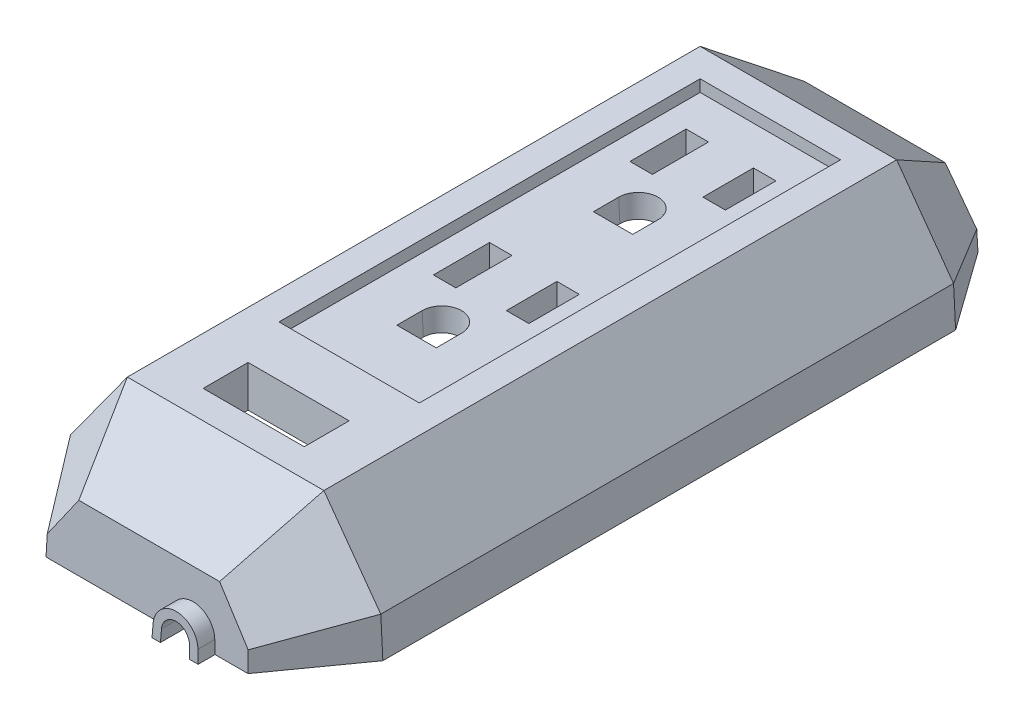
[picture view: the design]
ISO-10303-21;
HEADER;
FILE_DESCRIPTION(('STEP AP214'),'2;1');
FILE_NAME('part.step','',(''),(''),'','','');
FILE_SCHEMA(('AUTOMOTIVE_DESIGN { 1 0 10303 214 1 1 1 1 }'));
ENDSEC;
DATA;
#1=APPLICATION_CONTEXT('core data for automotive mechanical design processes');
#2=APPLICATION_PROTOCOL_DEFINITION('international standard','automotive_design',2000,#1);
#3=PRODUCT_CONTEXT('',#1,'mechanical');
#4=PRODUCT('Part','Part','',(#3));
#5=PRODUCT_RELATED_PRODUCT_CATEGORY('part','',(#4));
#6=PRODUCT_DEFINITION_FORMATION('','',#4);
#7=PRODUCT_DEFINITION_CONTEXT('part definition',#1,'design');
#8=PRODUCT_DEFINITION('design','',#6,#7);
#9=PRODUCT_DEFINITION_SHAPE('','',#8);
#10=(LENGTH_UNIT() NAMED_UNIT(*) SI_UNIT(.MILLI.,.METRE.));
#11=(NAMED_UNIT(*) PLANE_ANGLE_UNIT() SI_UNIT($,.RADIAN.));
#12=(NAMED_UNIT(*) SI_UNIT($,.STERADIAN.) SOLID_ANGLE_UNIT());
#13=UNCERTAINTY_MEASURE_WITH_UNIT(LENGTH_MEASURE(1.E-05),#10,'distance_accuracy_value','');
#14=(GEOMETRIC_REPRESENTATION_CONTEXT(3) GLOBAL_UNCERTAINTY_ASSIGNED_CONTEXT((#13)) GLOBAL_UNIT_ASSIGNED_CONTEXT((#10,
#11,#12)) REPRESENTATION_CONTEXT('',''));
#15=CARTESIAN_POINT('',(0.,0.,0.));
#16=DIRECTION('',(0.,0.,1.));
#17=DIRECTION('',(1.,0.,0.));
#18=AXIS2_PLACEMENT_3D('',#15,#16,#17);
#19=CARTESIAN_POINT('',(23.0679705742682,10.7903350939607,87.0000000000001));
#20=DIRECTION('',(1.,0.,0.));
#21=DIRECTION('',(0.,0.,-1.));
#22=AXIS2_PLACEMENT_3D('',#19,#20,#21);
#23=CYLINDRICAL_SURFACE('',#22,0.790335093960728);
#24=DIRECTION('',(-1.,0.,0.));
#25=VECTOR('',#24,1.);
#26=CARTESIAN_POINT('',(-19.9327032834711,10.7489721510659,86.2107480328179));
#27=LINE('',#26,#25);
#28=CARTESIAN_POINT('',(23.0679705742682,10.7489721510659,86.2107480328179));
#29=VERTEX_POINT('',#28);
#30=CARTESIAN_POINT('',(-23.0679705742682,10.7489721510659,86.2107480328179));
#31=VERTEX_POINT('',#30);
#32=EDGE_CURVE('E1210',#29,#31,#27,.T.);
#33=ORIENTED_EDGE('',*,*,#32,.F.);
#34=CARTESIAN_POINT('',(23.038032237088,10.7903350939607,87.0000000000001));
#35=DIRECTION('',(-0.810073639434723,-0.586328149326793,0.));
#36=DIRECTION('',(0.586328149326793,-0.810073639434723,0.));
#37=AXIS2_PLACEMENT_3D('',#34,#35,#36);
#38=ELLIPSE('',#37,0.975633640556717,0.790335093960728);
#39=CARTESIAN_POINT('',(23.0679705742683,10.7489721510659,87.7892519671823));
#40=VERTEX_POINT('',#39);
#41=EDGE_CURVE('E41',#29,#40,#38,.T.);
#42=ORIENTED_EDGE('',*,*,#41,.T.);
#43=DIRECTION('',(-1.,0.,0.));
#44=VECTOR('',#43,1.);
#45=CARTESIAN_POINT('',(23.0679705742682,10.7489721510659,87.7892519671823));
#46=LINE('',#45,#44);
#47=CARTESIAN_POINT('',(-23.0679705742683,10.7489721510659,87.7892519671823));
#48=VERTEX_POINT('',#47);
#49=EDGE_CURVE('E1213',#48,#40,#46,.F.);
#50=ORIENTED_EDGE('',*,*,#49,.F.);
#51=CARTESIAN_POINT('',(-23.038032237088,10.7903350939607,87.0000000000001));
#52=DIRECTION('',(0.810073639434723,-0.586328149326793,0.));
#53=DIRECTION('',(0.586328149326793,0.810073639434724,0.));
#54=AXIS2_PLACEMENT_3D('',#51,#52,#53);
#55=ELLIPSE('',#54,0.975633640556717,0.790335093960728);
#56=EDGE_CURVE('E11',#48,#31,#55,.T.);
#57=ORIENTED_EDGE('',*,*,#56,.T.);
#58=EDGE_LOOP('',(#33,#42,#50,#57));
#59=FACE_BOUND('',#58,.T.);
#60=ADVANCED_FACE('F34',(#59),#23,.T.);
#61=CARTESIAN_POINT('',(23.0679705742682,10.7903350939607,52.0000000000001));
#62=DIRECTION('',(1.,0.,0.));
#63=DIRECTION('',(0.,0.,-1.));
#64=AXIS2_PLACEMENT_3D('',#61,#62,#63);
#65=CYLINDRICAL_SURFACE('',#64,0.790335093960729);
#66=DIRECTION('',(-1.,0.,0.));
#67=VECTOR('',#66,1.);
#68=CARTESIAN_POINT('',(-19.9327032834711,10.7489721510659,51.2107480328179));
#69=LINE('',#68,#67);
#70=CARTESIAN_POINT('',(23.0679705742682,10.7489721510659,51.2107480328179));
#71=VERTEX_POINT('',#70);
#72=CARTESIAN_POINT('',(-23.0679705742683,10.7489721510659,51.2107480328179));
#73=VERTEX_POINT('',#72);
#74=EDGE_CURVE('E1189',#71,#73,#69,.T.);
#75=ORIENTED_EDGE('',*,*,#74,.F.);
#76=CARTESIAN_POINT('',(23.038032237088,10.7903350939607,52.0000000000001));
#77=DIRECTION('',(-0.810073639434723,-0.586328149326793,0.));
#78=DIRECTION('',(0.586328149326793,-0.810073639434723,0.));
#79=AXIS2_PLACEMENT_3D('',#76,#77,#78);
#80=ELLIPSE('',#79,0.975633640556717,0.790335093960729);
#81=CARTESIAN_POINT('',(23.0679705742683,10.7489721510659,52.7892519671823));
#82=VERTEX_POINT('',#81);
#83=EDGE_CURVE('E1206',#71,#82,#80,.T.);
#84=ORIENTED_EDGE('',*,*,#83,.T.);
#85=DIRECTION('',(-1.,0.,0.));
#86=VECTOR('',#85,1.);
#87=CARTESIAN_POINT('',(23.0679705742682,10.7489721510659,52.7892519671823));
#88=LINE('',#87,#86);
#89=CARTESIAN_POINT('',(-23.0679705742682,10.7489721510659,52.7892519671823));
#90=VERTEX_POINT('',#89);
#91=EDGE_CURVE('E1203',#90,#82,#88,.F.);
#92=ORIENTED_EDGE('',*,*,#91,.F.);
#93=CARTESIAN_POINT('',(-23.038032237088,10.7903350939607,52.0000000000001));
#94=DIRECTION('',(0.810073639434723,-0.586328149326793,0.));
#95=DIRECTION('',(0.586328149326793,0.810073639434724,0.));
#96=AXIS2_PLACEMENT_3D('',#93,#94,#95);
#97=ELLIPSE('',#96,0.975633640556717,0.790335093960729);
#98=EDGE_CURVE('E1208',#90,#73,#97,.T.);
#99=ORIENTED_EDGE('',*,*,#98,.T.);
#100=EDGE_LOOP('',(#75,#84,#92,#99));
#101=FACE_BOUND('',#100,.T.);
#102=ADVANCED_FACE('F1628',(#101),#65,.T.);
#103=CARTESIAN_POINT('',(-17.5,19.5,130.));
#104=DIRECTION('',(0.,-1.,0.));
#105=DIRECTION('',(0.,0.,-1.));
#106=AXIS2_PLACEMENT_3D('',#103,#104,#105);
#107=PLANE('',#106);
#108=DIRECTION('',(1.,0.,0.));
#109=VECTOR('',#108,1.);
#110=CARTESIAN_POINT('',(-9.,19.5,112.423446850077));
#111=LINE('',#110,#109);
#112=CARTESIAN_POINT('',(-10.4234468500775,19.5,112.423446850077));
#113=VERTEX_POINT('',#112);
#114=CARTESIAN_POINT('',(-1.0382427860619,19.5,112.423446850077));
#115=VERTEX_POINT('',#114);
#116=EDGE_CURVE('E1688',#113,#115,#111,.T.);
#117=ORIENTED_EDGE('',*,*,#116,.T.);
#118=DIRECTION('',(0.,0.,1.));
#119=VECTOR('',#118,1.);
#120=CARTESIAN_POINT('',(-1.0382427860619,19.5,130.));
#121=LINE('',#120,#119);
#122=CARTESIAN_POINT('',(-1.0382427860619,19.5,115.519302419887));
#123=VERTEX_POINT('',#122);
#124=EDGE_CURVE('E785',#115,#123,#121,.T.);
#125=ORIENTED_EDGE('',*,*,#124,.T.);
#126=DIRECTION('',(1.,0.,0.));
#127=VECTOR('',#126,1.);
#128=CARTESIAN_POINT('',(28.,19.5,115.519302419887));
#129=LINE('',#128,#127);
#130=CARTESIAN_POINT('',(-16.734010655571,19.5,115.519302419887));
#131=VERTEX_POINT('',#130);
#132=EDGE_CURVE('E1279',#131,#123,#129,.T.);
#133=ORIENTED_EDGE('',*,*,#132,.F.);
#134=DIRECTION('',(0.,0.,-1.));
#135=VECTOR('',#134,1.);
#136=CARTESIAN_POINT('',(-16.734010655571,19.5,130.));
#137=LINE('',#136,#135);
#138=CARTESIAN_POINT('',(-16.734010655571,19.5,88.247873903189));
#139=VERTEX_POINT('',#138);
#140=EDGE_CURVE('E1241',#131,#139,#137,.T.);
#141=ORIENTED_EDGE('',*,*,#140,.T.);
#142=DIRECTION('',(1.,0.,0.));
#143=VECTOR('',#142,1.);
#144=CARTESIAN_POINT('',(-17.5,19.5,88.247873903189));
#145=LINE('',#144,#143);
#146=CARTESIAN_POINT('',(-13.9234468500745,19.5,88.247873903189));
#147=VERTEX_POINT('',#146);
#148=EDGE_CURVE('E1755',#147,#139,#145,.F.);
#149=ORIENTED_EDGE('',*,*,#148,.F.);
#150=DIRECTION('',(0.,0.,1.));
#151=VECTOR('',#150,1.);
#152=CARTESIAN_POINT('',(-13.9234468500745,19.5,19.0000000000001));
#153=LINE('',#152,#151);
#154=CARTESIAN_POINT('',(-13.9234468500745,19.5,95.4234468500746));
#155=VERTEX_POINT('',#154);
#156=EDGE_CURVE('E1675',#147,#155,#153,.T.);
#157=ORIENTED_EDGE('',*,*,#156,.T.);
#158=DIRECTION('',(1.,0.,0.));
#159=VECTOR('',#158,1.);
#160=CARTESIAN_POINT('',(12.5,19.5,95.4234468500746));
#161=LINE('',#160,#159);
#162=CARTESIAN_POINT('',(-1.0382427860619,19.5,95.4234468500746));
#163=VERTEX_POINT('',#162);
#164=EDGE_CURVE('E1676',#155,#163,#161,.T.);
#165=ORIENTED_EDGE('',*,*,#164,.T.);
#166=DIRECTION('',(0.,0.,1.));
#167=VECTOR('',#166,1.);
#168=CARTESIAN_POINT('',(-1.0382427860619,19.5,130.));
#169=LINE('',#168,#167);
#170=CARTESIAN_POINT('',(-1.0382427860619,19.5,101.576553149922));
#171=VERTEX_POINT('',#170);
#172=EDGE_CURVE('E1722',#163,#171,#169,.T.);
#173=ORIENTED_EDGE('',*,*,#172,.T.);
#174=DIRECTION('',(-1.,0.,0.));
#175=VECTOR('',#174,1.);
#176=CARTESIAN_POINT('',(-9.,19.5,101.576553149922));
#177=LINE('',#176,#175);
#178=CARTESIAN_POINT('',(-10.4234468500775,19.5,101.576553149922));
#179=VERTEX_POINT('',#178);
#180=EDGE_CURVE('E1687',#171,#179,#177,.T.);
#181=ORIENTED_EDGE('',*,*,#180,.T.);
#182=DIRECTION('',(0.,0.,1.));
#183=VECTOR('',#182,1.);
#184=CARTESIAN_POINT('',(-10.4234468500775,19.5,111.));
#185=LINE('',#184,#183);
#186=EDGE_CURVE('E1652',#179,#113,#185,.T.);
#187=ORIENTED_EDGE('',*,*,#186,.T.);
#188=EDGE_LOOP('',(#117,#125,#133,#141,#149,#157,#165,#173,#181,#187));
#189=FACE_BOUND('',#188,.T.);
#190=ADVANCED_FACE('F1632',(#189),#107,.T.);
#191=CARTESIAN_POINT('',(-9.,20.9214960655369,112.497944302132));
#192=DIRECTION('',(0.,-0.0523359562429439,0.998629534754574));
#193=DIRECTION('',(0.,-0.998629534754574,-0.0523359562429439));
#194=AXIS2_PLACEMENT_3D('',#191,#192,#193);
#195=PLANE('',#194);
#196=DIRECTION('',(1.,0.,0.));
#197=VECTOR('',#196,1.);
#198=CARTESIAN_POINT('',(-9.,13.9999999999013,112.135204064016));
#199=LINE('',#198,#197);
#200=CARTESIAN_POINT('',(-10.1352040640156,13.9999999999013,112.135204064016));
#201=VERTEX_POINT('',#200);
#202=CARTESIAN_POINT('',(-0.750000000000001,13.9999999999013,112.135204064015));
#203=VERTEX_POINT('',#202);
#204=EDGE_CURVE('E797',#201,#203,#199,.T.);
#205=ORIENTED_EDGE('',*,*,#204,.T.);
#206=DIRECTION('',(-0.052264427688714,0.997264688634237,0.052264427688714));
#207=VECTOR('',#206,1.);
#208=CARTESIAN_POINT('',(-1.13428484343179,21.3325916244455,112.519488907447));
#209=LINE('',#208,#207);
#210=EDGE_CURVE('E779',#203,#115,#209,.T.);
#211=ORIENTED_EDGE('',*,*,#210,.T.);
#212=ORIENTED_EDGE('',*,*,#116,.F.);
#213=DIRECTION('',(-0.052264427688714,0.997264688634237,0.052264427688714));
#214=VECTOR('',#213,1.);
#215=CARTESIAN_POINT('',(-10.4938525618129,20.8434210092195,112.493852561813));
#216=LINE('',#215,#214);
#217=EDGE_CURVE('E805',#201,#113,#216,.T.);
#218=ORIENTED_EDGE('',*,*,#217,.F.);
#219=EDGE_LOOP('',(#205,#211,#212,#218));
#220=FACE_BOUND('',#219,.T.);
#221=ADVANCED_FACE('F803',(#220),#195,.T.);
#222=CARTESIAN_POINT('',(12.5,20.9214960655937,95.4979443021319));
#223=DIRECTION('',(0.,-0.0523359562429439,0.998629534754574));
#224=DIRECTION('',(0.,-0.998629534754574,-0.0523359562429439));
#225=AXIS2_PLACEMENT_3D('',#222,#223,#224);
#226=PLANE('',#225);
#227=DIRECTION('',(1.,0.,0.));
#228=VECTOR('',#227,1.);
#229=CARTESIAN_POINT('',(12.5,17.4999999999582,95.3186312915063));
#230=LINE('',#229,#228);
#231=CARTESIAN_POINT('',(-13.8186312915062,17.4999999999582,95.3186312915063));
#232=VERTEX_POINT('',#231);
#233=CARTESIAN_POINT('',(-0.93342722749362,17.4999999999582,95.3186312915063));
#234=VERTEX_POINT('',#233);
#235=EDGE_CURVE('E1353',#232,#234,#230,.T.);
#236=ORIENTED_EDGE('',*,*,#235,.T.);
#237=DIRECTION('',(-0.052264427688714,0.997264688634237,0.052264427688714));
#238=VECTOR('',#237,1.);
#239=CARTESIAN_POINT('',(-1.07555607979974,20.2119800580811,95.4607601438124));
#240=LINE('',#239,#238);
#241=EDGE_CURVE('E1720',#234,#163,#240,.T.);
#242=ORIENTED_EDGE('',*,*,#241,.T.);
#243=ORIENTED_EDGE('',*,*,#164,.F.);
#244=DIRECTION('',(-0.052264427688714,0.997264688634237,0.052264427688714));
#245=VECTOR('',#244,1.);
#246=CARTESIAN_POINT('',(-13.7889847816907,16.934310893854,95.2889847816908));
#247=LINE('',#246,#245);
#248=EDGE_CURVE('E1362',#232,#155,#247,.T.);
#249=ORIENTED_EDGE('',*,*,#248,.F.);
#250=EDGE_LOOP('',(#236,#242,#243,#249));
#251=FACE_BOUND('',#250,.T.);
#252=ADVANCED_FACE('F1845',(#251),#226,.T.);
#253=CARTESIAN_POINT('',(12.5,17.4999999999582,94.0000000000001));
#254=DIRECTION('',(0.,-1.,0.));
#255=DIRECTION('',(0.,0.,-1.));
#256=AXIS2_PLACEMENT_3D('',#253,#254,#255);
#257=PLANE('',#256);
#258=DIRECTION('',(1.,0.,0.));
#259=VECTOR('',#258,1.);
#260=CARTESIAN_POINT('',(12.5,17.4999999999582,88.1430583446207));
#261=LINE('',#260,#259);
#262=CARTESIAN_POINT('',(-0.933427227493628,17.4999999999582,88.1430583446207));
#263=VERTEX_POINT('',#262);
#264=CARTESIAN_POINT('',(-13.8186312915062,17.4999999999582,88.1430583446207));
#265=VERTEX_POINT('',#264);
#266=EDGE_CURVE('E1199',#263,#265,#261,.F.);
#267=ORIENTED_EDGE('',*,*,#266,.F.);
#268=DIRECTION('',(0.,0.,1.));
#269=VECTOR('',#268,1.);
#270=CARTESIAN_POINT('',(-0.933427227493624,17.4999999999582,94.0000000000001));
#271=LINE('',#270,#269);
#272=EDGE_CURVE('E1718',#263,#234,#271,.T.);
#273=ORIENTED_EDGE('',*,*,#272,.T.);
#274=ORIENTED_EDGE('',*,*,#235,.F.);
#275=DIRECTION('',(0.,0.,1.));
#276=VECTOR('',#275,1.);
#277=CARTESIAN_POINT('',(-13.8186312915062,17.4999999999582,19.0000000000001));
#278=LINE('',#277,#276);
#279=EDGE_CURVE('E1372',#265,#232,#278,.T.);
#280=ORIENTED_EDGE('',*,*,#279,.F.);
#281=EDGE_LOOP('',(#267,#273,#274,#280));
#282=FACE_BOUND('',#281,.T.);
#283=ADVANCED_FACE('F1857',(#282),#257,.T.);
#284=CARTESIAN_POINT('',(-9.,20.9214960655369,101.502055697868));
#285=DIRECTION('',(0.,-0.0523359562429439,-0.998629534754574));
#286=DIRECTION('',(0.,0.998629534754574,-0.0523359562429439));
#287=AXIS2_PLACEMENT_3D('',#284,#285,#286);
#288=PLANE('',#287);
#289=ORIENTED_EDGE('',*,*,#180,.F.);
#290=DIRECTION('',(0.052264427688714,-0.997264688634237,0.052264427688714));
#291=VECTOR('',#290,1.);
#292=CARTESIAN_POINT('',(-1.13428484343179,21.3325916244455,101.480511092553));
#293=LINE('',#292,#291);
#294=CARTESIAN_POINT('',(-0.750000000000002,13.9999999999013,101.864795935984));
#295=VERTEX_POINT('',#294);
#296=EDGE_CURVE('E1724',#171,#295,#293,.T.);
#297=ORIENTED_EDGE('',*,*,#296,.T.);
#298=DIRECTION('',(-1.,0.,0.));
#299=VECTOR('',#298,1.);
#300=CARTESIAN_POINT('',(-9.,13.9999999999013,101.864795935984));
#301=LINE('',#300,#299);
#302=CARTESIAN_POINT('',(-10.1352040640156,13.9999999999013,101.864795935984));
#303=VERTEX_POINT('',#302);
#304=EDGE_CURVE('E810',#295,#303,#301,.T.);
#305=ORIENTED_EDGE('',*,*,#304,.T.);
#306=DIRECTION('',(-0.052264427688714,0.997264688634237,-0.052264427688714));
#307=VECTOR('',#306,1.);
#308=CARTESIAN_POINT('',(-10.4938525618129,20.8434210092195,101.506147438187));
#309=LINE('',#308,#307);
#310=EDGE_CURVE('E1382',#303,#179,#309,.T.);
#311=ORIENTED_EDGE('',*,*,#310,.T.);
#312=EDGE_LOOP('',(#289,#297,#305,#311));
#313=FACE_BOUND('',#312,.T.);
#314=ADVANCED_FACE('F2803',(#313),#288,.T.);
#315=DIRECTION('',(0.,0.,-1.));
#316=VECTOR('',#315,1.);
#317=CARTESIAN_POINT('',(16.734010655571,19.5,130.));
#318=LINE('',#317,#316);
#319=CARTESIAN_POINT('',(16.734010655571,19.5,85.7521260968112));
#320=VERTEX_POINT('',#319);
#321=CARTESIAN_POINT('',(16.734010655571,19.5,53.247873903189));
#322=VERTEX_POINT('',#321);
#323=EDGE_CURVE('E1232',#320,#322,#318,.T.);
#324=ORIENTED_EDGE('',*,*,#323,.F.);
#325=DIRECTION('',(-1.,0.,0.));
#326=VECTOR('',#325,1.);
#327=CARTESIAN_POINT('',(-17.5,19.5,85.7521260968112));
#328=LINE('',#327,#326);
#329=CARTESIAN_POINT('',(13.9234468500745,19.5,85.7521260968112));
#330=VERTEX_POINT('',#329);
#331=EDGE_CURVE('E1639',#320,#330,#328,.T.);
#332=ORIENTED_EDGE('',*,*,#331,.T.);
#333=DIRECTION('',(0.,0.,-1.));
#334=VECTOR('',#333,1.);
#335=CARTESIAN_POINT('',(13.9234468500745,19.5,19.0000000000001));
#336=LINE('',#335,#334);
#337=CARTESIAN_POINT('',(13.9234468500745,19.5,53.247873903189));
#338=VERTEX_POINT('',#337);
#339=EDGE_CURVE('E1648',#330,#338,#336,.T.);
#340=ORIENTED_EDGE('',*,*,#339,.T.);
#341=DIRECTION('',(1.,0.,0.));
#342=VECTOR('',#341,1.);
#343=CARTESIAN_POINT('',(-17.5,19.5,53.247873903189));
#344=LINE('',#343,#342);
#345=EDGE_CURVE('E1645',#322,#338,#344,.F.);
#346=ORIENTED_EDGE('',*,*,#345,.F.);
#347=EDGE_LOOP('',(#324,#332,#340,#346));
#348=FACE_BOUND('',#347,.T.);
#349=ADVANCED_FACE('F1646',(#348),#107,.T.);
#350=CARTESIAN_POINT('',(-13.9234468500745,19.5,53.247873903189));
#351=VERTEX_POINT('',#350);
#352=CARTESIAN_POINT('',(-13.9234468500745,19.5,85.7521260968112));
#353=VERTEX_POINT('',#352);
#354=EDGE_CURVE('E1674',#351,#353,#153,.T.);
#355=ORIENTED_EDGE('',*,*,#354,.T.);
#356=CARTESIAN_POINT('',(-16.734010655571,19.5,85.7521260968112));
#357=VERTEX_POINT('',#356);
#358=EDGE_CURVE('E1748',#353,#357,#328,.T.);
#359=ORIENTED_EDGE('',*,*,#358,.T.);
#360=CARTESIAN_POINT('',(-16.734010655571,19.5,53.247873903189));
#361=VERTEX_POINT('',#360);
#362=EDGE_CURVE('E1246',#357,#361,#137,.T.);
#363=ORIENTED_EDGE('',*,*,#362,.T.);
#364=EDGE_CURVE('E1653',#351,#361,#344,.F.);
#365=ORIENTED_EDGE('',*,*,#364,.F.);
#366=EDGE_LOOP('',(#355,#359,#363,#365));
#367=FACE_BOUND('',#366,.T.);
#368=ADVANCED_FACE('F2042',(#367),#107,.T.);
#369=CARTESIAN_POINT('',(13.9979443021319,20.9214960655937,19.0000000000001));
#370=DIRECTION('',(0.998629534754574,-0.0523359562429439,0.));
#371=DIRECTION('',(0.0523359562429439,0.998629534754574,0.));
#372=AXIS2_PLACEMENT_3D('',#369,#370,#371);
#373=PLANE('',#372);
#374=ORIENTED_EDGE('',*,*,#339,.F.);
#375=DIRECTION('',(-0.052264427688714,-0.997264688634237,0.052264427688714));
#376=VECTOR('',#375,1.);
#377=CARTESIAN_POINT('',(14.1800789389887,24.3968319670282,85.495494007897));
#378=LINE('',#377,#376);
#379=CARTESIAN_POINT('',(13.8186312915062,17.4999999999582,85.8569416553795));
#380=VERTEX_POINT('',#379);
#381=EDGE_CURVE('E1745',#330,#380,#378,.T.);
#382=ORIENTED_EDGE('',*,*,#381,.T.);
#383=DIRECTION('',(0.,0.,-1.));
#384=VECTOR('',#383,1.);
#385=CARTESIAN_POINT('',(13.8186312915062,17.4999999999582,19.0000000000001));
#386=LINE('',#385,#384);
#387=CARTESIAN_POINT('',(13.8186312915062,17.4999999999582,53.1430583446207));
#388=VERTEX_POINT('',#387);
#389=EDGE_CURVE('E1358',#380,#388,#386,.T.);
#390=ORIENTED_EDGE('',*,*,#389,.T.);
#391=DIRECTION('',(0.052264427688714,0.997264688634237,0.052264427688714));
#392=VECTOR('',#391,1.);
#393=CARTESIAN_POINT('',(13.9041903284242,19.1325636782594,53.2286173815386));
#394=LINE('',#393,#392);
#395=EDGE_CURVE('E1658',#338,#388,#394,.F.);
#396=ORIENTED_EDGE('',*,*,#395,.F.);
#397=EDGE_LOOP('',(#374,#382,#390,#396));
#398=FACE_BOUND('',#397,.T.);
#399=ADVANCED_FACE('F1840',(#398),#373,.T.);
#400=CARTESIAN_POINT('',(-13.9979443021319,20.9214960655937,19.0000000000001));
#401=DIRECTION('',(-0.998629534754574,-0.0523359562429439,0.));
#402=DIRECTION('',(0.0523359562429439,-0.998629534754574,0.));
#403=AXIS2_PLACEMENT_3D('',#400,#401,#402);
#404=PLANE('',#403);
#405=CARTESIAN_POINT('',(-13.8186312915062,17.4999999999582,53.1430583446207));
#406=VERTEX_POINT('',#405);
#407=CARTESIAN_POINT('',(-13.8186312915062,17.4999999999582,85.8569416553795));
#408=VERTEX_POINT('',#407);
#409=EDGE_CURVE('E1371',#406,#408,#278,.T.);
#410=ORIENTED_EDGE('',*,*,#409,.T.);
#411=DIRECTION('',(-0.052264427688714,0.997264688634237,-0.052264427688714));
#412=VECTOR('',#411,1.);
#413=CARTESIAN_POINT('',(-14.1800789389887,24.3968319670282,85.495494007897));
#414=LINE('',#413,#412);
#415=EDGE_CURVE('E1742',#408,#353,#414,.T.);
#416=ORIENTED_EDGE('',*,*,#415,.T.);
#417=ORIENTED_EDGE('',*,*,#354,.F.);
#418=DIRECTION('',(0.052264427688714,-0.997264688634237,-0.052264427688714));
#419=VECTOR('',#418,1.);
#420=CARTESIAN_POINT('',(-13.9041903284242,19.1325636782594,53.2286173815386));
#421=LINE('',#420,#419);
#422=EDGE_CURVE('E1766',#406,#351,#421,.F.);
#423=ORIENTED_EDGE('',*,*,#422,.F.);
#424=EDGE_LOOP('',(#410,#416,#417,#423));
#425=FACE_BOUND('',#424,.T.);
#426=ADVANCED_FACE('F1849',(#425),#404,.T.);
#427=CARTESIAN_POINT('',(0.,17.4999999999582,77.5000000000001));
#428=DIRECTION('',(0.,-1.,0.));
#429=DIRECTION('',(0.,0.,-1.));
#430=AXIS2_PLACEMENT_3D('',#427,#428,#429);
#431=CIRCLE('',#430,4.92344685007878);
#432=CARTESIAN_POINT('',(4.92344685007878,17.4999999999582,77.5000000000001));
#433=VERTEX_POINT('',#432);
#434=CARTESIAN_POINT('',(-4.92344685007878,17.4999999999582,77.5000000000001));
#435=VERTEX_POINT('',#434);
#436=EDGE_CURVE('E1380',#433,#435,#431,.F.);
#437=ORIENTED_EDGE('',*,*,#436,.T.);
#438=DIRECTION('',(0.,0.,1.));
#439=VECTOR('',#438,1.);
#440=CARTESIAN_POINT('',(-4.92344685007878,17.4999999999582,77.5000000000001));
#441=LINE('',#440,#439);
#442=CARTESIAN_POINT('',(-4.92344685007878,17.4999999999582,83.4234468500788));
#443=VERTEX_POINT('',#442);
#444=EDGE_CURVE('E1376',#435,#443,#441,.T.);
#445=ORIENTED_EDGE('',*,*,#444,.T.);
#446=DIRECTION('',(1.,0.,0.));
#447=VECTOR('',#446,1.);
#448=CARTESIAN_POINT('',(-3.5,17.4999999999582,83.4234468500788));
#449=LINE('',#448,#447);
#450=CARTESIAN_POINT('',(4.92344685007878,17.4999999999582,83.4234468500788));
#451=VERTEX_POINT('',#450);
#452=EDGE_CURVE('E1379',#443,#451,#449,.T.);
#453=ORIENTED_EDGE('',*,*,#452,.T.);
#454=DIRECTION('',(0.,0.,-1.));
#455=VECTOR('',#454,1.);
#456=CARTESIAN_POINT('',(4.92344685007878,17.4999999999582,82.0000000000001));
#457=LINE('',#456,#455);
#458=EDGE_CURVE('E1383',#451,#433,#457,.T.);
#459=ORIENTED_EDGE('',*,*,#458,.T.);
#460=EDGE_LOOP('',(#437,#445,#453,#459));
#461=FACE_BOUND('',#460,.T.);
#462=ORIENTED_EDGE('',*,*,#409,.F.);
#463=DIRECTION('',(1.,0.,0.));
#464=VECTOR('',#463,1.);
#465=CARTESIAN_POINT('',(12.5,17.4999999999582,53.1430583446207));
#466=LINE('',#465,#464);
#467=EDGE_CURVE('E1184',#388,#406,#466,.F.);
#468=ORIENTED_EDGE('',*,*,#467,.F.);
#469=ORIENTED_EDGE('',*,*,#389,.F.);
#470=DIRECTION('',(-1.,0.,0.));
#471=VECTOR('',#470,1.);
#472=CARTESIAN_POINT('',(12.5,17.4999999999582,85.8569416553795));
#473=LINE('',#472,#471);
#474=EDGE_CURVE('E1177',#380,#408,#473,.T.);
#475=ORIENTED_EDGE('',*,*,#474,.T.);
#476=EDGE_LOOP('',(#462,#468,#469,#475));
#477=FACE_BOUND('',#476,.T.);
#478=DIRECTION('',(0.,0.,-1.));
#479=VECTOR('',#478,1.);
#480=CARTESIAN_POINT('',(9.42344685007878,17.4999999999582,70.0000000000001));
#481=LINE('',#480,#479);
#482=CARTESIAN_POINT('',(9.42344685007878,17.4999999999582,71.4234468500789));
#483=VERTEX_POINT('',#482);
#484=CARTESIAN_POINT('',(9.42344685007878,17.4999999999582,59.5765531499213));
#485=VERTEX_POINT('',#484);
#486=EDGE_CURVE('E1401',#483,#485,#481,.T.);
#487=ORIENTED_EDGE('',*,*,#486,.T.);
#488=DIRECTION('',(-1.,0.,0.));
#489=VECTOR('',#488,1.);
#490=CARTESIAN_POINT('',(8.,17.4999999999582,59.5765531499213));
#491=LINE('',#490,#489);
#492=CARTESIAN_POINT('',(2.57655314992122,17.4999999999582,59.5765531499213));
#493=VERTEX_POINT('',#492);
#494=EDGE_CURVE('E1404',#485,#493,#491,.T.);
#495=ORIENTED_EDGE('',*,*,#494,.T.);
#496=DIRECTION('',(0.,0.,1.));
#497=VECTOR('',#496,1.);
#498=CARTESIAN_POINT('',(2.57655314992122,17.4999999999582,61.0000000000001));
#499=LINE('',#498,#497);
#500=CARTESIAN_POINT('',(2.57655314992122,17.4999999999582,71.4234468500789));
#501=VERTEX_POINT('',#500);
#502=EDGE_CURVE('E1408',#493,#501,#499,.T.);
#503=ORIENTED_EDGE('',*,*,#502,.T.);
#504=DIRECTION('',(1.,0.,0.));
#505=VECTOR('',#504,1.);
#506=CARTESIAN_POINT('',(4.,17.4999999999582,71.4234468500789));
#507=LINE('',#506,#505);
#508=EDGE_CURVE('E1405',#501,#483,#507,.T.);
#509=ORIENTED_EDGE('',*,*,#508,.T.);
#510=EDGE_LOOP('',(#487,#495,#503,#509));
#511=FACE_BOUND('',#510,.T.);
#512=DIRECTION('',(0.,0.,-1.));
#513=VECTOR('',#512,1.);
#514=CARTESIAN_POINT('',(-2.57655314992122,17.4999999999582,71.0000000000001));
#515=LINE('',#514,#513);
#516=CARTESIAN_POINT('',(-2.57655314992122,17.4999999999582,72.4234468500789));
#517=VERTEX_POINT('',#516);
#518=CARTESIAN_POINT('',(-2.57655314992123,17.4999999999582,59.5765531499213));
#519=VERTEX_POINT('',#518);
#520=EDGE_CURVE('E1388',#517,#519,#515,.T.);
#521=ORIENTED_EDGE('',*,*,#520,.T.);
#522=DIRECTION('',(-1.,0.,0.));
#523=VECTOR('',#522,1.);
#524=CARTESIAN_POINT('',(-4.,17.4999999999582,59.5765531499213));
#525=LINE('',#524,#523);
#526=CARTESIAN_POINT('',(-9.42344685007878,17.4999999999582,59.5765531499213));
#527=VERTEX_POINT('',#526);
#528=EDGE_CURVE('E1391',#519,#527,#525,.T.);
#529=ORIENTED_EDGE('',*,*,#528,.T.);
#530=DIRECTION('',(0.,0.,1.));
#531=VECTOR('',#530,1.);
#532=CARTESIAN_POINT('',(-9.42344685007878,17.4999999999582,61.0000000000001));
#533=LINE('',#532,#531);
#534=CARTESIAN_POINT('',(-9.42344685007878,17.4999999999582,72.4234468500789));
#535=VERTEX_POINT('',#534);
#536=EDGE_CURVE('E1395',#527,#535,#533,.T.);
#537=ORIENTED_EDGE('',*,*,#536,.T.);
#538=DIRECTION('',(1.,0.,0.));
#539=VECTOR('',#538,1.);
#540=CARTESIAN_POINT('',(-8.00000000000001,17.4999999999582,72.4234468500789));
#541=LINE('',#540,#539);
#542=EDGE_CURVE('E1392',#535,#517,#541,.T.);
#543=ORIENTED_EDGE('',*,*,#542,.T.);
#544=EDGE_LOOP('',(#521,#529,#537,#543));
#545=FACE_BOUND('',#544,.T.);
#546=ADVANCED_FACE('F1615',(#461,#477,#511,#545),#257,.T.);
#547=DIRECTION('',(-1.,0.,0.));
#548=VECTOR('',#547,1.);
#549=CARTESIAN_POINT('',(12.5,19.5,17.5765531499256));
#550=LINE('',#549,#548);
#551=CARTESIAN_POINT('',(13.9234468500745,19.5,17.5765531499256));
#552=VERTEX_POINT('',#551);
#553=CARTESIAN_POINT('',(-13.9234468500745,19.5,17.5765531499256));
#554=VERTEX_POINT('',#553);
#555=EDGE_CURVE('E1682',#552,#554,#550,.T.);
#556=ORIENTED_EDGE('',*,*,#555,.T.);
#557=CARTESIAN_POINT('',(-13.9234468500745,19.5,50.7521260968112));
#558=VERTEX_POINT('',#557);
#559=EDGE_CURVE('E1670',#554,#558,#153,.T.);
#560=ORIENTED_EDGE('',*,*,#559,.T.);
#561=DIRECTION('',(-1.,0.,0.));
#562=VECTOR('',#561,1.);
#563=CARTESIAN_POINT('',(-17.5,19.5,50.7521260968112));
#564=LINE('',#563,#562);
#565=CARTESIAN_POINT('',(-16.734010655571,19.5,50.7521260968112));
#566=VERTEX_POINT('',#565);
#567=EDGE_CURVE('E1764',#558,#566,#564,.T.);
#568=ORIENTED_EDGE('',*,*,#567,.T.);
#569=CARTESIAN_POINT('',(-16.734010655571,19.5,14.4806975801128));
#570=VERTEX_POINT('',#569);
#571=EDGE_CURVE('E1248',#566,#570,#137,.T.);
#572=ORIENTED_EDGE('',*,*,#571,.T.);
#573=DIRECTION('',(1.,0.,0.));
#574=VECTOR('',#573,1.);
#575=CARTESIAN_POINT('',(-17.5,19.5,14.4806975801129));
#576=LINE('',#575,#574);
#577=CARTESIAN_POINT('',(16.734010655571,19.5,14.4806975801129));
#578=VERTEX_POINT('',#577);
#579=EDGE_CURVE('E1664',#578,#570,#576,.F.);
#580=ORIENTED_EDGE('',*,*,#579,.F.);
#581=CARTESIAN_POINT('',(16.734010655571,19.5,50.7521260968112));
#582=VERTEX_POINT('',#581);
#583=EDGE_CURVE('E1234',#582,#578,#318,.T.);
#584=ORIENTED_EDGE('',*,*,#583,.F.);
#585=CARTESIAN_POINT('',(13.9234468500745,19.5,50.7521260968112));
#586=VERTEX_POINT('',#585);
#587=EDGE_CURVE('E1765',#582,#586,#564,.T.);
#588=ORIENTED_EDGE('',*,*,#587,.T.);
#589=EDGE_CURVE('E1459',#586,#552,#336,.T.);
#590=ORIENTED_EDGE('',*,*,#589,.T.);
#591=EDGE_LOOP('',(#556,#560,#568,#572,#580,#584,#588,#590));
#592=FACE_BOUND('',#591,.T.);
#593=ADVANCED_FACE('F1772',(#592),#107,.T.);
#594=ORIENTED_EDGE('',*,*,#589,.F.);
#595=DIRECTION('',(-0.052264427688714,-0.997264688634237,0.052264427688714));
#596=VECTOR('',#595,1.);
#597=CARTESIAN_POINT('',(14.0844739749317,22.5725805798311,50.591098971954));
#598=LINE('',#597,#596);
#599=CARTESIAN_POINT('',(13.8186312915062,17.4999999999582,50.8569416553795));
#600=VERTEX_POINT('',#599);
#601=EDGE_CURVE('E1761',#586,#600,#598,.T.);
#602=ORIENTED_EDGE('',*,*,#601,.T.);
#603=CARTESIAN_POINT('',(13.8186312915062,17.4999999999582,17.6813687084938));
#604=VERTEX_POINT('',#603);
#605=EDGE_CURVE('E1359',#600,#604,#386,.T.);
#606=ORIENTED_EDGE('',*,*,#605,.T.);
#607=DIRECTION('',(0.052264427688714,0.997264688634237,-0.052264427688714));
#608=VECTOR('',#607,1.);
#609=CARTESIAN_POINT('',(13.9938525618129,20.8434210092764,17.5061474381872));
#610=LINE('',#609,#608);
#611=EDGE_CURVE('E1349',#604,#552,#610,.T.);
#612=ORIENTED_EDGE('',*,*,#611,.T.);
#613=EDGE_LOOP('',(#594,#602,#606,#612));
#614=FACE_BOUND('',#613,.T.);
#615=ADVANCED_FACE('F1776',(#614),#373,.T.);
#616=CARTESIAN_POINT('',(-13.8186312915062,17.4999999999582,17.6813687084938));
#617=VERTEX_POINT('',#616);
#618=CARTESIAN_POINT('',(-13.8186312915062,17.4999999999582,50.8569416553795));
#619=VERTEX_POINT('',#618);
#620=EDGE_CURVE('E1368',#617,#619,#278,.T.);
#621=ORIENTED_EDGE('',*,*,#620,.T.);
#622=DIRECTION('',(-0.052264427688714,0.997264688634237,-0.052264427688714));
#623=VECTOR('',#622,1.);
#624=CARTESIAN_POINT('',(-14.0844739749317,22.5725805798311,50.591098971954));
#625=LINE('',#624,#623);
#626=EDGE_CURVE('E1758',#619,#558,#625,.T.);
#627=ORIENTED_EDGE('',*,*,#626,.T.);
#628=ORIENTED_EDGE('',*,*,#559,.F.);
#629=DIRECTION('',(-0.052264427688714,0.997264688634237,-0.052264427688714));
#630=VECTOR('',#629,1.);
#631=CARTESIAN_POINT('',(-13.9255633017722,19.5403843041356,17.5744366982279));
#632=LINE('',#631,#630);
#633=EDGE_CURVE('E1352',#617,#554,#632,.T.);
#634=ORIENTED_EDGE('',*,*,#633,.F.);
#635=EDGE_LOOP('',(#621,#627,#628,#634));
#636=FACE_BOUND('',#635,.T.);
#637=ADVANCED_FACE('F1786',(#636),#404,.T.);
#638=CARTESIAN_POINT('',(0.,17.4999999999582,42.5000000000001));
#639=DIRECTION('',(0.,-1.,0.));
#640=DIRECTION('',(0.,0.,-1.));
#641=AXIS2_PLACEMENT_3D('',#638,#639,#640);
#642=CIRCLE('',#641,4.92344685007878);
#643=CARTESIAN_POINT('',(4.92344685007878,17.4999999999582,42.5000000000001));
#644=VERTEX_POINT('',#643);
#645=CARTESIAN_POINT('',(-4.92344685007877,17.4999999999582,42.5000000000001));
#646=VERTEX_POINT('',#645);
#647=EDGE_CURVE('E1418',#644,#646,#642,.F.);
#648=ORIENTED_EDGE('',*,*,#647,.T.);
#649=DIRECTION('',(0.,0.,1.));
#650=VECTOR('',#649,1.);
#651=CARTESIAN_POINT('',(-4.92344685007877,17.4999999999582,42.5000000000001));
#652=LINE('',#651,#650);
#653=CARTESIAN_POINT('',(-4.92344685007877,17.4999999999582,48.4234468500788));
#654=VERTEX_POINT('',#653);
#655=EDGE_CURVE('E1414',#646,#654,#652,.T.);
#656=ORIENTED_EDGE('',*,*,#655,.T.);
#657=DIRECTION('',(1.,0.,0.));
#658=VECTOR('',#657,1.);
#659=CARTESIAN_POINT('',(-3.49999999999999,17.4999999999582,48.4234468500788));
#660=LINE('',#659,#658);
#661=CARTESIAN_POINT('',(4.92344685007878,17.4999999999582,48.4234468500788));
#662=VERTEX_POINT('',#661);
#663=EDGE_CURVE('E1417',#654,#662,#660,.T.);
#664=ORIENTED_EDGE('',*,*,#663,.T.);
#665=DIRECTION('',(0.,0.,-1.));
#666=VECTOR('',#665,1.);
#667=CARTESIAN_POINT('',(4.92344685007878,17.4999999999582,47.0000000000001));
#668=LINE('',#667,#666);
#669=EDGE_CURVE('E1421',#662,#644,#668,.T.);
#670=ORIENTED_EDGE('',*,*,#669,.T.);
#671=EDGE_LOOP('',(#648,#656,#664,#670));
#672=FACE_BOUND('',#671,.T.);
#673=ORIENTED_EDGE('',*,*,#620,.F.);
#674=DIRECTION('',(-1.,0.,0.));
#675=VECTOR('',#674,1.);
#676=CARTESIAN_POINT('',(12.5,17.4999999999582,17.6813687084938));
#677=LINE('',#676,#675);
#678=EDGE_CURVE('E1357',#604,#617,#677,.T.);
#679=ORIENTED_EDGE('',*,*,#678,.F.);
#680=ORIENTED_EDGE('',*,*,#605,.F.);
#681=DIRECTION('',(-1.,0.,0.));
#682=VECTOR('',#681,1.);
#683=CARTESIAN_POINT('',(12.5,17.4999999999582,50.8569416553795));
#684=LINE('',#683,#682);
#685=EDGE_CURVE('E1128',#600,#619,#684,.T.);
#686=ORIENTED_EDGE('',*,*,#685,.T.);
#687=EDGE_LOOP('',(#673,#679,#680,#686));
#688=FACE_BOUND('',#687,.T.);
#689=DIRECTION('',(0.,0.,-1.));
#690=VECTOR('',#689,1.);
#691=CARTESIAN_POINT('',(9.42344685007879,17.4999999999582,35.0000000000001));
#692=LINE('',#691,#690);
#693=CARTESIAN_POINT('',(9.42344685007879,17.4999999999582,36.4234468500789));
#694=VERTEX_POINT('',#693);
#695=CARTESIAN_POINT('',(9.42344685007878,17.4999999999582,24.5765531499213));
#696=VERTEX_POINT('',#695);
#697=EDGE_CURVE('E1439',#694,#696,#692,.T.);
#698=ORIENTED_EDGE('',*,*,#697,.T.);
#699=DIRECTION('',(-1.,0.,0.));
#700=VECTOR('',#699,1.);
#701=CARTESIAN_POINT('',(8.00000000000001,17.4999999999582,24.5765531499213));
#702=LINE('',#701,#700);
#703=CARTESIAN_POINT('',(2.57655314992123,17.4999999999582,24.5765531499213));
#704=VERTEX_POINT('',#703);
#705=EDGE_CURVE('E1442',#696,#704,#702,.T.);
#706=ORIENTED_EDGE('',*,*,#705,.T.);
#707=DIRECTION('',(0.,0.,1.));
#708=VECTOR('',#707,1.);
#709=CARTESIAN_POINT('',(2.57655314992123,17.4999999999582,26.0000000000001));
#710=LINE('',#709,#708);
#711=CARTESIAN_POINT('',(2.57655314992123,17.4999999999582,36.4234468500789));
#712=VERTEX_POINT('',#711);
#713=EDGE_CURVE('E1446',#704,#712,#710,.T.);
#714=ORIENTED_EDGE('',*,*,#713,.T.);
#715=DIRECTION('',(1.,0.,0.));
#716=VECTOR('',#715,1.);
#717=CARTESIAN_POINT('',(4.00000000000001,17.4999999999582,36.4234468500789));
#718=LINE('',#717,#716);
#719=EDGE_CURVE('E1443',#712,#694,#718,.T.);
#720=ORIENTED_EDGE('',*,*,#719,.T.);
#721=EDGE_LOOP('',(#698,#706,#714,#720));
#722=FACE_BOUND('',#721,.T.);
#723=DIRECTION('',(0.,0.,-1.));
#724=VECTOR('',#723,1.);
#725=CARTESIAN_POINT('',(-2.57655314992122,17.4999999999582,36.0000000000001));
#726=LINE('',#725,#724);
#727=CARTESIAN_POINT('',(-2.57655314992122,17.4999999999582,37.4234468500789));
#728=VERTEX_POINT('',#727);
#729=CARTESIAN_POINT('',(-2.57655314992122,17.4999999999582,24.5765531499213));
#730=VERTEX_POINT('',#729);
#731=EDGE_CURVE('E1426',#728,#730,#726,.T.);
#732=ORIENTED_EDGE('',*,*,#731,.T.);
#733=DIRECTION('',(-1.,0.,0.));
#734=VECTOR('',#733,1.);
#735=CARTESIAN_POINT('',(-4.,17.4999999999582,24.5765531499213));
#736=LINE('',#735,#734);
#737=CARTESIAN_POINT('',(-9.42344685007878,17.4999999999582,24.5765531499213));
#738=VERTEX_POINT('',#737);
#739=EDGE_CURVE('E1429',#730,#738,#736,.T.);
#740=ORIENTED_EDGE('',*,*,#739,.T.);
#741=DIRECTION('',(0.,0.,1.));
#742=VECTOR('',#741,1.);
#743=CARTESIAN_POINT('',(-9.42344685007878,17.4999999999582,26.0000000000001));
#744=LINE('',#743,#742);
#745=CARTESIAN_POINT('',(-9.42344685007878,17.4999999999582,37.4234468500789));
#746=VERTEX_POINT('',#745);
#747=EDGE_CURVE('E1433',#738,#746,#744,.T.);
#748=ORIENTED_EDGE('',*,*,#747,.T.);
#749=DIRECTION('',(1.,0.,0.));
#750=VECTOR('',#749,1.);
#751=CARTESIAN_POINT('',(-8.,17.4999999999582,37.4234468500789));
#752=LINE('',#751,#750);
#753=EDGE_CURVE('E1430',#746,#728,#752,.T.);
#754=ORIENTED_EDGE('',*,*,#753,.T.);
#755=EDGE_LOOP('',(#732,#740,#748,#754));
#756=FACE_BOUND('',#755,.T.);
#757=ADVANCED_FACE('F1858',(#672,#688,#722,#756),#257,.T.);
#758=CARTESIAN_POINT('',(27.6331455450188,7.,130.));
#759=DIRECTION('',(-0.998629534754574,-0.0523359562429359,0.));
#760=DIRECTION('',(0.052335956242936,-0.998629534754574,0.));
#761=AXIS2_PLACEMENT_3D('',#758,#759,#760);
#762=PLANE('',#761);
#763=DIRECTION('',(0.,0.,-1.));
#764=VECTOR('',#763,1.);
#765=CARTESIAN_POINT('',(28.,0.,130.));
#766=LINE('',#765,#764);
#767=CARTESIAN_POINT('',(28.,0.,116.));
#768=VERTEX_POINT('',#767);
#769=CARTESIAN_POINT('',(28.,0.,14.0000000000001));
#770=VERTEX_POINT('',#769);
#771=EDGE_CURVE('E1065',#768,#770,#766,.T.);
#772=ORIENTED_EDGE('',*,*,#771,.T.);
#773=DIRECTION('',(-0.052335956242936,0.998629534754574,0.));
#774=VECTOR('',#773,1.);
#775=CARTESIAN_POINT('',(27.6331455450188,7.,14.0000000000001));
#776=LINE('',#775,#774);
#777=CARTESIAN_POINT('',(27.6331455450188,7.,14.0000000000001));
#778=VERTEX_POINT('',#777);
#779=EDGE_CURVE('E1126',#770,#778,#776,.T.);
#780=ORIENTED_EDGE('',*,*,#779,.T.);
#781=DIRECTION('',(0.,0.,-1.));
#782=VECTOR('',#781,1.);
#783=CARTESIAN_POINT('',(27.6331455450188,7.,130.));
#784=LINE('',#783,#782);
#785=CARTESIAN_POINT('',(27.6331455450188,7.,116.));
#786=VERTEX_POINT('',#785);
#787=EDGE_CURVE('E1079',#786,#778,#784,.T.);
#788=ORIENTED_EDGE('',*,*,#787,.F.);
#789=DIRECTION('',(0.052335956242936,-0.998629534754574,0.));
#790=VECTOR('',#789,1.);
#791=CARTESIAN_POINT('',(28.,0.,116.));
#792=LINE('',#791,#790);
#793=EDGE_CURVE('E1083',#786,#768,#792,.T.);
#794=ORIENTED_EDGE('',*,*,#793,.T.);
#795=EDGE_LOOP('',(#772,#780,#788,#794));
#796=FACE_BOUND('',#795,.T.);
#797=ADVANCED_FACE('F2152',(#796),#762,.F.);
#798=CARTESIAN_POINT('',(17.5,21.,130.));
#799=DIRECTION('',(-0.810073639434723,-0.586328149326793,0.));
#800=DIRECTION('',(0.586328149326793,-0.810073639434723,0.));
#801=AXIS2_PLACEMENT_3D('',#798,#799,#800);
#802=PLANE('',#801);
#803=DIRECTION('',(-0.586328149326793,0.810073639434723,0.));
#804=VECTOR('',#803,1.);
#805=CARTESIAN_POINT('',(17.5,21.,14.0000000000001));
#806=LINE('',#805,#804);
#807=CARTESIAN_POINT('',(17.5,21.,14.0000000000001));
#808=VERTEX_POINT('',#807);
#809=EDGE_CURVE('E1123',#778,#808,#806,.T.);
#810=ORIENTED_EDGE('',*,*,#809,.T.);
#811=DIRECTION('',(0.,0.,-1.));
#812=VECTOR('',#811,1.);
#813=CARTESIAN_POINT('',(17.5,21.,130.));
#814=LINE('',#813,#812);
#815=CARTESIAN_POINT('',(17.5,21.,116.));
#816=VERTEX_POINT('',#815);
#817=EDGE_CURVE('E1077',#816,#808,#814,.T.);
#818=ORIENTED_EDGE('',*,*,#817,.F.);
#819=DIRECTION('',(0.586328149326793,-0.810073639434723,0.));
#820=VECTOR('',#819,1.);
#821=CARTESIAN_POINT('',(27.6331455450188,7.,116.));
#822=LINE('',#821,#820);
#823=EDGE_CURVE('E1091',#816,#786,#822,.T.);
#824=ORIENTED_EDGE('',*,*,#823,.T.);
#825=ORIENTED_EDGE('',*,*,#787,.T.);
#826=EDGE_LOOP('',(#810,#818,#824,#825));
#827=FACE_BOUND('',#826,.T.);
#828=ADVANCED_FACE('F2091',(#827),#802,.F.);
#829=CARTESIAN_POINT('',(-17.5,21.,130.));
#830=DIRECTION('',(0.,-1.,0.));
#831=DIRECTION('',(0.,0.,-1.));
#832=AXIS2_PLACEMENT_3D('',#829,#830,#831);
#833=PLANE('',#832);
#834=DIRECTION('',(0.,0.,1.));
#835=VECTOR('',#834,1.);
#836=CARTESIAN_POINT('',(-12.5,20.9999999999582,19.0000000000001));
#837=LINE('',#836,#835);
#838=CARTESIAN_POINT('',(-12.5,20.9999999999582,19.0000000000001));
#839=VERTEX_POINT('',#838);
#840=CARTESIAN_POINT('',(-12.5,20.9999999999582,94.0000000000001));
#841=VERTEX_POINT('',#840);
#842=EDGE_CURVE('E1019',#839,#841,#837,.T.);
#843=ORIENTED_EDGE('',*,*,#842,.F.);
#844=DIRECTION('',(-1.,0.,0.));
#845=VECTOR('',#844,1.);
#846=CARTESIAN_POINT('',(12.5,20.9999999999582,19.0000000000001));
#847=LINE('',#846,#845);
#848=CARTESIAN_POINT('',(12.5,21.,18.9999999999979));
#849=VERTEX_POINT('',#848);
#850=EDGE_CURVE('E1017',#849,#839,#847,.T.);
#851=ORIENTED_EDGE('',*,*,#850,.F.);
#852=DIRECTION('',(0.,0.,-1.));
#853=VECTOR('',#852,1.);
#854=CARTESIAN_POINT('',(12.5,20.9999999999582,19.0000000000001));
#855=LINE('',#854,#853);
#856=CARTESIAN_POINT('',(12.5,20.9999999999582,94.0000000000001));
#857=VERTEX_POINT('',#856);
#858=EDGE_CURVE('E1001',#857,#849,#855,.T.);
#859=ORIENTED_EDGE('',*,*,#858,.F.);
#860=DIRECTION('',(1.,0.,0.));
#861=VECTOR('',#860,1.);
#862=CARTESIAN_POINT('',(12.5,20.9999999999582,94.0000000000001));
#863=LINE('',#862,#861);
#864=EDGE_CURVE('E1021',#841,#857,#863,.T.);
#865=ORIENTED_EDGE('',*,*,#864,.F.);
#866=EDGE_LOOP('',(#843,#851,#859,#865));
#867=FACE_BOUND('',#866,.T.);
#868=DIRECTION('',(0.,0.,1.));
#869=VECTOR('',#868,1.);
#870=CARTESIAN_POINT('',(-9.,20.9999999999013,111.));
#871=LINE('',#870,#869);
#872=CARTESIAN_POINT('',(-9.,20.9999999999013,103.));
#873=VERTEX_POINT('',#872);
#874=CARTESIAN_POINT('',(-9.,21.,111.000000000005));
#875=VERTEX_POINT('',#874);
#876=EDGE_CURVE('E818',#873,#875,#871,.T.);
#877=ORIENTED_EDGE('',*,*,#876,.F.);
#878=DIRECTION('',(-1.,0.,0.));
#879=VECTOR('',#878,1.);
#880=CARTESIAN_POINT('',(-9.,20.9999999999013,103.));
#881=LINE('',#880,#879);
#882=CARTESIAN_POINT('',(9.,20.9999999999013,103.));
#883=VERTEX_POINT('',#882);
#884=EDGE_CURVE('E826',#883,#873,#881,.T.);
#885=ORIENTED_EDGE('',*,*,#884,.F.);
#886=DIRECTION('',(0.,0.,-1.));
#887=VECTOR('',#886,1.);
#888=CARTESIAN_POINT('',(9.,20.9999999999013,111.));
#889=LINE('',#888,#887);
#890=CARTESIAN_POINT('',(9.,20.9999999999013,111.));
#891=VERTEX_POINT('',#890);
#892=EDGE_CURVE('E823',#891,#883,#889,.T.);
#893=ORIENTED_EDGE('',*,*,#892,.F.);
#894=DIRECTION('',(1.,0.,0.));
#895=VECTOR('',#894,1.);
#896=CARTESIAN_POINT('',(-9.,20.9999999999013,111.));
#897=LINE('',#896,#895);
#898=EDGE_CURVE('E820',#875,#891,#897,.T.);
#899=ORIENTED_EDGE('',*,*,#898,.F.);
#900=EDGE_LOOP('',(#877,#885,#893,#899));
#901=FACE_BOUND('',#900,.T.);
#902=DIRECTION('',(-1.,0.,0.));
#903=VECTOR('',#902,1.);
#904=CARTESIAN_POINT('',(-17.5,21.,14.0000000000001));
#905=LINE('',#904,#903);
#906=CARTESIAN_POINT('',(-17.5,21.,14.0000000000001));
#907=VERTEX_POINT('',#906);
#908=EDGE_CURVE('E1120',#808,#907,#905,.T.);
#909=ORIENTED_EDGE('',*,*,#908,.T.);
#910=DIRECTION('',(0.,0.,-1.));
#911=VECTOR('',#910,1.);
#912=CARTESIAN_POINT('',(-17.5,21.,130.));
#913=LINE('',#912,#911);
#914=CARTESIAN_POINT('',(-17.5,21.,116.));
#915=VERTEX_POINT('',#914);
#916=EDGE_CURVE('E1074',#915,#907,#913,.T.);
#917=ORIENTED_EDGE('',*,*,#916,.F.);
#918=DIRECTION('',(1.,0.,0.));
#919=VECTOR('',#918,1.);
#920=CARTESIAN_POINT('',(17.5,21.,116.));
#921=LINE('',#920,#919);
#922=EDGE_CURVE('E1093',#915,#816,#921,.T.);
#923=ORIENTED_EDGE('',*,*,#922,.T.);
#924=ORIENTED_EDGE('',*,*,#817,.T.);
#925=EDGE_LOOP('',(#909,#917,#923,#924));
#926=FACE_BOUND('',#925,.T.);
#927=ADVANCED_FACE('F2087',(#867,#901,#926),#833,.F.);
#928=CARTESIAN_POINT('',(-27.6331455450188,7.,130.));
#929=DIRECTION('',(0.810073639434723,-0.586328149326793,0.));
#930=DIRECTION('',(0.586328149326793,0.810073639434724,0.));
#931=AXIS2_PLACEMENT_3D('',#928,#929,#930);
#932=PLANE('',#931);
#933=ORIENTED_EDGE('',*,*,#916,.T.);
#934=DIRECTION('',(-0.586328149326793,-0.810073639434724,0.));
#935=VECTOR('',#934,1.);
#936=CARTESIAN_POINT('',(-27.6331455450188,7.,14.0000000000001));
#937=LINE('',#936,#935);
#938=CARTESIAN_POINT('',(-27.6331455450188,7.,14.0000000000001));
#939=VERTEX_POINT('',#938);
#940=EDGE_CURVE('E1118',#907,#939,#937,.T.);
#941=ORIENTED_EDGE('',*,*,#940,.T.);
#942=DIRECTION('',(0.,0.,-1.));
#943=VECTOR('',#942,1.);
#944=CARTESIAN_POINT('',(-27.6331455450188,7.,130.));
#945=LINE('',#944,#943);
#946=CARTESIAN_POINT('',(-27.6331455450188,7.,116.));
#947=VERTEX_POINT('',#946);
#948=EDGE_CURVE('E1071',#947,#939,#945,.T.);
#949=ORIENTED_EDGE('',*,*,#948,.F.);
#950=DIRECTION('',(0.586328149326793,0.810073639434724,0.));
#951=VECTOR('',#950,1.);
#952=CARTESIAN_POINT('',(-17.5,21.,116.));
#953=LINE('',#952,#951);
#954=EDGE_CURVE('E1095',#947,#915,#953,.T.);
#955=ORIENTED_EDGE('',*,*,#954,.T.);
#956=EDGE_LOOP('',(#933,#941,#949,#955));
#957=FACE_BOUND('',#956,.T.);
#958=ADVANCED_FACE('F2090',(#957),#932,.F.);
#959=CARTESIAN_POINT('',(-27.6331455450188,7.,130.));
#960=DIRECTION('',(0.998629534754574,-0.0523359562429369,0.));
#961=DIRECTION('',(0.0523359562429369,0.998629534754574,0.));
#962=AXIS2_PLACEMENT_3D('',#959,#960,#961);
#963=PLANE('',#962);
#964=ORIENTED_EDGE('',*,*,#948,.T.);
#965=DIRECTION('',(-0.0523359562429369,-0.998629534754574,0.));
#966=VECTOR('',#965,1.);
#967=CARTESIAN_POINT('',(-27.6331455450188,7.,14.0000000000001));
#968=LINE('',#967,#966);
#969=CARTESIAN_POINT('',(-28.,0.,14.0000000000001));
#970=VERTEX_POINT('',#969);
#971=EDGE_CURVE('E1099',#939,#970,#968,.T.);
#972=ORIENTED_EDGE('',*,*,#971,.T.);
#973=DIRECTION('',(0.,0.,-1.));
#974=VECTOR('',#973,1.);
#975=CARTESIAN_POINT('',(-28.,0.,130.));
#976=LINE('',#975,#974);
#977=CARTESIAN_POINT('',(-28.,0.,116.));
#978=VERTEX_POINT('',#977);
#979=EDGE_CURVE('E1068',#978,#970,#976,.T.);
#980=ORIENTED_EDGE('',*,*,#979,.F.);
#981=DIRECTION('',(0.0523359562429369,0.998629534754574,0.));
#982=VECTOR('',#981,1.);
#983=CARTESIAN_POINT('',(-27.6331455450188,7.,116.));
#984=LINE('',#983,#982);
#985=EDGE_CURVE('E1097',#978,#947,#984,.T.);
#986=ORIENTED_EDGE('',*,*,#985,.T.);
#987=EDGE_LOOP('',(#964,#972,#980,#986));
#988=FACE_BOUND('',#987,.T.);
#989=ADVANCED_FACE('F2116',(#988),#963,.F.);
#990=CARTESIAN_POINT('',(-28.,0.,130.));
#991=DIRECTION('',(0.,1.,0.));
#992=DIRECTION('',(0.,0.,1.));
#993=AXIS2_PLACEMENT_3D('',#990,#991,#992);
#994=PLANE('',#993);
#995=DIRECTION('',(1.,0.,0.));
#996=VECTOR('',#995,1.);
#997=CARTESIAN_POINT('',(3.88969505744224,0.,132.999999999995));
#998=LINE('',#997,#996);
#999=CARTESIAN_POINT('',(10.6082464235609,0.,132.999999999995));
#1000=VERTEX_POINT('',#999);
#1001=CARTESIAN_POINT('',(12.1103049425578,0.,132.999999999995));
#1002=VERTEX_POINT('',#1001);
#1003=EDGE_CURVE('E1048',#1000,#1002,#998,.T.);
#1004=ORIENTED_EDGE('',*,*,#1003,.F.);
#1005=DIRECTION('',(0.,0.,-1.));
#1006=VECTOR('',#1005,1.);
#1007=CARTESIAN_POINT('',(10.6082464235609,0.,132.999999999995));
#1008=LINE('',#1007,#1006);
#1009=CARTESIAN_POINT('',(10.6082464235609,0.,128.499085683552));
#1010=VERTEX_POINT('',#1009);
#1011=EDGE_CURVE('E1326',#1000,#1010,#1008,.T.);
#1012=ORIENTED_EDGE('',*,*,#1011,.T.);
#1013=DIRECTION('',(1.,0.,0.));
#1014=VECTOR('',#1013,1.);
#1015=CARTESIAN_POINT('',(-28.,0.,128.499085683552));
#1016=LINE('',#1015,#1014);
#1017=CARTESIAN_POINT('',(17.2139443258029,0.,128.499085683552));
#1018=VERTEX_POINT('',#1017);
#1019=EDGE_CURVE('E1524',#1010,#1018,#1016,.T.);
#1020=ORIENTED_EDGE('',*,*,#1019,.T.);
#1021=DIRECTION('',(-0.581766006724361,0.,0.813356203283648));
#1022=VECTOR('',#1021,1.);
#1023=CARTESIAN_POINT('',(16.7744174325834,0.,129.113580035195));
#1024=LINE('',#1023,#1022);
#1025=CARTESIAN_POINT('',(26.4979414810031,0.,115.519302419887));
#1026=VERTEX_POINT('',#1025);
#1027=EDGE_CURVE('E1521',#1026,#1018,#1024,.T.);
#1028=ORIENTED_EDGE('',*,*,#1027,.F.);
#1029=DIRECTION('',(0.,0.,-1.));
#1030=VECTOR('',#1029,1.);
#1031=CARTESIAN_POINT('',(26.4979414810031,0.,130.));
#1032=LINE('',#1031,#1030);
#1033=CARTESIAN_POINT('',(26.4979414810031,0.,14.4806975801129));
#1034=VERTEX_POINT('',#1033);
#1035=EDGE_CURVE('E1271',#1026,#1034,#1032,.T.);
#1036=ORIENTED_EDGE('',*,*,#1035,.T.);
#1037=DIRECTION('',(-0.581766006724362,0.,-0.813356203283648));
#1038=VECTOR('',#1037,1.);
#1039=CARTESIAN_POINT('',(26.654695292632,0.,14.699852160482));
#1040=LINE('',#1039,#1038);
#1041=CARTESIAN_POINT('',(17.2139443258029,0.,1.50091431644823));
#1042=VERTEX_POINT('',#1041);
#1043=EDGE_CURVE('E1282',#1042,#1034,#1040,.F.);
#1044=ORIENTED_EDGE('',*,*,#1043,.F.);
#1045=DIRECTION('',(-1.,0.,0.));
#1046=VECTOR('',#1045,1.);
#1047=CARTESIAN_POINT('',(-28.,0.,1.50091431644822));
#1048=LINE('',#1047,#1046);
#1049=CARTESIAN_POINT('',(-17.2139443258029,0.,1.50091431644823));
#1050=VERTEX_POINT('',#1049);
#1051=EDGE_CURVE('E1289',#1050,#1042,#1048,.F.);
#1052=ORIENTED_EDGE('',*,*,#1051,.F.);
#1053=DIRECTION('',(-0.581766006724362,0.,0.813356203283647));
#1054=VECTOR('',#1053,1.);
#1055=CARTESIAN_POINT('',(-26.654695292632,0.,14.699852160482));
#1056=LINE('',#1055,#1054);
#1057=CARTESIAN_POINT('',(-26.4979414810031,0.,14.4806975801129));
#1058=VERTEX_POINT('',#1057);
#1059=EDGE_CURVE('E1344',#1058,#1050,#1056,.F.);
#1060=ORIENTED_EDGE('',*,*,#1059,.F.);
#1061=DIRECTION('',(0.,0.,-1.));
#1062=VECTOR('',#1061,1.);
#1063=CARTESIAN_POINT('',(-26.4979414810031,0.,130.));
#1064=LINE('',#1063,#1062);
#1065=CARTESIAN_POINT('',(-26.4979414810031,0.,115.519302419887));
#1066=VERTEX_POINT('',#1065);
#1067=EDGE_CURVE('E1264',#1066,#1058,#1064,.T.);
#1068=ORIENTED_EDGE('',*,*,#1067,.F.);
#1069=DIRECTION('',(-0.581766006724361,0.,-0.813356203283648));
#1070=VECTOR('',#1069,1.);
#1071=CARTESIAN_POINT('',(-16.7225033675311,0.,129.186160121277));
#1072=LINE('',#1071,#1070);
#1073=CARTESIAN_POINT('',(-17.2139443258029,0.,128.499085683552));
#1074=VERTEX_POINT('',#1073);
#1075=EDGE_CURVE('E1523',#1074,#1066,#1072,.T.);
#1076=ORIENTED_EDGE('',*,*,#1075,.F.);
#1077=DIRECTION('',(1.,0.,0.));
#1078=VECTOR('',#1077,1.);
#1079=CARTESIAN_POINT('',(-28.,0.,128.499085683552));
#1080=LINE('',#1079,#1078);
#1081=CARTESIAN_POINT('',(5.39175357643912,0.,128.499085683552));
#1082=VERTEX_POINT('',#1081);
#1083=EDGE_CURVE('E1520',#1074,#1082,#1080,.T.);
#1084=ORIENTED_EDGE('',*,*,#1083,.T.);
#1085=DIRECTION('',(0.,0.,-1.));
#1086=VECTOR('',#1085,1.);
#1087=CARTESIAN_POINT('',(5.39175357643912,0.,130.));
#1088=LINE('',#1087,#1086);
#1089=CARTESIAN_POINT('',(5.39175357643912,0.,132.999999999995));
#1090=VERTEX_POINT('',#1089);
#1091=EDGE_CURVE('E1322',#1090,#1082,#1088,.T.);
#1092=ORIENTED_EDGE('',*,*,#1091,.F.);
#1093=CARTESIAN_POINT('',(3.88969505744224,0.,132.999999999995));
#1094=VERTEX_POINT('',#1093);
#1095=EDGE_CURVE('E1044',#1094,#1090,#998,.T.);
#1096=ORIENTED_EDGE('',*,*,#1095,.F.);
#1097=DIRECTION('',(0.,0.,-1.));
#1098=VECTOR('',#1097,1.);
#1099=CARTESIAN_POINT('',(3.88969505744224,0.,132.999999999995));
#1100=LINE('',#1099,#1098);
#1101=CARTESIAN_POINT('',(3.88969505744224,0.,130.));
#1102=VERTEX_POINT('',#1101);
#1103=EDGE_CURVE('E1057',#1094,#1102,#1100,.T.);
#1104=ORIENTED_EDGE('',*,*,#1103,.T.);
#1105=DIRECTION('',(1.,0.,0.));
#1106=VECTOR('',#1105,1.);
#1107=CARTESIAN_POINT('',(-28.,0.,130.));
#1108=LINE('',#1107,#1106);
#1109=CARTESIAN_POINT('',(-17.9862765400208,0.,130.));
#1110=VERTEX_POINT('',#1109);
#1111=EDGE_CURVE('E1060',#1110,#1102,#1108,.T.);
#1112=ORIENTED_EDGE('',*,*,#1111,.F.);
#1113=DIRECTION('',(-0.581766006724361,0.,-0.813356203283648));
#1114=VECTOR('',#1113,1.);
#1115=CARTESIAN_POINT('',(-17.9436455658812,0.,130.05960156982));
#1116=LINE('',#1115,#1114);
#1117=EDGE_CURVE('E1085',#1110,#978,#1116,.T.);
#1118=ORIENTED_EDGE('',*,*,#1117,.T.);
#1119=ORIENTED_EDGE('',*,*,#979,.T.);
#1120=DIRECTION('',(-0.581766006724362,0.,0.813356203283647));
#1121=VECTOR('',#1120,1.);
#1122=CARTESIAN_POINT('',(-27.8758374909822,0.,13.8264107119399));
#1123=LINE('',#1122,#1121);
#1124=CARTESIAN_POINT('',(-17.9862765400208,0.,0.));
#1125=VERTEX_POINT('',#1124);
#1126=EDGE_CURVE('E1115',#970,#1125,#1123,.F.);
#1127=ORIENTED_EDGE('',*,*,#1126,.T.);
#1128=DIRECTION('',(1.,0.,0.));
#1129=VECTOR('',#1128,1.);
#1130=CARTESIAN_POINT('',(-28.,0.,0.));
#1131=LINE('',#1130,#1129);
#1132=CARTESIAN_POINT('',(17.9862765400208,0.,0.));
#1133=VERTEX_POINT('',#1132);
#1134=EDGE_CURVE('E1061',#1125,#1133,#1131,.T.);
#1135=ORIENTED_EDGE('',*,*,#1134,.T.);
#1136=DIRECTION('',(-0.581766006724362,0.,-0.813356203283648));
#1137=VECTOR('',#1136,1.);
#1138=CARTESIAN_POINT('',(27.8758374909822,0.,13.8264107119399));
#1139=LINE('',#1138,#1137);
#1140=EDGE_CURVE('E1113',#1133,#770,#1139,.F.);
#1141=ORIENTED_EDGE('',*,*,#1140,.T.);
#1142=ORIENTED_EDGE('',*,*,#771,.F.);
#1143=DIRECTION('',(-0.581766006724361,0.,0.813356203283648));
#1144=VECTOR('',#1143,1.);
#1145=CARTESIAN_POINT('',(17.9955596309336,0.,129.987021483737));
#1146=LINE('',#1145,#1144);
#1147=CARTESIAN_POINT('',(17.9862765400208,0.,130.));
#1148=VERTEX_POINT('',#1147);
#1149=EDGE_CURVE('E1088',#768,#1148,#1146,.T.);
#1150=ORIENTED_EDGE('',*,*,#1149,.T.);
#1151=DIRECTION('',(1.,0.,0.));
#1152=VECTOR('',#1151,1.);
#1153=CARTESIAN_POINT('',(-28.,0.,130.));
#1154=LINE('',#1153,#1152);
#1155=CARTESIAN_POINT('',(12.1103049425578,0.,130.));
#1156=VERTEX_POINT('',#1155);
#1157=EDGE_CURVE('E1058',#1156,#1148,#1154,.T.);
#1158=ORIENTED_EDGE('',*,*,#1157,.F.);
#1159=DIRECTION('',(0.,0.,-1.));
#1160=VECTOR('',#1159,1.);
#1161=CARTESIAN_POINT('',(12.1103049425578,0.,132.999999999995));
#1162=LINE('',#1161,#1160);
#1163=EDGE_CURVE('E1052',#1002,#1156,#1162,.T.);
#1164=ORIENTED_EDGE('',*,*,#1163,.F.);
#1165=EDGE_LOOP('',(#1004,#1012,#1020,#1028,#1036,#1044,#1052,#1060,#1068,#1076,#1084,#1092,
#1096,#1104,#1112,#1118,#1119,#1127,#1135,#1141,#1142,#1150,#1158,#1164));
#1166=FACE_BOUND('',#1165,.T.);
#1167=ADVANCED_FACE('F2015',(#1166),#994,.F.);
#1168=CARTESIAN_POINT('',(-28.,0.,130.));
#1169=DIRECTION('',(0.,0.034899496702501,0.999390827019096));
#1170=DIRECTION('',(0.,-0.999390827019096,0.034899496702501));
#1171=AXIS2_PLACEMENT_3D('',#1168,#1169,#1170);
#1172=PLANE('',#1171);
#1173=DIRECTION('',(-0.0523041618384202,0.998022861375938,-0.0348517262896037));
#1174=VECTOR('',#1173,1.);
#1175=CARTESIAN_POINT('',(12.1157736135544,-0.104348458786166,130.003643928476));
#1176=LINE('',#1175,#1174);
#1177=CARTESIAN_POINT('',(11.9945181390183,2.20934382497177,129.92284801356));
#1178=VERTEX_POINT('',#1177);
#1179=EDGE_CURVE('E1151',#1156,#1178,#1176,.T.);
#1180=ORIENTED_EDGE('',*,*,#1179,.F.);
#1181=ORIENTED_EDGE('',*,*,#1157,.T.);
#1182=DIRECTION('',(-0.0274031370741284,0.999015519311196,-0.034886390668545));
#1183=VECTOR('',#1182,1.);
#1184=CARTESIAN_POINT('',(17.9517439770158,1.25892762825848,129.956037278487));
#1185=LINE('',#1184,#1183);
#1186=CARTESIAN_POINT('',(17.8886483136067,3.55915868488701,129.875711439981));
#1187=VERTEX_POINT('',#1186);
#1188=EDGE_CURVE('E1086',#1148,#1187,#1185,.T.);
#1189=ORIENTED_EDGE('',*,*,#1188,.T.);
#1190=DIRECTION('',(-0.569362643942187,0.821585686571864,-0.0286904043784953));
#1191=VECTOR('',#1190,1.);
#1192=CARTESIAN_POINT('',(4.67968412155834,22.6195870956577,129.210106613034));
#1193=LINE('',#1192,#1191);
#1194=CARTESIAN_POINT('',(12.537102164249,11.2813964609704,129.606044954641));
#1195=VERTEX_POINT('',#1194);
#1196=EDGE_CURVE('E1166',#1187,#1195,#1193,.T.);
#1197=ORIENTED_EDGE('',*,*,#1196,.T.);
#1198=DIRECTION('',(-1.,0.,0.));
#1199=VECTOR('',#1198,1.);
#1200=CARTESIAN_POINT('',(-28.,11.2813964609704,129.606044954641));
#1201=LINE('',#1200,#1199);
#1202=CARTESIAN_POINT('',(-12.537102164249,11.2813964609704,129.606044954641));
#1203=VERTEX_POINT('',#1202);
#1204=EDGE_CURVE('E1164',#1195,#1203,#1201,.T.);
#1205=ORIENTED_EDGE('',*,*,#1204,.T.);
#1206=DIRECTION('',(-0.569362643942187,-0.821585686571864,0.0286904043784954));
#1207=VECTOR('',#1206,1.);
#1208=CARTESIAN_POINT('',(-22.8334180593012,-3.57610403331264,130.124880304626));
#1209=LINE('',#1208,#1207);
#1210=CARTESIAN_POINT('',(-17.8886483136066,3.55915868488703,129.875711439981));
#1211=VERTEX_POINT('',#1210);
#1212=EDGE_CURVE('E1162',#1203,#1211,#1209,.T.);
#1213=ORIENTED_EDGE('',*,*,#1212,.T.);
#1214=DIRECTION('',(-0.0274031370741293,-0.999015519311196,0.034886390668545));
#1215=VECTOR('',#1214,1.);
#1216=CARTESIAN_POINT('',(-17.99379616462,-0.274137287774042,130.009573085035));
#1217=LINE('',#1216,#1215);
#1218=EDGE_CURVE('E1082',#1211,#1110,#1217,.T.);
#1219=ORIENTED_EDGE('',*,*,#1218,.T.);
#1220=ORIENTED_EDGE('',*,*,#1111,.T.);
#1221=DIRECTION('',(-0.0523041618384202,-0.998022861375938,0.0348517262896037));
#1222=VECTOR('',#1221,1.);
#1223=CARTESIAN_POINT('',(3.88422638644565,-0.104348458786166,130.003643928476));
#1224=LINE('',#1223,#1222);
#1225=CARTESIAN_POINT('',(4.00548186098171,2.20934382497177,129.92284801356));
#1226=VERTEX_POINT('',#1225);
#1227=EDGE_CURVE('E1155',#1226,#1102,#1224,.T.);
#1228=ORIENTED_EDGE('',*,*,#1227,.F.);
#1229=CARTESIAN_POINT('',(8.,2.,129.930158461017));
#1230=DIRECTION('',(0.,0.034899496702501,0.999390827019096));
#1231=DIRECTION('',(0.,0.999390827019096,-0.034899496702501));
#1232=AXIS2_PLACEMENT_3D('',#1229,#1230,#1231);
#1233=ELLIPSE('',#1232,4.00243817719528,3.99999999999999);
#1234=EDGE_CURVE('E1027',#1178,#1226,#1233,.T.);
#1235=ORIENTED_EDGE('',*,*,#1234,.F.);
#1236=EDGE_LOOP('',(#1180,#1181,#1189,#1197,#1205,#1213,#1219,#1220,#1228,#1235));
#1237=FACE_BOUND('',#1236,.T.);
#1238=ADVANCED_FACE('F2162',(#1237),#1172,.T.);
#1239=CARTESIAN_POINT('',(-28.,0.,0.));
#1240=DIRECTION('',(0.,0.034899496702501,-0.999390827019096));
#1241=DIRECTION('',(0.,0.999390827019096,0.034899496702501));
#1242=AXIS2_PLACEMENT_3D('',#1239,#1240,#1241);
#1243=PLANE('',#1242);
#1244=ORIENTED_EDGE('',*,*,#1134,.F.);
#1245=DIRECTION('',(0.0274031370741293,0.999015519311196,0.034886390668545));
#1246=VECTOR('',#1245,1.);
#1247=CARTESIAN_POINT('',(-17.7885036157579,7.21005847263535,0.251780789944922));
#1248=LINE('',#1247,#1246);
#1249=CARTESIAN_POINT('',(-17.8886483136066,3.55915868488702,0.124288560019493));
#1250=VERTEX_POINT('',#1249);
#1251=EDGE_CURVE('E1121',#1125,#1250,#1248,.T.);
#1252=ORIENTED_EDGE('',*,*,#1251,.T.);
#1253=DIRECTION('',(0.569362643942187,0.821585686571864,0.0286904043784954));
#1254=VECTOR('',#1253,1.);
#1255=CARTESIAN_POINT('',(-19.2113386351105,1.65052725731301,0.057637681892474));
#1256=LINE('',#1255,#1254);
#1257=CARTESIAN_POINT('',(-12.5371021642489,11.2813964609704,0.393955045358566));
#1258=VERTEX_POINT('',#1257);
#1259=EDGE_CURVE('E1148',#1250,#1258,#1256,.T.);
#1260=ORIENTED_EDGE('',*,*,#1259,.T.);
#1261=DIRECTION('',(1.,0.,0.));
#1262=VECTOR('',#1261,1.);
#1263=CARTESIAN_POINT('',(-17.5,11.2813964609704,0.393955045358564));
#1264=LINE('',#1263,#1262);
#1265=CARTESIAN_POINT('',(12.537102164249,11.2813964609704,0.393955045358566));
#1266=VERTEX_POINT('',#1265);
#1267=EDGE_CURVE('E1146',#1258,#1266,#1264,.T.);
#1268=ORIENTED_EDGE('',*,*,#1267,.T.);
#1269=DIRECTION('',(0.569362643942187,-0.821585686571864,-0.0286904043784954));
#1270=VECTOR('',#1269,1.);
#1271=CARTESIAN_POINT('',(9.37751534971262,15.8406546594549,0.553167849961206));
#1272=LINE('',#1271,#1270);
#1273=CARTESIAN_POINT('',(17.8886483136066,3.55915868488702,0.124288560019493));
#1274=VERTEX_POINT('',#1273);
#1275=EDGE_CURVE('E1144',#1266,#1274,#1272,.T.);
#1276=ORIENTED_EDGE('',*,*,#1275,.T.);
#1277=DIRECTION('',(0.0274031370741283,-0.999015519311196,-0.034886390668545));
#1278=VECTOR('',#1277,1.);
#1279=CARTESIAN_POINT('',(17.788503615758,7.21005847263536,0.251780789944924));
#1280=LINE('',#1279,#1278);
#1281=EDGE_CURVE('E1117',#1274,#1133,#1280,.T.);
#1282=ORIENTED_EDGE('',*,*,#1281,.T.);
#1283=EDGE_LOOP('',(#1244,#1252,#1260,#1268,#1276,#1282));
#1284=FACE_BOUND('',#1283,.T.);
#1285=ADVANCED_FACE('F2144',(#1284),#1243,.T.);
#1286=CARTESIAN_POINT('',(-17.8603177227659,2.40343740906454,130.));
#1287=DIRECTION('',(-0.812618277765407,0.0425875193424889,0.581238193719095));
#1288=DIRECTION('',(0.581766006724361,0.,0.813356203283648));
#1289=AXIS2_PLACEMENT_3D('',#1286,#1287,#1288);
#1290=PLANE('',#1289);
#1291=ORIENTED_EDGE('',*,*,#1117,.F.);
#1292=ORIENTED_EDGE('',*,*,#1218,.F.);
#1293=DIRECTION('',(-0.563228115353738,0.198879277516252,-0.802010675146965));
#1294=VECTOR('',#1293,1.);
#1295=CARTESIAN_POINT('',(-17.6940606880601,3.49044860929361,130.15279518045));
#1296=LINE('',#1295,#1294);
#1297=EDGE_CURVE('E1064',#947,#1211,#1296,.F.);
#1298=ORIENTED_EDGE('',*,*,#1297,.F.);
#1299=ORIENTED_EDGE('',*,*,#985,.F.);
#1300=EDGE_LOOP('',(#1291,#1292,#1298,#1299));
#1301=FACE_BOUND('',#1300,.T.);
#1302=ADVANCED_FACE('F2123',(#1301),#1290,.T.);
#1303=CARTESIAN_POINT('',(-3.73159034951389,22.9672016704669,130.));
#1304=DIRECTION('',(-0.659184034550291,0.477114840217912,0.581238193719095));
#1305=DIRECTION('',(0.661369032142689,0.,0.750060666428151));
#1306=AXIS2_PLACEMENT_3D('',#1303,#1304,#1305);
#1307=PLANE('',#1306);
#1308=ORIENTED_EDGE('',*,*,#1297,.T.);
#1309=ORIENTED_EDGE('',*,*,#1212,.F.);
#1310=DIRECTION('',(-0.284545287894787,0.557211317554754,-0.780095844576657));
#1311=VECTOR('',#1310,1.);
#1312=CARTESIAN_POINT('',(-13.5895137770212,13.3422833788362,126.720803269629));
#1313=LINE('',#1312,#1311);
#1314=EDGE_CURVE('E1106',#915,#1203,#1313,.F.);
#1315=ORIENTED_EDGE('',*,*,#1314,.F.);
#1316=ORIENTED_EDGE('',*,*,#954,.F.);
#1317=EDGE_LOOP('',(#1308,#1309,#1315,#1316));
#1318=FACE_BOUND('',#1317,.T.);
#1319=ADVANCED_FACE('F2127',(#1318),#1307,.T.);
#1320=CARTESIAN_POINT('',(28.,11.,130.));
#1321=DIRECTION('',(0.,0.813733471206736,0.581238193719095));
#1322=DIRECTION('',(0.,-0.581238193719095,0.813733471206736));
#1323=AXIS2_PLACEMENT_3D('',#1320,#1321,#1322);
#1324=PLANE('',#1323);
#1325=DIRECTION('',(0.284545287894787,0.557211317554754,-0.780095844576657));
#1326=VECTOR('',#1325,1.);
#1327=CARTESIAN_POINT('',(13.657008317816,13.4744546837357,126.53576344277));
#1328=LINE('',#1327,#1326);
#1329=EDGE_CURVE('E1102',#816,#1195,#1328,.F.);
#1330=ORIENTED_EDGE('',*,*,#1329,.F.);
#1331=ORIENTED_EDGE('',*,*,#922,.F.);
#1332=ORIENTED_EDGE('',*,*,#1314,.T.);
#1333=ORIENTED_EDGE('',*,*,#1204,.F.);
#1334=EDGE_LOOP('',(#1330,#1331,#1332,#1333));
#1335=FACE_BOUND('',#1334,.T.);
#1336=ADVANCED_FACE('F2132',(#1335),#1324,.T.);
#1337=CARTESIAN_POINT('',(22.9833094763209,-3.63106108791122,130.));
#1338=DIRECTION('',(0.659184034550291,0.477114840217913,0.581238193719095));
#1339=DIRECTION('',(0.66136903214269,0.,-0.750060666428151));
#1340=AXIS2_PLACEMENT_3D('',#1337,#1338,#1339);
#1341=PLANE('',#1340);
#1342=ORIENTED_EDGE('',*,*,#1329,.T.);
#1343=ORIENTED_EDGE('',*,*,#1196,.F.);
#1344=DIRECTION('',(0.563228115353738,0.198879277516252,-0.802010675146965));
#1345=VECTOR('',#1344,1.);
#1346=CARTESIAN_POINT('',(18.6432556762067,3.82561514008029,128.801185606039));
#1347=LINE('',#1346,#1345);
#1348=EDGE_CURVE('E1100',#786,#1187,#1347,.F.);
#1349=ORIENTED_EDGE('',*,*,#1348,.F.);
#1350=ORIENTED_EDGE('',*,*,#823,.F.);
#1351=EDGE_LOOP('',(#1342,#1343,#1349,#1350));
#1352=FACE_BOUND('',#1351,.T.);
#1353=ADVANCED_FACE('F2160',(#1352),#1341,.T.);
#1354=CARTESIAN_POINT('',(18.0137046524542,-0.52335956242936,130.));
#1355=DIRECTION('',(0.812618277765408,0.0425875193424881,0.581238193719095));
#1356=DIRECTION('',(0.581766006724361,0.,-0.813356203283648));
#1357=AXIS2_PLACEMENT_3D('',#1354,#1355,#1356);
#1358=PLANE('',#1357);
#1359=ORIENTED_EDGE('',*,*,#1149,.F.);
#1360=ORIENTED_EDGE('',*,*,#793,.F.);
#1361=ORIENTED_EDGE('',*,*,#1348,.T.);
#1362=ORIENTED_EDGE('',*,*,#1188,.F.);
#1363=EDGE_LOOP('',(#1359,#1360,#1361,#1362));
#1364=FACE_BOUND('',#1363,.T.);
#1365=ADVANCED_FACE('F2156',(#1364),#1358,.T.);
#1366=CARTESIAN_POINT('',(27.6331455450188,7.,14.0000000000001));
#1367=DIRECTION('',(-0.812618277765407,-0.0425875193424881,0.581238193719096));
#1368=DIRECTION('',(0.581766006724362,0.,0.813356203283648));
#1369=AXIS2_PLACEMENT_3D('',#1366,#1367,#1368);
#1370=PLANE('',#1369);
#1371=ORIENTED_EDGE('',*,*,#1140,.F.);
#1372=ORIENTED_EDGE('',*,*,#1281,.F.);
#1373=DIRECTION('',(0.563228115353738,0.198879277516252,0.802010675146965));
#1374=VECTOR('',#1373,1.);
#1375=CARTESIAN_POINT('',(27.6331455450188,7.,14.0000000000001));
#1376=LINE('',#1375,#1374);
#1377=EDGE_CURVE('E1103',#778,#1274,#1376,.F.);
#1378=ORIENTED_EDGE('',*,*,#1377,.F.);
#1379=ORIENTED_EDGE('',*,*,#779,.F.);
#1380=EDGE_LOOP('',(#1371,#1372,#1378,#1379));
#1381=FACE_BOUND('',#1380,.T.);
#1382=ADVANCED_FACE('F2147',(#1381),#1370,.F.);
#1383=CARTESIAN_POINT('',(17.5,21.,14.0000000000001));
#1384=DIRECTION('',(-0.659184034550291,-0.477114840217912,0.581238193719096));
#1385=DIRECTION('',(0.66136903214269,0.,0.750060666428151));
#1386=AXIS2_PLACEMENT_3D('',#1383,#1384,#1385);
#1387=PLANE('',#1386);
#1388=ORIENTED_EDGE('',*,*,#1377,.T.);
#1389=ORIENTED_EDGE('',*,*,#1275,.F.);
#1390=DIRECTION('',(0.284545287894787,0.557211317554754,0.780095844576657));
#1391=VECTOR('',#1390,1.);
#1392=CARTESIAN_POINT('',(17.5,21.,14.0000000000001));
#1393=LINE('',#1392,#1391);
#1394=EDGE_CURVE('E1134',#808,#1266,#1393,.F.);
#1395=ORIENTED_EDGE('',*,*,#1394,.F.);
#1396=ORIENTED_EDGE('',*,*,#809,.F.);
#1397=EDGE_LOOP('',(#1388,#1389,#1395,#1396));
#1398=FACE_BOUND('',#1397,.T.);
#1399=ADVANCED_FACE('F2141',(#1398),#1387,.F.);
#1400=CARTESIAN_POINT('',(-17.5,21.,14.0000000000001));
#1401=DIRECTION('',(0.,-0.813733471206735,0.581238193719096));
#1402=DIRECTION('',(0.,-0.581238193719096,-0.813733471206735));
#1403=AXIS2_PLACEMENT_3D('',#1400,#1401,#1402);
#1404=PLANE('',#1403);
#1405=DIRECTION('',(-0.284545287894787,0.557211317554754,0.780095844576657));
#1406=VECTOR('',#1405,1.);
#1407=CARTESIAN_POINT('',(-17.5,21.,14.0000000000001));
#1408=LINE('',#1407,#1406);
#1409=EDGE_CURVE('E1131',#907,#1258,#1408,.F.);
#1410=ORIENTED_EDGE('',*,*,#1409,.F.);
#1411=ORIENTED_EDGE('',*,*,#908,.F.);
#1412=ORIENTED_EDGE('',*,*,#1394,.T.);
#1413=ORIENTED_EDGE('',*,*,#1267,.F.);
#1414=EDGE_LOOP('',(#1410,#1411,#1412,#1413));
#1415=FACE_BOUND('',#1414,.T.);
#1416=ADVANCED_FACE('F2105',(#1415),#1404,.F.);
#1417=CARTESIAN_POINT('',(-27.6331455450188,7.,14.0000000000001));
#1418=DIRECTION('',(0.659184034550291,-0.477114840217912,0.581238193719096));
#1419=DIRECTION('',(0.66136903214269,0.,-0.750060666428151));
#1420=AXIS2_PLACEMENT_3D('',#1417,#1418,#1419);
#1421=PLANE('',#1420);
#1422=ORIENTED_EDGE('',*,*,#1409,.T.);
#1423=ORIENTED_EDGE('',*,*,#1259,.F.);
#1424=DIRECTION('',(-0.563228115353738,0.198879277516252,0.802010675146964));
#1425=VECTOR('',#1424,1.);
#1426=CARTESIAN_POINT('',(-27.6331455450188,7.,14.0000000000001));
#1427=LINE('',#1426,#1425);
#1428=EDGE_CURVE('E1056',#939,#1250,#1427,.F.);
#1429=ORIENTED_EDGE('',*,*,#1428,.F.);
#1430=ORIENTED_EDGE('',*,*,#940,.F.);
#1431=EDGE_LOOP('',(#1422,#1423,#1429,#1430));
#1432=FACE_BOUND('',#1431,.T.);
#1433=ADVANCED_FACE('F2109',(#1432),#1421,.F.);
#1434=CARTESIAN_POINT('',(-27.6331455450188,7.,14.0000000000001));
#1435=DIRECTION('',(0.812618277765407,-0.0425875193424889,0.581238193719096));
#1436=DIRECTION('',(0.581766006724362,0.,-0.813356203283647));
#1437=AXIS2_PLACEMENT_3D('',#1434,#1435,#1436);
#1438=PLANE('',#1437);
#1439=ORIENTED_EDGE('',*,*,#1428,.T.);
#1440=ORIENTED_EDGE('',*,*,#1251,.F.);
#1441=ORIENTED_EDGE('',*,*,#1126,.F.);
#1442=ORIENTED_EDGE('',*,*,#971,.F.);
#1443=EDGE_LOOP('',(#1439,#1440,#1441,#1442));
#1444=FACE_BOUND('',#1443,.T.);
#1445=ADVANCED_FACE('F2113',(#1444),#1438,.F.);
#1446=CARTESIAN_POINT('',(8.,2.,132.999999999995));
#1447=DIRECTION('',(0.,0.,-1.));
#1448=DIRECTION('',(-1.,0.,0.));
#1449=AXIS2_PLACEMENT_3D('',#1446,#1447,#1448);
#1450=CYLINDRICAL_SURFACE('',#1449,3.99999999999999);
#1451=ORIENTED_EDGE('',*,*,#1234,.T.);
#1452=DIRECTION('',(0.,0.,-1.));
#1453=VECTOR('',#1452,1.);
#1454=CARTESIAN_POINT('',(4.00548186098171,2.20934382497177,132.999999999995));
#1455=LINE('',#1454,#1453);
#1456=CARTESIAN_POINT('',(4.00548186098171,2.20934382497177,132.922848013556));
#1457=VERTEX_POINT('',#1456);
#1458=EDGE_CURVE('E1053',#1457,#1226,#1455,.T.);
#1459=ORIENTED_EDGE('',*,*,#1458,.F.);
#1460=CARTESIAN_POINT('',(8.,2.,132.930158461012));
#1461=DIRECTION('',(0.,0.034899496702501,0.999390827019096));
#1462=DIRECTION('',(0.,0.999390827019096,-0.034899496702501));
#1463=AXIS2_PLACEMENT_3D('',#1460,#1461,#1462);
#1464=ELLIPSE('',#1463,4.00243817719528,3.99999999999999);
#1465=CARTESIAN_POINT('',(11.9945181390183,2.20934382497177,132.922848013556));
#1466=VERTEX_POINT('',#1465);
#1467=EDGE_CURVE('E1154',#1466,#1457,#1464,.T.);
#1468=ORIENTED_EDGE('',*,*,#1467,.F.);
#1469=DIRECTION('',(0.,0.,-1.));
#1470=VECTOR('',#1469,1.);
#1471=CARTESIAN_POINT('',(11.9945181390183,2.20934382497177,132.999999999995));
#1472=LINE('',#1471,#1470);
#1473=EDGE_CURVE('E1049',#1466,#1178,#1472,.T.);
#1474=ORIENTED_EDGE('',*,*,#1473,.T.);
#1475=EDGE_LOOP('',(#1451,#1459,#1468,#1474));
#1476=FACE_BOUND('',#1475,.T.);
#1477=ADVANCED_FACE('F2172',(#1476),#1450,.T.);
#1478=CARTESIAN_POINT('',(3.88969505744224,0.,132.999999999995));
#1479=DIRECTION('',(0.998629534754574,-0.0523359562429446,0.));
#1480=DIRECTION('',(0.0523359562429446,0.998629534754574,0.));
#1481=AXIS2_PLACEMENT_3D('',#1478,#1479,#1480);
#1482=PLANE('',#1481);
#1483=ORIENTED_EDGE('',*,*,#1227,.T.);
#1484=ORIENTED_EDGE('',*,*,#1103,.F.);
#1485=DIRECTION('',(-0.0523041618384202,-0.998022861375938,0.0348517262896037));
#1486=VECTOR('',#1485,1.);
#1487=CARTESIAN_POINT('',(3.88969505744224,0.,132.999999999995));
#1488=LINE('',#1487,#1486);
#1489=EDGE_CURVE('E1172',#1457,#1094,#1488,.T.);
#1490=ORIENTED_EDGE('',*,*,#1489,.F.);
#1491=ORIENTED_EDGE('',*,*,#1458,.T.);
#1492=EDGE_LOOP('',(#1483,#1484,#1490,#1491));
#1493=FACE_BOUND('',#1492,.T.);
#1494=ADVANCED_FACE('F2174',(#1493),#1482,.F.);
#1495=CARTESIAN_POINT('',(12.1103049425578,0.,132.999999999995));
#1496=DIRECTION('',(-0.998629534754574,-0.0523359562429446,0.));
#1497=DIRECTION('',(0.0523359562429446,-0.998629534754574,0.));
#1498=AXIS2_PLACEMENT_3D('',#1495,#1496,#1497);
#1499=PLANE('',#1498);
#1500=ORIENTED_EDGE('',*,*,#1179,.T.);
#1501=ORIENTED_EDGE('',*,*,#1473,.F.);
#1502=DIRECTION('',(-0.0523041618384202,0.998022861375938,-0.0348517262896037));
#1503=VECTOR('',#1502,1.);
#1504=CARTESIAN_POINT('',(12.1103049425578,0.,132.999999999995));
#1505=LINE('',#1504,#1503);
#1506=EDGE_CURVE('E1047',#1002,#1466,#1505,.T.);
#1507=ORIENTED_EDGE('',*,*,#1506,.F.);
#1508=ORIENTED_EDGE('',*,*,#1163,.T.);
#1509=EDGE_LOOP('',(#1500,#1501,#1507,#1508));
#1510=FACE_BOUND('',#1509,.T.);
#1511=ADVANCED_FACE('F2166',(#1510),#1499,.F.);
#1512=CARTESIAN_POINT('',(3.88969505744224,0.,132.999999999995));
#1513=DIRECTION('',(0.,0.034899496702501,0.999390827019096));
#1514=DIRECTION('',(0.,-0.999390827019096,0.034899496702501));
#1515=AXIS2_PLACEMENT_3D('',#1512,#1513,#1514);
#1516=PLANE('',#1515);
#1517=DIRECTION('',(-0.0523041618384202,-0.998022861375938,0.0348517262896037));
#1518=VECTOR('',#1517,1.);
#1519=CARTESIAN_POINT('',(5.3876443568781,-0.0784085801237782,133.002738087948));
#1520=LINE('',#1519,#1518);
#1521=CARTESIAN_POINT('',(5.50342616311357,2.13083989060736,132.925589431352));
#1522=VERTEX_POINT('',#1521);
#1523=EDGE_CURVE('E1530',#1522,#1090,#1520,.T.);
#1524=ORIENTED_EDGE('',*,*,#1523,.F.);
#1525=CARTESIAN_POINT('',(8.,2.,132.930158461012));
#1526=DIRECTION('',(0.,0.034899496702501,0.999390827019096));
#1527=DIRECTION('',(0.,0.999390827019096,-0.034899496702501));
#1528=AXIS2_PLACEMENT_3D('',#1525,#1526,#1527);
#1529=ELLIPSE('',#1528,2.50152386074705,2.49999999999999);
#1530=CARTESIAN_POINT('',(10.4965738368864,2.13083989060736,132.925589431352));
#1531=VERTEX_POINT('',#1530);
#1532=EDGE_CURVE('E1294',#1531,#1522,#1529,.T.);
#1533=ORIENTED_EDGE('',*,*,#1532,.F.);
#1534=DIRECTION('',(-0.0523041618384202,0.998022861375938,-0.0348517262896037));
#1535=VECTOR('',#1534,1.);
#1536=CARTESIAN_POINT('',(10.6123556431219,-0.0784085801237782,133.002738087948));
#1537=LINE('',#1536,#1535);
#1538=EDGE_CURVE('E1327',#1000,#1531,#1537,.T.);
#1539=ORIENTED_EDGE('',*,*,#1538,.F.);
#1540=ORIENTED_EDGE('',*,*,#1003,.T.);
#1541=ORIENTED_EDGE('',*,*,#1506,.T.);
#1542=ORIENTED_EDGE('',*,*,#1467,.T.);
#1543=ORIENTED_EDGE('',*,*,#1489,.T.);
#1544=ORIENTED_EDGE('',*,*,#1095,.T.);
#1545=EDGE_LOOP('',(#1524,#1533,#1539,#1540,#1541,#1542,#1543,#1544));
#1546=FACE_BOUND('',#1545,.T.);
#1547=ADVANCED_FACE('F2022',(#1546),#1516,.T.);
#1548=CARTESIAN_POINT('',(12.5,20.9999999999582,19.0000000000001));
#1549=DIRECTION('',(0.998629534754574,-0.0523359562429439,0.));
#1550=DIRECTION('',(0.0523359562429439,0.998629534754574,0.));
#1551=AXIS2_PLACEMENT_3D('',#1548,#1549,#1550);
#1552=PLANE('',#1551);
#1553=ORIENTED_EDGE('',*,*,#858,.T.);
#1554=DIRECTION('',(0.052264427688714,0.997264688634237,-0.052264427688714));
#1555=VECTOR('',#1554,1.);
#1556=CARTESIAN_POINT('',(12.5,20.9999999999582,19.0000000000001));
#1557=LINE('',#1556,#1555);
#1558=CARTESIAN_POINT('',(12.3951844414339,18.9999999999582,19.1048155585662));
#1559=VERTEX_POINT('',#1558);
#1560=EDGE_CURVE('E1029',#1559,#849,#1557,.T.);
#1561=ORIENTED_EDGE('',*,*,#1560,.F.);
#1562=DIRECTION('',(0.,0.,-1.));
#1563=VECTOR('',#1562,1.);
#1564=CARTESIAN_POINT('',(12.3951844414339,18.9999999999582,19.0000000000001));
#1565=LINE('',#1564,#1563);
#1566=CARTESIAN_POINT('',(12.3951844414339,18.9999999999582,93.895184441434));
#1567=VERTEX_POINT('',#1566);
#1568=EDGE_CURVE('E1023',#1567,#1559,#1565,.T.);
#1569=ORIENTED_EDGE('',*,*,#1568,.F.);
#1570=DIRECTION('',(0.052264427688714,0.997264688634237,0.052264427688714));
#1571=VECTOR('',#1570,1.);
#1572=CARTESIAN_POINT('',(12.5,20.9999999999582,94.0000000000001));
#1573=LINE('',#1572,#1571);
#1574=EDGE_CURVE('E1024',#1567,#857,#1573,.T.);
#1575=ORIENTED_EDGE('',*,*,#1574,.T.);
#1576=EDGE_LOOP('',(#1553,#1561,#1569,#1575));
#1577=FACE_BOUND('',#1576,.T.);
#1578=ADVANCED_FACE('F2220',(#1577),#1552,.F.);
#1579=CARTESIAN_POINT('',(12.5,20.9999999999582,94.0000000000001));
#1580=DIRECTION('',(0.,-0.0523359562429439,0.998629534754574));
#1581=DIRECTION('',(0.,-0.998629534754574,-0.0523359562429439));
#1582=AXIS2_PLACEMENT_3D('',#1579,#1580,#1581);
#1583=PLANE('',#1582);
#1584=ORIENTED_EDGE('',*,*,#1574,.F.);
#1585=DIRECTION('',(1.,0.,0.));
#1586=VECTOR('',#1585,1.);
#1587=CARTESIAN_POINT('',(12.5,18.9999999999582,93.895184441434));
#1588=LINE('',#1587,#1586);
#1589=CARTESIAN_POINT('',(-12.3951844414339,18.9999999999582,93.895184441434));
#1590=VERTEX_POINT('',#1589);
#1591=EDGE_CURVE('E1033',#1590,#1567,#1588,.T.);
#1592=ORIENTED_EDGE('',*,*,#1591,.F.);
#1593=DIRECTION('',(-0.052264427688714,0.997264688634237,0.052264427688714));
#1594=VECTOR('',#1593,1.);
#1595=CARTESIAN_POINT('',(-12.2951322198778,17.0908898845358,93.7951322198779));
#1596=LINE('',#1595,#1594);
#1597=EDGE_CURVE('E1028',#1590,#841,#1596,.T.);
#1598=ORIENTED_EDGE('',*,*,#1597,.T.);
#1599=ORIENTED_EDGE('',*,*,#864,.T.);
#1600=EDGE_LOOP('',(#1584,#1592,#1598,#1599));
#1601=FACE_BOUND('',#1600,.T.);
#1602=ADVANCED_FACE('F2868',(#1601),#1583,.F.);
#1603=CARTESIAN_POINT('',(-12.5,20.9999999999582,19.0000000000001));
#1604=DIRECTION('',(-0.998629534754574,-0.0523359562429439,0.));
#1605=DIRECTION('',(0.0523359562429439,-0.998629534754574,0.));
#1606=AXIS2_PLACEMENT_3D('',#1603,#1604,#1605);
#1607=PLANE('',#1606);
#1608=ORIENTED_EDGE('',*,*,#1597,.F.);
#1609=DIRECTION('',(0.,0.,1.));
#1610=VECTOR('',#1609,1.);
#1611=CARTESIAN_POINT('',(-12.3951844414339,18.9999999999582,19.0000000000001));
#1612=LINE('',#1611,#1610);
#1613=CARTESIAN_POINT('',(-12.3951844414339,18.9999999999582,19.1048155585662));
#1614=VERTEX_POINT('',#1613);
#1615=EDGE_CURVE('E1041',#1614,#1590,#1612,.T.);
#1616=ORIENTED_EDGE('',*,*,#1615,.F.);
#1617=DIRECTION('',(-0.052264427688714,0.997264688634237,-0.052264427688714));
#1618=VECTOR('',#1617,1.);
#1619=CARTESIAN_POINT('',(-12.4317107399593,19.6969632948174,19.0682892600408));
#1620=LINE('',#1619,#1618);
#1621=EDGE_CURVE('E1032',#1614,#839,#1620,.T.);
#1622=ORIENTED_EDGE('',*,*,#1621,.T.);
#1623=ORIENTED_EDGE('',*,*,#842,.T.);
#1624=EDGE_LOOP('',(#1608,#1616,#1622,#1623));
#1625=FACE_BOUND('',#1624,.T.);
#1626=ADVANCED_FACE('F2876',(#1625),#1607,.F.);
#1627=CARTESIAN_POINT('',(12.5,20.9999999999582,19.0000000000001));
#1628=DIRECTION('',(0.,-0.0523359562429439,-0.998629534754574));
#1629=DIRECTION('',(0.,0.998629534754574,-0.0523359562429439));
#1630=AXIS2_PLACEMENT_3D('',#1627,#1628,#1629);
#1631=PLANE('',#1630);
#1632=ORIENTED_EDGE('',*,*,#850,.T.);
#1633=ORIENTED_EDGE('',*,*,#1621,.F.);
#1634=DIRECTION('',(-1.,0.,0.));
#1635=VECTOR('',#1634,1.);
#1636=CARTESIAN_POINT('',(12.5,18.9999999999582,19.1048155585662));
#1637=LINE('',#1636,#1635);
#1638=EDGE_CURVE('E1039',#1559,#1614,#1637,.T.);
#1639=ORIENTED_EDGE('',*,*,#1638,.F.);
#1640=ORIENTED_EDGE('',*,*,#1560,.T.);
#1641=EDGE_LOOP('',(#1632,#1633,#1639,#1640));
#1642=FACE_BOUND('',#1641,.T.);
#1643=ADVANCED_FACE('F2881',(#1642),#1631,.F.);
#1644=CARTESIAN_POINT('',(12.5,18.9999999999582,94.0000000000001));
#1645=DIRECTION('',(0.,-1.,0.));
#1646=DIRECTION('',(0.,0.,-1.));
#1647=AXIS2_PLACEMENT_3D('',#1644,#1645,#1646);
#1648=PLANE('',#1647);
#1649=DIRECTION('',(0.,0.,1.));
#1650=VECTOR('',#1649,1.);
#1651=CARTESIAN_POINT('',(-3.49999999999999,18.9999999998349,42.5000000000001));
#1652=LINE('',#1651,#1650);
#1653=CARTESIAN_POINT('',(-3.50000000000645,18.9999999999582,42.5000000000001));
#1654=VERTEX_POINT('',#1653);
#1655=CARTESIAN_POINT('',(-3.49999999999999,18.9999999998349,47.0000000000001));
#1656=VERTEX_POINT('',#1655);
#1657=EDGE_CURVE('E933',#1654,#1656,#1652,.T.);
#1658=ORIENTED_EDGE('',*,*,#1657,.F.);
#1659=CARTESIAN_POINT('',(0.,18.9999999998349,42.5000000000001));
#1660=DIRECTION('',(0.,1.,0.));
#1661=DIRECTION('',(0.,0.,1.));
#1662=AXIS2_PLACEMENT_3D('',#1659,#1660,#1661);
#1663=CIRCLE('',#1662,3.5);
#1664=CARTESIAN_POINT('',(3.5,18.9999999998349,42.5000000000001));
#1665=VERTEX_POINT('',#1664);
#1666=EDGE_CURVE('E917',#1665,#1654,#1663,.T.);
#1667=ORIENTED_EDGE('',*,*,#1666,.F.);
#1668=DIRECTION('',(0.,0.,-1.));
#1669=VECTOR('',#1668,1.);
#1670=CARTESIAN_POINT('',(3.5,18.9999999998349,47.0000000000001));
#1671=LINE('',#1670,#1669);
#1672=CARTESIAN_POINT('',(3.5,18.9999999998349,47.0000000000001));
#1673=VERTEX_POINT('',#1672);
#1674=EDGE_CURVE('E938',#1673,#1665,#1671,.T.);
#1675=ORIENTED_EDGE('',*,*,#1674,.F.);
#1676=DIRECTION('',(1.,0.,0.));
#1677=VECTOR('',#1676,1.);
#1678=CARTESIAN_POINT('',(-3.49999999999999,18.9999999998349,47.0000000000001));
#1679=LINE('',#1678,#1677);
#1680=EDGE_CURVE('E936',#1656,#1673,#1679,.T.);
#1681=ORIENTED_EDGE('',*,*,#1680,.F.);
#1682=EDGE_LOOP('',(#1658,#1667,#1675,#1681));
#1683=FACE_BOUND('',#1682,.T.);
#1684=DIRECTION('',(0.,0.,1.));
#1685=VECTOR('',#1684,1.);
#1686=CARTESIAN_POINT('',(-3.5,18.9999999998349,77.5000000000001));
#1687=LINE('',#1686,#1685);
#1688=CARTESIAN_POINT('',(-3.50000000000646,18.9999999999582,77.5000000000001));
#1689=VERTEX_POINT('',#1688);
#1690=CARTESIAN_POINT('',(-3.5,18.9999999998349,82.0000000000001));
#1691=VERTEX_POINT('',#1690);
#1692=EDGE_CURVE('E849',#1689,#1691,#1687,.T.);
#1693=ORIENTED_EDGE('',*,*,#1692,.F.);
#1694=CARTESIAN_POINT('',(0.,18.9999999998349,77.5000000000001));
#1695=DIRECTION('',(0.,1.,0.));
#1696=DIRECTION('',(0.,0.,1.));
#1697=AXIS2_PLACEMENT_3D('',#1694,#1695,#1696);
#1698=CIRCLE('',#1697,3.5);
#1699=CARTESIAN_POINT('',(3.5,18.9999999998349,77.5000000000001));
#1700=VERTEX_POINT('',#1699);
#1701=EDGE_CURVE('E832',#1700,#1689,#1698,.T.);
#1702=ORIENTED_EDGE('',*,*,#1701,.F.);
#1703=DIRECTION('',(0.,0.,-1.));
#1704=VECTOR('',#1703,1.);
#1705=CARTESIAN_POINT('',(3.5,18.9999999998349,82.0000000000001));
#1706=LINE('',#1705,#1704);
#1707=CARTESIAN_POINT('',(3.5,18.9999999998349,82.0000000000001));
#1708=VERTEX_POINT('',#1707);
#1709=EDGE_CURVE('E854',#1708,#1700,#1706,.T.);
#1710=ORIENTED_EDGE('',*,*,#1709,.F.);
#1711=DIRECTION('',(1.,0.,0.));
#1712=VECTOR('',#1711,1.);
#1713=CARTESIAN_POINT('',(-3.5,18.9999999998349,82.0000000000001));
#1714=LINE('',#1713,#1712);
#1715=EDGE_CURVE('E852',#1691,#1708,#1714,.T.);
#1716=ORIENTED_EDGE('',*,*,#1715,.F.);
#1717=EDGE_LOOP('',(#1693,#1702,#1710,#1716));
#1718=FACE_BOUND('',#1717,.T.);
#1719=ORIENTED_EDGE('',*,*,#1638,.T.);
#1720=ORIENTED_EDGE('',*,*,#1615,.T.);
#1721=ORIENTED_EDGE('',*,*,#1591,.T.);
#1722=ORIENTED_EDGE('',*,*,#1568,.T.);
#1723=EDGE_LOOP('',(#1719,#1720,#1721,#1722));
#1724=FACE_BOUND('',#1723,.T.);
#1725=DIRECTION('',(0.,0.,-1.));
#1726=VECTOR('',#1725,1.);
#1727=CARTESIAN_POINT('',(8.,18.9999999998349,70.0000000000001));
#1728=LINE('',#1727,#1726);
#1729=CARTESIAN_POINT('',(8.00000000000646,18.9999999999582,70.0000000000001));
#1730=VERTEX_POINT('',#1729);
#1731=CARTESIAN_POINT('',(8.,18.9999999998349,61.0000000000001));
#1732=VERTEX_POINT('',#1731);
#1733=EDGE_CURVE('E905',#1730,#1732,#1728,.T.);
#1734=ORIENTED_EDGE('',*,*,#1733,.F.);
#1735=DIRECTION('',(1.,0.,0.));
#1736=VECTOR('',#1735,1.);
#1737=CARTESIAN_POINT('',(4.,18.9999999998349,70.0000000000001));
#1738=LINE('',#1737,#1736);
#1739=CARTESIAN_POINT('',(4.,18.9999999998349,70.0000000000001));
#1740=VERTEX_POINT('',#1739);
#1741=EDGE_CURVE('E889',#1740,#1730,#1738,.T.);
#1742=ORIENTED_EDGE('',*,*,#1741,.F.);
#1743=DIRECTION('',(0.,0.,1.));
#1744=VECTOR('',#1743,1.);
#1745=CARTESIAN_POINT('',(4.,18.9999999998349,61.0000000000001));
#1746=LINE('',#1745,#1744);
#1747=CARTESIAN_POINT('',(4.,18.9999999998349,61.0000000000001));
#1748=VERTEX_POINT('',#1747);
#1749=EDGE_CURVE('E911',#1748,#1740,#1746,.T.);
#1750=ORIENTED_EDGE('',*,*,#1749,.F.);
#1751=DIRECTION('',(-1.,0.,0.));
#1752=VECTOR('',#1751,1.);
#1753=CARTESIAN_POINT('',(8.,18.9999999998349,61.0000000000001));
#1754=LINE('',#1753,#1752);
#1755=EDGE_CURVE('E908',#1732,#1748,#1754,.T.);
#1756=ORIENTED_EDGE('',*,*,#1755,.F.);
#1757=EDGE_LOOP('',(#1734,#1742,#1750,#1756));
#1758=FACE_BOUND('',#1757,.T.);
#1759=DIRECTION('',(0.,0.,-1.));
#1760=VECTOR('',#1759,1.);
#1761=CARTESIAN_POINT('',(8.00000000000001,18.9999999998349,35.0000000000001));
#1762=LINE('',#1761,#1760);
#1763=CARTESIAN_POINT('',(8.00000000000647,18.9999999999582,35.0000000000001));
#1764=VERTEX_POINT('',#1763);
#1765=CARTESIAN_POINT('',(8.00000000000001,18.9999999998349,26.0000000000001));
#1766=VERTEX_POINT('',#1765);
#1767=EDGE_CURVE('E989',#1764,#1766,#1762,.T.);
#1768=ORIENTED_EDGE('',*,*,#1767,.F.);
#1769=DIRECTION('',(1.,0.,0.));
#1770=VECTOR('',#1769,1.);
#1771=CARTESIAN_POINT('',(4.00000000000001,18.9999999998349,35.0000000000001));
#1772=LINE('',#1771,#1770);
#1773=CARTESIAN_POINT('',(4.00000000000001,18.9999999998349,35.0000000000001));
#1774=VERTEX_POINT('',#1773);
#1775=EDGE_CURVE('E973',#1774,#1764,#1772,.T.);
#1776=ORIENTED_EDGE('',*,*,#1775,.F.);
#1777=DIRECTION('',(0.,0.,1.));
#1778=VECTOR('',#1777,1.);
#1779=CARTESIAN_POINT('',(4.00000000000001,18.9999999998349,26.0000000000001));
#1780=LINE('',#1779,#1778);
#1781=CARTESIAN_POINT('',(4.00000000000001,18.9999999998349,26.0000000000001));
#1782=VERTEX_POINT('',#1781);
#1783=EDGE_CURVE('E995',#1782,#1774,#1780,.T.);
#1784=ORIENTED_EDGE('',*,*,#1783,.F.);
#1785=DIRECTION('',(-1.,0.,0.));
#1786=VECTOR('',#1785,1.);
#1787=CARTESIAN_POINT('',(8.00000000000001,18.9999999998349,26.0000000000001));
#1788=LINE('',#1787,#1786);
#1789=EDGE_CURVE('E992',#1766,#1782,#1788,.T.);
#1790=ORIENTED_EDGE('',*,*,#1789,.F.);
#1791=EDGE_LOOP('',(#1768,#1776,#1784,#1790));
#1792=FACE_BOUND('',#1791,.T.);
#1793=DIRECTION('',(0.,0.,-1.));
#1794=VECTOR('',#1793,1.);
#1795=CARTESIAN_POINT('',(-4.,18.9999999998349,71.0000000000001));
#1796=LINE('',#1795,#1794);
#1797=CARTESIAN_POINT('',(-3.99999999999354,18.9999999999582,71.0000000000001));
#1798=VERTEX_POINT('',#1797);
#1799=CARTESIAN_POINT('',(-4.,18.9999999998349,61.0000000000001));
#1800=VERTEX_POINT('',#1799);
#1801=EDGE_CURVE('E877',#1798,#1800,#1796,.T.);
#1802=ORIENTED_EDGE('',*,*,#1801,.F.);
#1803=DIRECTION('',(1.,0.,0.));
#1804=VECTOR('',#1803,1.);
#1805=CARTESIAN_POINT('',(-8.00000000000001,18.9999999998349,71.0000000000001));
#1806=LINE('',#1805,#1804);
#1807=CARTESIAN_POINT('',(-8.00000000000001,18.9999999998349,71.0000000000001));
#1808=VERTEX_POINT('',#1807);
#1809=EDGE_CURVE('E860',#1808,#1798,#1806,.T.);
#1810=ORIENTED_EDGE('',*,*,#1809,.F.);
#1811=DIRECTION('',(0.,0.,1.));
#1812=VECTOR('',#1811,1.);
#1813=CARTESIAN_POINT('',(-8.,18.9999999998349,61.0000000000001));
#1814=LINE('',#1813,#1812);
#1815=CARTESIAN_POINT('',(-8.,18.9999999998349,61.0000000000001));
#1816=VERTEX_POINT('',#1815);
#1817=EDGE_CURVE('E883',#1816,#1808,#1814,.T.);
#1818=ORIENTED_EDGE('',*,*,#1817,.F.);
#1819=DIRECTION('',(-1.,0.,0.));
#1820=VECTOR('',#1819,1.);
#1821=CARTESIAN_POINT('',(-4.,18.9999999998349,61.0000000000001));
#1822=LINE('',#1821,#1820);
#1823=EDGE_CURVE('E880',#1800,#1816,#1822,.T.);
#1824=ORIENTED_EDGE('',*,*,#1823,.F.);
#1825=EDGE_LOOP('',(#1802,#1810,#1818,#1824));
#1826=FACE_BOUND('',#1825,.T.);
#1827=DIRECTION('',(0.,0.,-1.));
#1828=VECTOR('',#1827,1.);
#1829=CARTESIAN_POINT('',(-4.,18.9999999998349,36.0000000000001));
#1830=LINE('',#1829,#1828);
#1831=CARTESIAN_POINT('',(-3.99999999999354,18.9999999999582,36.0000000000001));
#1832=VERTEX_POINT('',#1831);
#1833=CARTESIAN_POINT('',(-4.,18.9999999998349,26.0000000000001));
#1834=VERTEX_POINT('',#1833);
#1835=EDGE_CURVE('E961',#1832,#1834,#1830,.T.);
#1836=ORIENTED_EDGE('',*,*,#1835,.F.);
#1837=DIRECTION('',(1.,0.,0.));
#1838=VECTOR('',#1837,1.);
#1839=CARTESIAN_POINT('',(-8.,18.9999999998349,36.0000000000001));
#1840=LINE('',#1839,#1838);
#1841=CARTESIAN_POINT('',(-8.,18.9999999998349,36.0000000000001));
#1842=VERTEX_POINT('',#1841);
#1843=EDGE_CURVE('E944',#1842,#1832,#1840,.T.);
#1844=ORIENTED_EDGE('',*,*,#1843,.F.);
#1845=DIRECTION('',(0.,0.,1.));
#1846=VECTOR('',#1845,1.);
#1847=CARTESIAN_POINT('',(-8.,18.9999999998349,26.0000000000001));
#1848=LINE('',#1847,#1846);
#1849=CARTESIAN_POINT('',(-8.,18.9999999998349,26.0000000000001));
#1850=VERTEX_POINT('',#1849);
#1851=EDGE_CURVE('E967',#1850,#1842,#1848,.T.);
#1852=ORIENTED_EDGE('',*,*,#1851,.F.);
#1853=DIRECTION('',(-1.,0.,0.));
#1854=VECTOR('',#1853,1.);
#1855=CARTESIAN_POINT('',(-4.,18.9999999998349,26.0000000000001));
#1856=LINE('',#1855,#1854);
#1857=EDGE_CURVE('E964',#1834,#1850,#1856,.T.);
#1858=ORIENTED_EDGE('',*,*,#1857,.F.);
#1859=EDGE_LOOP('',(#1836,#1844,#1852,#1858));
#1860=FACE_BOUND('',#1859,.T.);
#1861=ADVANCED_FACE('F2311',(#1683,#1718,#1724,#1758,#1792,#1826,#1860),#1648,.F.);
#1862=CARTESIAN_POINT('',(4.00000000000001,18.9999999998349,35.0000000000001));
#1863=DIRECTION('',(0.,-0.0523359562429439,0.998629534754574));
#1864=DIRECTION('',(0.,-0.998629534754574,-0.0523359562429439));
#1865=AXIS2_PLACEMENT_3D('',#1862,#1863,#1864);
#1866=PLANE('',#1865);
#1867=ORIENTED_EDGE('',*,*,#1775,.T.);
#1868=DIRECTION('',(0.052264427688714,0.997264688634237,0.052264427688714));
#1869=VECTOR('',#1868,1.);
#1870=CARTESIAN_POINT('',(7.98907371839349,18.7915141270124,34.9890737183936));
#1871=LINE('',#1870,#1869);
#1872=CARTESIAN_POINT('',(7.79036888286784,14.9999999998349,34.7903688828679));
#1873=VERTEX_POINT('',#1872);
#1874=EDGE_CURVE('E1003',#1873,#1764,#1871,.T.);
#1875=ORIENTED_EDGE('',*,*,#1874,.F.);
#1876=DIRECTION('',(1.,0.,0.));
#1877=VECTOR('',#1876,1.);
#1878=CARTESIAN_POINT('',(4.00000000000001,14.9999999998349,34.7903688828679));
#1879=LINE('',#1878,#1877);
#1880=CARTESIAN_POINT('',(4.20963111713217,14.9999999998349,34.7903688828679));
#1881=VERTEX_POINT('',#1880);
#1882=EDGE_CURVE('E998',#1881,#1873,#1879,.T.);
#1883=ORIENTED_EDGE('',*,*,#1882,.F.);
#1884=DIRECTION('',(-0.052264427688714,0.997264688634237,0.052264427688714));
#1885=VECTOR('',#1884,1.);
#1886=CARTESIAN_POINT('',(4.02458413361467,18.5309067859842,34.9754158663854));
#1887=LINE('',#1886,#1885);
#1888=EDGE_CURVE('E999',#1881,#1774,#1887,.T.);
#1889=ORIENTED_EDGE('',*,*,#1888,.T.);
#1890=EDGE_LOOP('',(#1867,#1875,#1883,#1889));
#1891=FACE_BOUND('',#1890,.T.);
#1892=ADVANCED_FACE('F2305',(#1891),#1866,.F.);
#1893=CARTESIAN_POINT('',(4.00000000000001,18.9999999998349,26.0000000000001));
#1894=DIRECTION('',(-0.998629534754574,-0.0523359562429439,0.));
#1895=DIRECTION('',(0.0523359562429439,-0.998629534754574,0.));
#1896=AXIS2_PLACEMENT_3D('',#1893,#1894,#1895);
#1897=PLANE('',#1896);
#1898=ORIENTED_EDGE('',*,*,#1783,.T.);
#1899=ORIENTED_EDGE('',*,*,#1888,.F.);
#1900=DIRECTION('',(0.,0.,1.));
#1901=VECTOR('',#1900,1.);
#1902=CARTESIAN_POINT('',(4.20963111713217,14.9999999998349,26.0000000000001));
#1903=LINE('',#1902,#1901);
#1904=CARTESIAN_POINT('',(4.20963111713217,14.9999999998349,26.2096311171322));
#1905=VERTEX_POINT('',#1904);
#1906=EDGE_CURVE('E1007',#1905,#1881,#1903,.T.);
#1907=ORIENTED_EDGE('',*,*,#1906,.F.);
#1908=DIRECTION('',(-0.052264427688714,0.997264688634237,-0.052264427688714));
#1909=VECTOR('',#1908,1.);
#1910=CARTESIAN_POINT('',(4.01092628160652,18.7915141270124,26.0109262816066));
#1911=LINE('',#1910,#1909);
#1912=EDGE_CURVE('E1002',#1905,#1782,#1911,.T.);
#1913=ORIENTED_EDGE('',*,*,#1912,.T.);
#1914=EDGE_LOOP('',(#1898,#1899,#1907,#1913));
#1915=FACE_BOUND('',#1914,.T.);
#1916=ADVANCED_FACE('F2310',(#1915),#1897,.F.);
#1917=CARTESIAN_POINT('',(8.00000000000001,18.9999999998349,26.0000000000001));
#1918=DIRECTION('',(0.,-0.0523359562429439,-0.998629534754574));
#1919=DIRECTION('',(0.,0.998629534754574,-0.0523359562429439));
#1920=AXIS2_PLACEMENT_3D('',#1917,#1918,#1919);
#1921=PLANE('',#1920);
#1922=ORIENTED_EDGE('',*,*,#1789,.T.);
#1923=ORIENTED_EDGE('',*,*,#1912,.F.);
#1924=DIRECTION('',(-1.,0.,0.));
#1925=VECTOR('',#1924,1.);
#1926=CARTESIAN_POINT('',(8.00000000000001,14.9999999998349,26.2096311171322));
#1927=LINE('',#1926,#1925);
#1928=CARTESIAN_POINT('',(7.79036888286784,14.9999999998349,26.2096311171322));
#1929=VERTEX_POINT('',#1928);
#1930=EDGE_CURVE('E1013',#1929,#1905,#1927,.T.);
#1931=ORIENTED_EDGE('',*,*,#1930,.F.);
#1932=DIRECTION('',(0.052264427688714,0.997264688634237,-0.052264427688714));
#1933=VECTOR('',#1932,1.);
#1934=CARTESIAN_POINT('',(7.97541586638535,18.5309067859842,26.0245841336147));
#1935=LINE('',#1934,#1933);
#1936=EDGE_CURVE('E1006',#1929,#1766,#1935,.T.);
#1937=ORIENTED_EDGE('',*,*,#1936,.T.);
#1938=EDGE_LOOP('',(#1922,#1923,#1931,#1937));
#1939=FACE_BOUND('',#1938,.T.);
#1940=ADVANCED_FACE('F2323',(#1939),#1921,.F.);
#1941=CARTESIAN_POINT('',(8.00000000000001,18.9999999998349,35.0000000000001));
#1942=DIRECTION('',(0.998629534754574,-0.0523359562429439,0.));
#1943=DIRECTION('',(0.0523359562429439,0.998629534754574,0.));
#1944=AXIS2_PLACEMENT_3D('',#1941,#1942,#1943);
#1945=PLANE('',#1944);
#1946=ORIENTED_EDGE('',*,*,#1767,.T.);
#1947=ORIENTED_EDGE('',*,*,#1936,.F.);
#1948=DIRECTION('',(0.,0.,-1.));
#1949=VECTOR('',#1948,1.);
#1950=CARTESIAN_POINT('',(7.79036888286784,14.9999999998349,35.0000000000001));
#1951=LINE('',#1950,#1949);
#1952=EDGE_CURVE('E1011',#1873,#1929,#1951,.T.);
#1953=ORIENTED_EDGE('',*,*,#1952,.F.);
#1954=ORIENTED_EDGE('',*,*,#1874,.T.);
#1955=EDGE_LOOP('',(#1946,#1947,#1953,#1954));
#1956=FACE_BOUND('',#1955,.T.);
#1957=ADVANCED_FACE('F2333',(#1956),#1945,.F.);
#1958=CARTESIAN_POINT('',(-8.,18.9999999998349,36.0000000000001));
#1959=DIRECTION('',(0.,-0.0523359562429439,0.998629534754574));
#1960=DIRECTION('',(0.,-0.998629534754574,-0.0523359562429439));
#1961=AXIS2_PLACEMENT_3D('',#1958,#1959,#1960);
#1962=PLANE('',#1961);
#1963=ORIENTED_EDGE('',*,*,#1843,.T.);
#1964=DIRECTION('',(0.052264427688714,0.997264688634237,0.052264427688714));
#1965=VECTOR('',#1964,1.);
#1966=CARTESIAN_POINT('',(-4.01092628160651,18.7915141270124,35.9890737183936));
#1967=LINE('',#1966,#1965);
#1968=CARTESIAN_POINT('',(-4.20963111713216,14.9999999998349,35.7903688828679));
#1969=VERTEX_POINT('',#1968);
#1970=EDGE_CURVE('E975',#1969,#1832,#1967,.T.);
#1971=ORIENTED_EDGE('',*,*,#1970,.F.);
#1972=DIRECTION('',(1.,0.,0.));
#1973=VECTOR('',#1972,1.);
#1974=CARTESIAN_POINT('',(-4.,14.9999999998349,35.7903688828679));
#1975=LINE('',#1974,#1973);
#1976=CARTESIAN_POINT('',(-7.79036888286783,14.9999999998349,35.7903688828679));
#1977=VERTEX_POINT('',#1976);
#1978=EDGE_CURVE('E970',#1977,#1969,#1975,.T.);
#1979=ORIENTED_EDGE('',*,*,#1978,.F.);
#1980=DIRECTION('',(-0.052264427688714,0.997264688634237,0.052264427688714));
#1981=VECTOR('',#1980,1.);
#1982=CARTESIAN_POINT('',(-7.97268429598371,18.4787853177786,35.9726842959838));
#1983=LINE('',#1982,#1981);
#1984=EDGE_CURVE('E971',#1977,#1842,#1983,.T.);
#1985=ORIENTED_EDGE('',*,*,#1984,.T.);
#1986=EDGE_LOOP('',(#1963,#1971,#1979,#1985));
#1987=FACE_BOUND('',#1986,.T.);
#1988=ADVANCED_FACE('F2343',(#1987),#1962,.F.);
#1989=CARTESIAN_POINT('',(-8.,18.9999999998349,26.0000000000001));
#1990=DIRECTION('',(-0.998629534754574,-0.0523359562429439,0.));
#1991=DIRECTION('',(0.0523359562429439,-0.998629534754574,0.));
#1992=AXIS2_PLACEMENT_3D('',#1989,#1990,#1991);
#1993=PLANE('',#1992);
#1994=ORIENTED_EDGE('',*,*,#1851,.T.);
#1995=ORIENTED_EDGE('',*,*,#1984,.F.);
#1996=DIRECTION('',(0.,0.,1.));
#1997=VECTOR('',#1996,1.);
#1998=CARTESIAN_POINT('',(-7.79036888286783,14.9999999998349,36.0000000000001));
#1999=LINE('',#1998,#1997);
#2000=CARTESIAN_POINT('',(-7.79036888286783,14.9999999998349,26.2096311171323));
#2001=VERTEX_POINT('',#2000);
#2002=EDGE_CURVE('E979',#2001,#1977,#1999,.T.);
#2003=ORIENTED_EDGE('',*,*,#2002,.F.);
#2004=DIRECTION('',(-0.052264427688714,0.997264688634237,-0.052264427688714));
#2005=VECTOR('',#2004,1.);
#2006=CARTESIAN_POINT('',(-7.98907371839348,18.7915141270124,26.0109262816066));
#2007=LINE('',#2006,#2005);
#2008=EDGE_CURVE('E974',#2001,#1850,#2007,.T.);
#2009=ORIENTED_EDGE('',*,*,#2008,.T.);
#2010=EDGE_LOOP('',(#1994,#1995,#2003,#2009));
#2011=FACE_BOUND('',#2010,.T.);
#2012=ADVANCED_FACE('F2353',(#2011),#1993,.F.);
#2013=CARTESIAN_POINT('',(-4.,18.9999999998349,26.0000000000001));
#2014=DIRECTION('',(0.,-0.0523359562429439,-0.998629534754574));
#2015=DIRECTION('',(0.,0.998629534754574,-0.0523359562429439));
#2016=AXIS2_PLACEMENT_3D('',#2013,#2014,#2015);
#2017=PLANE('',#2016);
#2018=ORIENTED_EDGE('',*,*,#1857,.T.);
#2019=ORIENTED_EDGE('',*,*,#2008,.F.);
#2020=DIRECTION('',(-1.,0.,0.));
#2021=VECTOR('',#2020,1.);
#2022=CARTESIAN_POINT('',(-4.,14.9999999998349,26.2096311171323));
#2023=LINE('',#2022,#2021);
#2024=CARTESIAN_POINT('',(-4.20963111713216,14.9999999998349,26.2096311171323));
#2025=VERTEX_POINT('',#2024);
#2026=EDGE_CURVE('E985',#2025,#2001,#2023,.T.);
#2027=ORIENTED_EDGE('',*,*,#2026,.F.);
#2028=DIRECTION('',(0.052264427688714,0.997264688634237,-0.052264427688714));
#2029=VECTOR('',#2028,1.);
#2030=CARTESIAN_POINT('',(-4.02731570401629,18.4787853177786,26.0273157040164));
#2031=LINE('',#2030,#2029);
#2032=EDGE_CURVE('E978',#2025,#1834,#2031,.T.);
#2033=ORIENTED_EDGE('',*,*,#2032,.T.);
#2034=EDGE_LOOP('',(#2018,#2019,#2027,#2033));
#2035=FACE_BOUND('',#2034,.T.);
#2036=ADVANCED_FACE('F2363',(#2035),#2017,.F.);
#2037=CARTESIAN_POINT('',(-4.,18.9999999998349,36.0000000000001));
#2038=DIRECTION('',(0.998629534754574,-0.0523359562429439,0.));
#2039=DIRECTION('',(0.0523359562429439,0.998629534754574,0.));
#2040=AXIS2_PLACEMENT_3D('',#2037,#2038,#2039);
#2041=PLANE('',#2040);
#2042=ORIENTED_EDGE('',*,*,#1835,.T.);
#2043=ORIENTED_EDGE('',*,*,#2032,.F.);
#2044=DIRECTION('',(0.,0.,-1.));
#2045=VECTOR('',#2044,1.);
#2046=CARTESIAN_POINT('',(-4.20963111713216,14.9999999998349,36.0000000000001));
#2047=LINE('',#2046,#2045);
#2048=EDGE_CURVE('E983',#1969,#2025,#2047,.T.);
#2049=ORIENTED_EDGE('',*,*,#2048,.F.);
#2050=ORIENTED_EDGE('',*,*,#1970,.T.);
#2051=EDGE_LOOP('',(#2042,#2043,#2049,#2050));
#2052=FACE_BOUND('',#2051,.T.);
#2053=ADVANCED_FACE('F2373',(#2052),#2041,.F.);
#2054=CARTESIAN_POINT('',(0.,18.9999999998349,42.5000000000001));
#2055=DIRECTION('',(0.,1.,0.));
#2056=DIRECTION('',(0.,0.,1.));
#2057=AXIS2_PLACEMENT_3D('',#2054,#2055,#2056);
#2058=CONICAL_SURFACE('',#2057,3.5,0.0523598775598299);
#2059=ORIENTED_EDGE('',*,*,#1666,.T.);
#2060=DIRECTION('',(-0.0523359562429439,0.998629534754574,0.));
#2061=VECTOR('',#2060,1.);
#2062=CARTESIAN_POINT('',(-3.49999999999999,18.9999999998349,42.5000000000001));
#2063=LINE('',#2062,#2061);
#2064=CARTESIAN_POINT('',(-3.29036888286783,14.9999999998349,42.5000000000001));
#2065=VERTEX_POINT('',#2064);
#2066=EDGE_CURVE('E946',#2065,#1654,#2063,.T.);
#2067=ORIENTED_EDGE('',*,*,#2066,.F.);
#2068=CARTESIAN_POINT('',(0.,14.9999999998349,42.5000000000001));
#2069=DIRECTION('',(0.,1.,0.));
#2070=DIRECTION('',(0.,0.,1.));
#2071=AXIS2_PLACEMENT_3D('',#2068,#2069,#2070);
#2072=CIRCLE('',#2071,3.29036888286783);
#2073=CARTESIAN_POINT('',(3.29036888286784,14.9999999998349,42.5000000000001));
#2074=VERTEX_POINT('',#2073);
#2075=EDGE_CURVE('E941',#2074,#2065,#2072,.T.);
#2076=ORIENTED_EDGE('',*,*,#2075,.F.);
#2077=DIRECTION('',(0.0523359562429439,0.998629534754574,0.));
#2078=VECTOR('',#2077,1.);
#2079=CARTESIAN_POINT('',(3.5,18.9999999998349,42.5000000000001));
#2080=LINE('',#2079,#2078);
#2081=EDGE_CURVE('E942',#2074,#1665,#2080,.T.);
#2082=ORIENTED_EDGE('',*,*,#2081,.T.);
#2083=EDGE_LOOP('',(#2059,#2067,#2076,#2082));
#2084=FACE_BOUND('',#2083,.T.);
#2085=ADVANCED_FACE('F2383',(#2084),#2058,.F.);
#2086=CARTESIAN_POINT('',(3.5,18.9999999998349,47.0000000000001));
#2087=DIRECTION('',(0.998629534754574,-0.0523359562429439,0.));
#2088=DIRECTION('',(0.0523359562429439,0.998629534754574,0.));
#2089=AXIS2_PLACEMENT_3D('',#2086,#2087,#2088);
#2090=PLANE('',#2089);
#2091=ORIENTED_EDGE('',*,*,#1674,.T.);
#2092=ORIENTED_EDGE('',*,*,#2081,.F.);
#2093=DIRECTION('',(0.,0.,-1.));
#2094=VECTOR('',#2093,1.);
#2095=CARTESIAN_POINT('',(3.29036888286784,14.9999999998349,42.5000000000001));
#2096=LINE('',#2095,#2094);
#2097=CARTESIAN_POINT('',(3.29036888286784,14.9999999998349,46.7903688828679));
#2098=VERTEX_POINT('',#2097);
#2099=EDGE_CURVE('E950',#2098,#2074,#2096,.T.);
#2100=ORIENTED_EDGE('',*,*,#2099,.F.);
#2101=DIRECTION('',(0.052264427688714,0.997264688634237,0.052264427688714));
#2102=VECTOR('',#2101,1.);
#2103=CARTESIAN_POINT('',(3.4808790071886,18.6351497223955,46.9808790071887));
#2104=LINE('',#2103,#2102);
#2105=EDGE_CURVE('E945',#2098,#1673,#2104,.T.);
#2106=ORIENTED_EDGE('',*,*,#2105,.T.);
#2107=EDGE_LOOP('',(#2091,#2092,#2100,#2106));
#2108=FACE_BOUND('',#2107,.T.);
#2109=ADVANCED_FACE('F2391',(#2108),#2090,.F.);
#2110=CARTESIAN_POINT('',(-3.49999999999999,18.9999999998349,47.0000000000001));
#2111=DIRECTION('',(0.,-0.0523359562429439,0.998629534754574));
#2112=DIRECTION('',(0.,-0.998629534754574,-0.0523359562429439));
#2113=AXIS2_PLACEMENT_3D('',#2110,#2111,#2112);
#2114=PLANE('',#2113);
#2115=ORIENTED_EDGE('',*,*,#2105,.F.);
#2116=DIRECTION('',(1.,0.,0.));
#2117=VECTOR('',#2116,1.);
#2118=CARTESIAN_POINT('',(0.,14.9999999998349,46.7903688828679));
#2119=LINE('',#2118,#2117);
#2120=CARTESIAN_POINT('',(-3.29036888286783,14.9999999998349,46.7903688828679));
#2121=VERTEX_POINT('',#2120);
#2122=EDGE_CURVE('E957',#2121,#2098,#2119,.T.);
#2123=ORIENTED_EDGE('',*,*,#2122,.F.);
#2124=DIRECTION('',(-0.052264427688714,0.997264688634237,0.052264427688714));
#2125=VECTOR('',#2124,1.);
#2126=CARTESIAN_POINT('',(-3.48770793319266,18.7654533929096,46.9877079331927));
#2127=LINE('',#2126,#2125);
#2128=EDGE_CURVE('E949',#2121,#1656,#2127,.T.);
#2129=ORIENTED_EDGE('',*,*,#2128,.T.);
#2130=ORIENTED_EDGE('',*,*,#1680,.T.);
#2131=EDGE_LOOP('',(#2115,#2123,#2129,#2130));
#2132=FACE_BOUND('',#2131,.T.);
#2133=ADVANCED_FACE('F2396',(#2132),#2114,.F.);
#2134=CARTESIAN_POINT('',(-3.49999999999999,18.9999999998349,42.5000000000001));
#2135=DIRECTION('',(-0.998629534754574,-0.0523359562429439,0.));
#2136=DIRECTION('',(0.0523359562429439,-0.998629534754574,0.));
#2137=AXIS2_PLACEMENT_3D('',#2134,#2135,#2136);
#2138=PLANE('',#2137);
#2139=ORIENTED_EDGE('',*,*,#1657,.T.);
#2140=ORIENTED_EDGE('',*,*,#2128,.F.);
#2141=DIRECTION('',(0.,0.,1.));
#2142=VECTOR('',#2141,1.);
#2143=CARTESIAN_POINT('',(-3.29036888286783,14.9999999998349,42.5000000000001));
#2144=LINE('',#2143,#2142);
#2145=EDGE_CURVE('E955',#2065,#2121,#2144,.T.);
#2146=ORIENTED_EDGE('',*,*,#2145,.F.);
#2147=ORIENTED_EDGE('',*,*,#2066,.T.);
#2148=EDGE_LOOP('',(#2139,#2140,#2146,#2147));
#2149=FACE_BOUND('',#2148,.T.);
#2150=ADVANCED_FACE('F2404',(#2149),#2138,.F.);
#2151=CARTESIAN_POINT('',(4.,18.9999999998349,70.0000000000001));
#2152=DIRECTION('',(0.,-0.0523359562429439,0.998629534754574));
#2153=DIRECTION('',(0.,-0.998629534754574,-0.0523359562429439));
#2154=AXIS2_PLACEMENT_3D('',#2151,#2152,#2153);
#2155=PLANE('',#2154);
#2156=ORIENTED_EDGE('',*,*,#1741,.T.);
#2157=DIRECTION('',(0.052264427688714,0.997264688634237,0.052264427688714));
#2158=VECTOR('',#2157,1.);
#2159=CARTESIAN_POINT('',(7.98907371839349,18.7915141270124,69.9890737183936));
#2160=LINE('',#2159,#2158);
#2161=CARTESIAN_POINT('',(7.79036888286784,14.9999999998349,69.7903688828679));
#2162=VERTEX_POINT('',#2161);
#2163=EDGE_CURVE('E919',#2162,#1730,#2160,.T.);
#2164=ORIENTED_EDGE('',*,*,#2163,.F.);
#2165=DIRECTION('',(1.,0.,0.));
#2166=VECTOR('',#2165,1.);
#2167=CARTESIAN_POINT('',(4.,14.9999999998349,69.7903688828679));
#2168=LINE('',#2167,#2166);
#2169=CARTESIAN_POINT('',(4.20963111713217,14.9999999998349,69.7903688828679));
#2170=VERTEX_POINT('',#2169);
#2171=EDGE_CURVE('E914',#2170,#2162,#2168,.T.);
#2172=ORIENTED_EDGE('',*,*,#2171,.F.);
#2173=DIRECTION('',(-0.052264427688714,0.997264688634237,0.052264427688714));
#2174=VECTOR('',#2173,1.);
#2175=CARTESIAN_POINT('',(4.02458413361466,18.5309067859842,69.9754158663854));
#2176=LINE('',#2175,#2174);
#2177=EDGE_CURVE('E915',#2170,#1740,#2176,.T.);
#2178=ORIENTED_EDGE('',*,*,#2177,.T.);
#2179=EDGE_LOOP('',(#2156,#2164,#2172,#2178));
#2180=FACE_BOUND('',#2179,.T.);
#2181=ADVANCED_FACE('F2409',(#2180),#2155,.F.);
#2182=CARTESIAN_POINT('',(4.,18.9999999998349,61.0000000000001));
#2183=DIRECTION('',(-0.998629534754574,-0.0523359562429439,0.));
#2184=DIRECTION('',(0.0523359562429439,-0.998629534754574,0.));
#2185=AXIS2_PLACEMENT_3D('',#2182,#2183,#2184);
#2186=PLANE('',#2185);
#2187=ORIENTED_EDGE('',*,*,#1749,.T.);
#2188=ORIENTED_EDGE('',*,*,#2177,.F.);
#2189=DIRECTION('',(0.,0.,1.));
#2190=VECTOR('',#2189,1.);
#2191=CARTESIAN_POINT('',(4.20963111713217,14.9999999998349,61.0000000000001));
#2192=LINE('',#2191,#2190);
#2193=CARTESIAN_POINT('',(4.20963111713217,14.9999999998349,61.2096311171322));
#2194=VERTEX_POINT('',#2193);
#2195=EDGE_CURVE('E923',#2194,#2170,#2192,.T.);
#2196=ORIENTED_EDGE('',*,*,#2195,.F.);
#2197=DIRECTION('',(-0.052264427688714,0.997264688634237,-0.052264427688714));
#2198=VECTOR('',#2197,1.);
#2199=CARTESIAN_POINT('',(4.01092628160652,18.7915141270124,61.0109262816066));
#2200=LINE('',#2199,#2198);
#2201=EDGE_CURVE('E918',#2194,#1748,#2200,.T.);
#2202=ORIENTED_EDGE('',*,*,#2201,.T.);
#2203=EDGE_LOOP('',(#2187,#2188,#2196,#2202));
#2204=FACE_BOUND('',#2203,.T.);
#2205=ADVANCED_FACE('F2420',(#2204),#2186,.F.);
#2206=CARTESIAN_POINT('',(8.,18.9999999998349,61.0000000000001));
#2207=DIRECTION('',(0.,-0.0523359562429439,-0.998629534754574));
#2208=DIRECTION('',(0.,0.998629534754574,-0.0523359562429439));
#2209=AXIS2_PLACEMENT_3D('',#2206,#2207,#2208);
#2210=PLANE('',#2209);
#2211=ORIENTED_EDGE('',*,*,#1755,.T.);
#2212=ORIENTED_EDGE('',*,*,#2201,.F.);
#2213=DIRECTION('',(-1.,0.,0.));
#2214=VECTOR('',#2213,1.);
#2215=CARTESIAN_POINT('',(8.,14.9999999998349,61.2096311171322));
#2216=LINE('',#2215,#2214);
#2217=CARTESIAN_POINT('',(7.79036888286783,14.9999999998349,61.2096311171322));
#2218=VERTEX_POINT('',#2217);
#2219=EDGE_CURVE('E929',#2218,#2194,#2216,.T.);
#2220=ORIENTED_EDGE('',*,*,#2219,.F.);
#2221=DIRECTION('',(0.052264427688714,0.997264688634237,-0.052264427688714));
#2222=VECTOR('',#2221,1.);
#2223=CARTESIAN_POINT('',(7.97541586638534,18.5309067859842,61.0245841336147));
#2224=LINE('',#2223,#2222);
#2225=EDGE_CURVE('E922',#2218,#1732,#2224,.T.);
#2226=ORIENTED_EDGE('',*,*,#2225,.T.);
#2227=EDGE_LOOP('',(#2211,#2212,#2220,#2226));
#2228=FACE_BOUND('',#2227,.T.);
#2229=ADVANCED_FACE('F2429',(#2228),#2210,.F.);
#2230=CARTESIAN_POINT('',(8.,18.9999999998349,70.0000000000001));
#2231=DIRECTION('',(0.998629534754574,-0.0523359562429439,0.));
#2232=DIRECTION('',(0.0523359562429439,0.998629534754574,0.));
#2233=AXIS2_PLACEMENT_3D('',#2230,#2231,#2232);
#2234=PLANE('',#2233);
#2235=ORIENTED_EDGE('',*,*,#1733,.T.);
#2236=ORIENTED_EDGE('',*,*,#2225,.F.);
#2237=DIRECTION('',(0.,0.,-1.));
#2238=VECTOR('',#2237,1.);
#2239=CARTESIAN_POINT('',(7.79036888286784,14.9999999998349,70.0000000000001));
#2240=LINE('',#2239,#2238);
#2241=EDGE_CURVE('E927',#2162,#2218,#2240,.T.);
#2242=ORIENTED_EDGE('',*,*,#2241,.F.);
#2243=ORIENTED_EDGE('',*,*,#2163,.T.);
#2244=EDGE_LOOP('',(#2235,#2236,#2242,#2243));
#2245=FACE_BOUND('',#2244,.T.);
#2246=ADVANCED_FACE('F2439',(#2245),#2234,.F.);
#2247=CARTESIAN_POINT('',(-8.00000000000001,18.9999999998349,71.0000000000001));
#2248=DIRECTION('',(0.,-0.0523359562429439,0.998629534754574));
#2249=DIRECTION('',(0.,-0.998629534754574,-0.0523359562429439));
#2250=AXIS2_PLACEMENT_3D('',#2247,#2248,#2249);
#2251=PLANE('',#2250);
#2252=ORIENTED_EDGE('',*,*,#1809,.T.);
#2253=DIRECTION('',(0.052264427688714,0.997264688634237,0.052264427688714));
#2254=VECTOR('',#2253,1.);
#2255=CARTESIAN_POINT('',(-4.01092628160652,18.7915141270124,70.9890737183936));
#2256=LINE('',#2255,#2254);
#2257=CARTESIAN_POINT('',(-4.20963111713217,14.9999999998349,70.7903688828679));
#2258=VERTEX_POINT('',#2257);
#2259=EDGE_CURVE('E891',#2258,#1798,#2256,.T.);
#2260=ORIENTED_EDGE('',*,*,#2259,.F.);
#2261=DIRECTION('',(1.,0.,0.));
#2262=VECTOR('',#2261,1.);
#2263=CARTESIAN_POINT('',(-4.,14.9999999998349,70.7903688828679));
#2264=LINE('',#2263,#2262);
#2265=CARTESIAN_POINT('',(-7.79036888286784,14.9999999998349,70.7903688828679));
#2266=VERTEX_POINT('',#2265);
#2267=EDGE_CURVE('E886',#2266,#2258,#2264,.T.);
#2268=ORIENTED_EDGE('',*,*,#2267,.F.);
#2269=DIRECTION('',(-0.052264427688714,0.997264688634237,0.052264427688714));
#2270=VECTOR('',#2269,1.);
#2271=CARTESIAN_POINT('',(-7.97268429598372,18.4787853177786,70.9726842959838));
#2272=LINE('',#2271,#2270);
#2273=EDGE_CURVE('E887',#2266,#1808,#2272,.T.);
#2274=ORIENTED_EDGE('',*,*,#2273,.T.);
#2275=EDGE_LOOP('',(#2252,#2260,#2268,#2274));
#2276=FACE_BOUND('',#2275,.T.);
#2277=ADVANCED_FACE('F2449',(#2276),#2251,.F.);
#2278=CARTESIAN_POINT('',(-8.,18.9999999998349,61.0000000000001));
#2279=DIRECTION('',(-0.998629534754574,-0.0523359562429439,0.));
#2280=DIRECTION('',(0.0523359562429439,-0.998629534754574,0.));
#2281=AXIS2_PLACEMENT_3D('',#2278,#2279,#2280);
#2282=PLANE('',#2281);
#2283=ORIENTED_EDGE('',*,*,#1817,.T.);
#2284=ORIENTED_EDGE('',*,*,#2273,.F.);
#2285=DIRECTION('',(0.,0.,1.));
#2286=VECTOR('',#2285,1.);
#2287=CARTESIAN_POINT('',(-7.79036888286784,14.9999999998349,71.0000000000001));
#2288=LINE('',#2287,#2286);
#2289=CARTESIAN_POINT('',(-7.79036888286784,14.9999999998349,61.2096311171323));
#2290=VERTEX_POINT('',#2289);
#2291=EDGE_CURVE('E895',#2290,#2266,#2288,.T.);
#2292=ORIENTED_EDGE('',*,*,#2291,.F.);
#2293=DIRECTION('',(-0.052264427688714,0.997264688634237,-0.052264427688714));
#2294=VECTOR('',#2293,1.);
#2295=CARTESIAN_POINT('',(-7.98907371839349,18.7915141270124,61.0109262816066));
#2296=LINE('',#2295,#2294);
#2297=EDGE_CURVE('E890',#2290,#1816,#2296,.T.);
#2298=ORIENTED_EDGE('',*,*,#2297,.T.);
#2299=EDGE_LOOP('',(#2283,#2284,#2292,#2298));
#2300=FACE_BOUND('',#2299,.T.);
#2301=ADVANCED_FACE('F2459',(#2300),#2282,.F.);
#2302=CARTESIAN_POINT('',(-4.,18.9999999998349,61.0000000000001));
#2303=DIRECTION('',(0.,-0.0523359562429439,-0.998629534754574));
#2304=DIRECTION('',(0.,0.998629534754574,-0.0523359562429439));
#2305=AXIS2_PLACEMENT_3D('',#2302,#2303,#2304);
#2306=PLANE('',#2305);
#2307=ORIENTED_EDGE('',*,*,#1823,.T.);
#2308=ORIENTED_EDGE('',*,*,#2297,.F.);
#2309=DIRECTION('',(-1.,0.,0.));
#2310=VECTOR('',#2309,1.);
#2311=CARTESIAN_POINT('',(-4.,14.9999999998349,61.2096311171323));
#2312=LINE('',#2311,#2310);
#2313=CARTESIAN_POINT('',(-4.20963111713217,14.9999999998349,61.2096311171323));
#2314=VERTEX_POINT('',#2313);
#2315=EDGE_CURVE('E901',#2314,#2290,#2312,.T.);
#2316=ORIENTED_EDGE('',*,*,#2315,.F.);
#2317=DIRECTION('',(0.052264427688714,0.997264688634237,-0.052264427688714));
#2318=VECTOR('',#2317,1.);
#2319=CARTESIAN_POINT('',(-4.02731570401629,18.4787853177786,61.0273157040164));
#2320=LINE('',#2319,#2318);
#2321=EDGE_CURVE('E894',#2314,#1800,#2320,.T.);
#2322=ORIENTED_EDGE('',*,*,#2321,.T.);
#2323=EDGE_LOOP('',(#2307,#2308,#2316,#2322));
#2324=FACE_BOUND('',#2323,.T.);
#2325=ADVANCED_FACE('F2469',(#2324),#2306,.F.);
#2326=CARTESIAN_POINT('',(-4.,18.9999999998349,71.0000000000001));
#2327=DIRECTION('',(0.998629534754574,-0.0523359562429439,0.));
#2328=DIRECTION('',(0.0523359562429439,0.998629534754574,0.));
#2329=AXIS2_PLACEMENT_3D('',#2326,#2327,#2328);
#2330=PLANE('',#2329);
#2331=ORIENTED_EDGE('',*,*,#1801,.T.);
#2332=ORIENTED_EDGE('',*,*,#2321,.F.);
#2333=DIRECTION('',(0.,0.,-1.));
#2334=VECTOR('',#2333,1.);
#2335=CARTESIAN_POINT('',(-4.20963111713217,14.9999999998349,71.0000000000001));
#2336=LINE('',#2335,#2334);
#2337=EDGE_CURVE('E899',#2258,#2314,#2336,.T.);
#2338=ORIENTED_EDGE('',*,*,#2337,.F.);
#2339=ORIENTED_EDGE('',*,*,#2259,.T.);
#2340=EDGE_LOOP('',(#2331,#2332,#2338,#2339));
#2341=FACE_BOUND('',#2340,.T.);
#2342=ADVANCED_FACE('F2479',(#2341),#2330,.F.);
#2343=CARTESIAN_POINT('',(0.,18.9999999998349,77.5000000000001));
#2344=DIRECTION('',(0.,1.,0.));
#2345=DIRECTION('',(0.,0.,1.));
#2346=AXIS2_PLACEMENT_3D('',#2343,#2344,#2345);
#2347=CONICAL_SURFACE('',#2346,3.5,0.0523598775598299);
#2348=ORIENTED_EDGE('',*,*,#1701,.T.);
#2349=DIRECTION('',(-0.0523359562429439,0.998629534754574,0.));
#2350=VECTOR('',#2349,1.);
#2351=CARTESIAN_POINT('',(-3.5,18.9999999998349,77.5000000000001));
#2352=LINE('',#2351,#2350);
#2353=CARTESIAN_POINT('',(-3.29036888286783,14.9999999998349,77.5000000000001));
#2354=VERTEX_POINT('',#2353);
#2355=EDGE_CURVE('E862',#2354,#1689,#2352,.T.);
#2356=ORIENTED_EDGE('',*,*,#2355,.F.);
#2357=CARTESIAN_POINT('',(0.,14.9999999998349,77.5000000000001));
#2358=DIRECTION('',(0.,1.,0.));
#2359=DIRECTION('',(0.,0.,1.));
#2360=AXIS2_PLACEMENT_3D('',#2357,#2358,#2359);
#2361=CIRCLE('',#2360,3.29036888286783);
#2362=CARTESIAN_POINT('',(3.29036888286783,14.9999999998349,77.5000000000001));
#2363=VERTEX_POINT('',#2362);
#2364=EDGE_CURVE('E857',#2363,#2354,#2361,.T.);
#2365=ORIENTED_EDGE('',*,*,#2364,.F.);
#2366=DIRECTION('',(0.0523359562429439,0.998629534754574,0.));
#2367=VECTOR('',#2366,1.);
#2368=CARTESIAN_POINT('',(3.5,18.9999999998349,77.5000000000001));
#2369=LINE('',#2368,#2367);
#2370=EDGE_CURVE('E858',#2363,#1700,#2369,.T.);
#2371=ORIENTED_EDGE('',*,*,#2370,.T.);
#2372=EDGE_LOOP('',(#2348,#2356,#2365,#2371));
#2373=FACE_BOUND('',#2372,.T.);
#2374=ADVANCED_FACE('F2489',(#2373),#2347,.F.);
#2375=CARTESIAN_POINT('',(3.5,18.9999999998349,82.0000000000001));
#2376=DIRECTION('',(0.998629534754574,-0.0523359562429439,0.));
#2377=DIRECTION('',(0.0523359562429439,0.998629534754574,0.));
#2378=AXIS2_PLACEMENT_3D('',#2375,#2376,#2377);
#2379=PLANE('',#2378);
#2380=ORIENTED_EDGE('',*,*,#1709,.T.);
#2381=ORIENTED_EDGE('',*,*,#2370,.F.);
#2382=DIRECTION('',(0.,0.,-1.));
#2383=VECTOR('',#2382,1.);
#2384=CARTESIAN_POINT('',(3.29036888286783,14.9999999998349,77.5000000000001));
#2385=LINE('',#2384,#2383);
#2386=CARTESIAN_POINT('',(3.29036888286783,14.9999999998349,81.7903688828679));
#2387=VERTEX_POINT('',#2386);
#2388=EDGE_CURVE('E866',#2387,#2363,#2385,.T.);
#2389=ORIENTED_EDGE('',*,*,#2388,.F.);
#2390=DIRECTION('',(0.052264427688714,0.997264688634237,0.052264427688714));
#2391=VECTOR('',#2390,1.);
#2392=CARTESIAN_POINT('',(3.4808790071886,18.6351497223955,81.9808790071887));
#2393=LINE('',#2392,#2391);
#2394=EDGE_CURVE('E861',#2387,#1708,#2393,.T.);
#2395=ORIENTED_EDGE('',*,*,#2394,.T.);
#2396=EDGE_LOOP('',(#2380,#2381,#2389,#2395));
#2397=FACE_BOUND('',#2396,.T.);
#2398=ADVANCED_FACE('F2497',(#2397),#2379,.F.);
#2399=CARTESIAN_POINT('',(-3.5,18.9999999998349,82.0000000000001));
#2400=DIRECTION('',(0.,-0.0523359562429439,0.998629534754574));
#2401=DIRECTION('',(0.,-0.998629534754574,-0.0523359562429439));
#2402=AXIS2_PLACEMENT_3D('',#2399,#2400,#2401);
#2403=PLANE('',#2402);
#2404=ORIENTED_EDGE('',*,*,#2394,.F.);
#2405=DIRECTION('',(1.,0.,0.));
#2406=VECTOR('',#2405,1.);
#2407=CARTESIAN_POINT('',(0.,14.9999999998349,81.7903688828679));
#2408=LINE('',#2407,#2406);
#2409=CARTESIAN_POINT('',(-3.29036888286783,14.9999999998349,81.7903688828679));
#2410=VERTEX_POINT('',#2409);
#2411=EDGE_CURVE('E873',#2410,#2387,#2408,.T.);
#2412=ORIENTED_EDGE('',*,*,#2411,.F.);
#2413=DIRECTION('',(-0.052264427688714,0.997264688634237,0.052264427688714));
#2414=VECTOR('',#2413,1.);
#2415=CARTESIAN_POINT('',(-3.48770793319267,18.7654533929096,81.9877079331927));
#2416=LINE('',#2415,#2414);
#2417=EDGE_CURVE('E865',#2410,#1691,#2416,.T.);
#2418=ORIENTED_EDGE('',*,*,#2417,.T.);
#2419=ORIENTED_EDGE('',*,*,#1715,.T.);
#2420=EDGE_LOOP('',(#2404,#2412,#2418,#2419));
#2421=FACE_BOUND('',#2420,.T.);
#2422=ADVANCED_FACE('F2501',(#2421),#2403,.F.);
#2423=CARTESIAN_POINT('',(-3.5,18.9999999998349,77.5000000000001));
#2424=DIRECTION('',(-0.998629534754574,-0.0523359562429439,0.));
#2425=DIRECTION('',(0.0523359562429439,-0.998629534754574,0.));
#2426=AXIS2_PLACEMENT_3D('',#2423,#2424,#2425);
#2427=PLANE('',#2426);
#2428=ORIENTED_EDGE('',*,*,#1692,.T.);
#2429=ORIENTED_EDGE('',*,*,#2417,.F.);
#2430=DIRECTION('',(0.,0.,1.));
#2431=VECTOR('',#2430,1.);
#2432=CARTESIAN_POINT('',(-3.29036888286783,14.9999999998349,77.5000000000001));
#2433=LINE('',#2432,#2431);
#2434=EDGE_CURVE('E871',#2354,#2410,#2433,.T.);
#2435=ORIENTED_EDGE('',*,*,#2434,.F.);
#2436=ORIENTED_EDGE('',*,*,#2355,.T.);
#2437=EDGE_LOOP('',(#2428,#2429,#2435,#2436));
#2438=FACE_BOUND('',#2437,.T.);
#2439=ADVANCED_FACE('F2509',(#2438),#2427,.F.);
#2440=CARTESIAN_POINT('',(-9.,20.9999999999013,111.));
#2441=DIRECTION('',(-0.998629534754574,-0.0523359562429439,0.));
#2442=DIRECTION('',(0.0523359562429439,-0.998629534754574,0.));
#2443=AXIS2_PLACEMENT_3D('',#2440,#2441,#2442);
#2444=PLANE('',#2443);
#2445=ORIENTED_EDGE('',*,*,#876,.T.);
#2446=DIRECTION('',(-0.052264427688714,0.997264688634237,0.052264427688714));
#2447=VECTOR('',#2446,1.);
#2448=CARTESIAN_POINT('',(-9.,20.9999999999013,111.));
#2449=LINE('',#2448,#2447);
#2450=CARTESIAN_POINT('',(-8.63314554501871,13.9999999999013,110.633145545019));
#2451=VERTEX_POINT('',#2450);
#2452=EDGE_CURVE('E834',#2451,#875,#2449,.T.);
#2453=ORIENTED_EDGE('',*,*,#2452,.F.);
#2454=DIRECTION('',(0.,0.,1.));
#2455=VECTOR('',#2454,1.);
#2456=CARTESIAN_POINT('',(-8.63314554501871,13.9999999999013,111.));
#2457=LINE('',#2456,#2455);
#2458=CARTESIAN_POINT('',(-8.63314554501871,13.9999999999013,103.366854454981));
#2459=VERTEX_POINT('',#2458);
#2460=EDGE_CURVE('E828',#2459,#2451,#2457,.T.);
#2461=ORIENTED_EDGE('',*,*,#2460,.F.);
#2462=DIRECTION('',(-0.052264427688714,0.997264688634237,-0.052264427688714));
#2463=VECTOR('',#2462,1.);
#2464=CARTESIAN_POINT('',(-9.,20.9999999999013,103.));
#2465=LINE('',#2464,#2463);
#2466=EDGE_CURVE('E829',#2459,#873,#2465,.T.);
#2467=ORIENTED_EDGE('',*,*,#2466,.T.);
#2468=EDGE_LOOP('',(#2445,#2453,#2461,#2467));
#2469=FACE_BOUND('',#2468,.T.);
#2470=ADVANCED_FACE('F2078',(#2469),#2444,.F.);
#2471=CARTESIAN_POINT('',(-9.,20.9999999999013,103.));
#2472=DIRECTION('',(0.,-0.0523359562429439,-0.998629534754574));
#2473=DIRECTION('',(0.,0.998629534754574,-0.0523359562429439));
#2474=AXIS2_PLACEMENT_3D('',#2471,#2472,#2473);
#2475=PLANE('',#2474);
#2476=ORIENTED_EDGE('',*,*,#884,.T.);
#2477=ORIENTED_EDGE('',*,*,#2466,.F.);
#2478=DIRECTION('',(-1.,0.,0.));
#2479=VECTOR('',#2478,1.);
#2480=CARTESIAN_POINT('',(-9.,13.9999999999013,103.366854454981));
#2481=LINE('',#2480,#2479);
#2482=CARTESIAN_POINT('',(8.63314554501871,13.9999999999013,103.366854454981));
#2483=VERTEX_POINT('',#2482);
#2484=EDGE_CURVE('E838',#2483,#2459,#2481,.T.);
#2485=ORIENTED_EDGE('',*,*,#2484,.F.);
#2486=DIRECTION('',(0.052264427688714,0.997264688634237,-0.052264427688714));
#2487=VECTOR('',#2486,1.);
#2488=CARTESIAN_POINT('',(8.97814743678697,20.5830282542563,103.021852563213));
#2489=LINE('',#2488,#2487);
#2490=EDGE_CURVE('E833',#2483,#883,#2489,.T.);
#2491=ORIENTED_EDGE('',*,*,#2490,.T.);
#2492=EDGE_LOOP('',(#2476,#2477,#2485,#2491));
#2493=FACE_BOUND('',#2492,.T.);
#2494=ADVANCED_FACE('F2074',(#2493),#2475,.F.);
#2495=CARTESIAN_POINT('',(9.,20.9999999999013,111.));
#2496=DIRECTION('',(0.998629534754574,-0.0523359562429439,0.));
#2497=DIRECTION('',(0.0523359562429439,0.998629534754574,0.));
#2498=AXIS2_PLACEMENT_3D('',#2495,#2496,#2497);
#2499=PLANE('',#2498);
#2500=ORIENTED_EDGE('',*,*,#892,.T.);
#2501=ORIENTED_EDGE('',*,*,#2490,.F.);
#2502=DIRECTION('',(0.,0.,-1.));
#2503=VECTOR('',#2502,1.);
#2504=CARTESIAN_POINT('',(8.63314554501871,13.9999999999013,111.));
#2505=LINE('',#2504,#2503);
#2506=CARTESIAN_POINT('',(8.63314554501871,13.9999999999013,110.633145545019));
#2507=VERTEX_POINT('',#2506);
#2508=EDGE_CURVE('E845',#2507,#2483,#2505,.T.);
#2509=ORIENTED_EDGE('',*,*,#2508,.F.);
#2510=DIRECTION('',(0.052264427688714,0.997264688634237,0.052264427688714));
#2511=VECTOR('',#2510,1.);
#2512=CARTESIAN_POINT('',(8.95083173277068,20.0618135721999,110.950831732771));
#2513=LINE('',#2512,#2511);
#2514=EDGE_CURVE('E837',#2507,#891,#2513,.T.);
#2515=ORIENTED_EDGE('',*,*,#2514,.T.);
#2516=EDGE_LOOP('',(#2500,#2501,#2509,#2515));
#2517=FACE_BOUND('',#2516,.T.);
#2518=ADVANCED_FACE('F2085',(#2517),#2499,.F.);
#2519=CARTESIAN_POINT('',(-9.,20.9999999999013,111.));
#2520=DIRECTION('',(0.,-0.0523359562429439,0.998629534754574));
#2521=DIRECTION('',(0.,-0.998629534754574,-0.0523359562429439));
#2522=AXIS2_PLACEMENT_3D('',#2519,#2520,#2521);
#2523=PLANE('',#2522);
#2524=ORIENTED_EDGE('',*,*,#2514,.F.);
#2525=DIRECTION('',(1.,0.,0.));
#2526=VECTOR('',#2525,1.);
#2527=CARTESIAN_POINT('',(-9.,13.9999999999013,110.633145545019));
#2528=LINE('',#2527,#2526);
#2529=EDGE_CURVE('E843',#2451,#2507,#2528,.T.);
#2530=ORIENTED_EDGE('',*,*,#2529,.F.);
#2531=ORIENTED_EDGE('',*,*,#2452,.T.);
#2532=ORIENTED_EDGE('',*,*,#898,.T.);
#2533=EDGE_LOOP('',(#2524,#2530,#2531,#2532));
#2534=FACE_BOUND('',#2533,.T.);
#2535=ADVANCED_FACE('F1966',(#2534),#2523,.F.);
#2536=CARTESIAN_POINT('',(4.00000000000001,14.9999999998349,35.0000000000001));
#2537=DIRECTION('',(0.,-1.,0.));
#2538=DIRECTION('',(0.,0.,-1.));
#2539=AXIS2_PLACEMENT_3D('',#2536,#2537,#2538);
#2540=PLANE('',#2539);
#2541=DIRECTION('',(1.,0.,0.));
#2542=VECTOR('',#2541,1.);
#2543=CARTESIAN_POINT('',(4.00000000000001,14.9999999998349,36.2924274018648));
#2544=LINE('',#2543,#2542);
#2545=CARTESIAN_POINT('',(2.70757259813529,14.9999999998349,36.2924274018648));
#2546=VERTEX_POINT('',#2545);
#2547=CARTESIAN_POINT('',(9.29242740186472,14.9999999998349,36.2924274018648));
#2548=VERTEX_POINT('',#2547);
#2549=EDGE_CURVE('E1449',#2546,#2548,#2544,.T.);
#2550=ORIENTED_EDGE('',*,*,#2549,.F.);
#2551=DIRECTION('',(0.,0.,1.));
#2552=VECTOR('',#2551,1.);
#2553=CARTESIAN_POINT('',(2.70757259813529,14.9999999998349,26.0000000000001));
#2554=LINE('',#2553,#2552);
#2555=CARTESIAN_POINT('',(2.70757259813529,14.9999999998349,24.7075725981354));
#2556=VERTEX_POINT('',#2555);
#2557=EDGE_CURVE('E1456',#2556,#2546,#2554,.T.);
#2558=ORIENTED_EDGE('',*,*,#2557,.F.);
#2559=DIRECTION('',(-1.,0.,0.));
#2560=VECTOR('',#2559,1.);
#2561=CARTESIAN_POINT('',(8.00000000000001,14.9999999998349,24.7075725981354));
#2562=LINE('',#2561,#2560);
#2563=CARTESIAN_POINT('',(9.29242740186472,14.9999999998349,24.7075725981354));
#2564=VERTEX_POINT('',#2563);
#2565=EDGE_CURVE('E1547',#2564,#2556,#2562,.T.);
#2566=ORIENTED_EDGE('',*,*,#2565,.F.);
#2567=DIRECTION('',(0.,0.,-1.));
#2568=VECTOR('',#2567,1.);
#2569=CARTESIAN_POINT('',(9.29242740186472,14.9999999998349,35.0000000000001));
#2570=LINE('',#2569,#2568);
#2571=EDGE_CURVE('E1544',#2548,#2564,#2570,.T.);
#2572=ORIENTED_EDGE('',*,*,#2571,.F.);
#2573=EDGE_LOOP('',(#2550,#2558,#2566,#2572));
#2574=FACE_BOUND('',#2573,.T.);
#2575=ORIENTED_EDGE('',*,*,#1882,.T.);
#2576=ORIENTED_EDGE('',*,*,#1952,.T.);
#2577=ORIENTED_EDGE('',*,*,#1930,.T.);
#2578=ORIENTED_EDGE('',*,*,#1906,.T.);
#2579=EDGE_LOOP('',(#2575,#2576,#2577,#2578));
#2580=FACE_BOUND('',#2579,.T.);
#2581=ADVANCED_FACE('F1956',(#2574,#2580),#2540,.T.);
#2582=CARTESIAN_POINT('',(4.,14.9999999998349,70.0000000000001));
#2583=DIRECTION('',(0.,-1.,0.));
#2584=DIRECTION('',(0.,0.,-1.));
#2585=AXIS2_PLACEMENT_3D('',#2582,#2583,#2584);
#2586=PLANE('',#2585);
#2587=DIRECTION('',(1.,0.,0.));
#2588=VECTOR('',#2587,1.);
#2589=CARTESIAN_POINT('',(4.,14.9999999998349,71.2924274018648));
#2590=LINE('',#2589,#2588);
#2591=CARTESIAN_POINT('',(2.70757259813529,14.9999999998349,71.2924274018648));
#2592=VERTEX_POINT('',#2591);
#2593=CARTESIAN_POINT('',(9.29242740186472,14.9999999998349,71.2924274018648));
#2594=VERTEX_POINT('',#2593);
#2595=EDGE_CURVE('E1411',#2592,#2594,#2590,.T.);
#2596=ORIENTED_EDGE('',*,*,#2595,.F.);
#2597=DIRECTION('',(0.,0.,1.));
#2598=VECTOR('',#2597,1.);
#2599=CARTESIAN_POINT('',(2.70757259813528,14.9999999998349,61.0000000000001));
#2600=LINE('',#2599,#2598);
#2601=CARTESIAN_POINT('',(2.70757259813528,14.9999999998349,59.7075725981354));
#2602=VERTEX_POINT('',#2601);
#2603=EDGE_CURVE('E1486',#2602,#2592,#2600,.T.);
#2604=ORIENTED_EDGE('',*,*,#2603,.F.);
#2605=DIRECTION('',(-1.,0.,0.));
#2606=VECTOR('',#2605,1.);
#2607=CARTESIAN_POINT('',(8.,14.9999999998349,59.7075725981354));
#2608=LINE('',#2607,#2606);
#2609=CARTESIAN_POINT('',(9.29242740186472,14.9999999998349,59.7075725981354));
#2610=VERTEX_POINT('',#2609);
#2611=EDGE_CURVE('E1575',#2610,#2602,#2608,.T.);
#2612=ORIENTED_EDGE('',*,*,#2611,.F.);
#2613=DIRECTION('',(0.,0.,-1.));
#2614=VECTOR('',#2613,1.);
#2615=CARTESIAN_POINT('',(9.29242740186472,14.9999999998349,70.0000000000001));
#2616=LINE('',#2615,#2614);
#2617=EDGE_CURVE('E1572',#2594,#2610,#2616,.T.);
#2618=ORIENTED_EDGE('',*,*,#2617,.F.);
#2619=EDGE_LOOP('',(#2596,#2604,#2612,#2618));
#2620=FACE_BOUND('',#2619,.T.);
#2621=ORIENTED_EDGE('',*,*,#2171,.T.);
#2622=ORIENTED_EDGE('',*,*,#2241,.T.);
#2623=ORIENTED_EDGE('',*,*,#2219,.T.);
#2624=ORIENTED_EDGE('',*,*,#2195,.T.);
#2625=EDGE_LOOP('',(#2621,#2622,#2623,#2624));
#2626=FACE_BOUND('',#2625,.T.);
#2627=ADVANCED_FACE('F1953',(#2620,#2626),#2586,.T.);
#2628=CARTESIAN_POINT('',(-9.,13.9999999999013,103.));
#2629=DIRECTION('',(0.,-1.,0.));
#2630=DIRECTION('',(0.,0.,-1.));
#2631=AXIS2_PLACEMENT_3D('',#2628,#2629,#2630);
#2632=PLANE('',#2631);
#2633=ORIENTED_EDGE('',*,*,#2484,.T.);
#2634=ORIENTED_EDGE('',*,*,#2460,.T.);
#2635=ORIENTED_EDGE('',*,*,#2529,.T.);
#2636=ORIENTED_EDGE('',*,*,#2508,.T.);
#2637=EDGE_LOOP('',(#2633,#2634,#2635,#2636));
#2638=FACE_BOUND('',#2637,.T.);
#2639=DIRECTION('',(0.,0.,-1.));
#2640=VECTOR('',#2639,1.);
#2641=CARTESIAN_POINT('',(0.75,13.9999999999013,90.2476158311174));
#2642=LINE('',#2641,#2640);
#2643=CARTESIAN_POINT('',(0.749999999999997,13.9999999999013,87.9596311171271));
#2644=VERTEX_POINT('',#2643);
#2645=CARTESIAN_POINT('',(0.749999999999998,13.9999999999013,101.864795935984));
#2646=VERTEX_POINT('',#2645);
#2647=EDGE_CURVE('E1711',#2644,#2646,#2642,.F.);
#2648=ORIENTED_EDGE('',*,*,#2647,.T.);
#2649=CARTESIAN_POINT('',(10.1352040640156,13.9999999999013,101.864795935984));
#2650=VERTEX_POINT('',#2649);
#2651=EDGE_CURVE('E816',#2650,#2646,#301,.T.);
#2652=ORIENTED_EDGE('',*,*,#2651,.F.);
#2653=DIRECTION('',(0.,0.,-1.));
#2654=VECTOR('',#2653,1.);
#2655=CARTESIAN_POINT('',(10.1352040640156,13.9999999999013,111.));
#2656=LINE('',#2655,#2654);
#2657=CARTESIAN_POINT('',(10.1352040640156,13.9999999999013,112.135204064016));
#2658=VERTEX_POINT('',#2657);
#2659=EDGE_CURVE('E806',#2658,#2650,#2656,.T.);
#2660=ORIENTED_EDGE('',*,*,#2659,.F.);
#2661=CARTESIAN_POINT('',(0.75,13.9999999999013,112.135204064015));
#2662=VERTEX_POINT('',#2661);
#2663=EDGE_CURVE('E807',#2662,#2658,#199,.T.);
#2664=ORIENTED_EDGE('',*,*,#2663,.F.);
#2665=DIRECTION('',(0.,0.,-1.));
#2666=VECTOR('',#2665,1.);
#2667=CARTESIAN_POINT('',(0.75,13.9999999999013,112.075472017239));
#2668=LINE('',#2667,#2666);
#2669=CARTESIAN_POINT('',(0.750000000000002,13.9999999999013,123.219302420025));
#2670=VERTEX_POINT('',#2669);
#2671=EDGE_CURVE('E790',#2662,#2670,#2668,.F.);
#2672=ORIENTED_EDGE('',*,*,#2671,.T.);
#2673=DIRECTION('',(-1.,0.,0.));
#2674=VECTOR('',#2673,1.);
#2675=CARTESIAN_POINT('',(28.,13.9999999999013,123.219302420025));
#2676=LINE('',#2675,#2674);
#2677=CARTESIAN_POINT('',(-0.749999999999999,13.9999999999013,123.219302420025));
#2678=VERTEX_POINT('',#2677);
#2679=EDGE_CURVE('E801',#2678,#2670,#2676,.F.);
#2680=ORIENTED_EDGE('',*,*,#2679,.F.);
#2681=DIRECTION('',(0.,0.,1.));
#2682=VECTOR('',#2681,1.);
#2683=CARTESIAN_POINT('',(-0.75,13.9999999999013,66.4999999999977));
#2684=LINE('',#2683,#2682);
#2685=EDGE_CURVE('E782',#203,#2678,#2684,.T.);
#2686=ORIENTED_EDGE('',*,*,#2685,.F.);
#2687=ORIENTED_EDGE('',*,*,#204,.F.);
#2688=DIRECTION('',(0.,0.,1.));
#2689=VECTOR('',#2688,1.);
#2690=CARTESIAN_POINT('',(-10.1352040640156,13.9999999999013,111.));
#2691=LINE('',#2690,#2689);
#2692=EDGE_CURVE('E812',#303,#201,#2691,.T.);
#2693=ORIENTED_EDGE('',*,*,#2692,.F.);
#2694=ORIENTED_EDGE('',*,*,#304,.F.);
#2695=DIRECTION('',(0.,0.,1.));
#2696=VECTOR('',#2695,1.);
#2697=CARTESIAN_POINT('',(-0.75,13.9999999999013,66.4999999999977));
#2698=LINE('',#2697,#2696);
#2699=CARTESIAN_POINT('',(-0.750000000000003,13.9999999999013,87.9596311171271));
#2700=VERTEX_POINT('',#2699);
#2701=EDGE_CURVE('E1710',#2700,#295,#2698,.T.);
#2702=ORIENTED_EDGE('',*,*,#2701,.F.);
#2703=DIRECTION('',(1.,0.,0.));
#2704=VECTOR('',#2703,1.);
#2705=CARTESIAN_POINT('',(-19.9327032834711,13.9999999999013,87.9596311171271));
#2706=LINE('',#2705,#2704);
#2707=EDGE_CURVE('E1740',#2644,#2700,#2706,.F.);
#2708=ORIENTED_EDGE('',*,*,#2707,.F.);
#2709=EDGE_LOOP('',(#2648,#2652,#2660,#2664,#2672,#2680,#2686,#2687,#2693,#2694,#2702,#2708));
#2710=FACE_BOUND('',#2709,.T.);
#2711=ADVANCED_FACE('F795',(#2638,#2710),#2632,.T.);
#2712=CARTESIAN_POINT('',(26.1352012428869,6.9214960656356,130.));
#2713=DIRECTION('',(-0.998629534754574,-0.0523359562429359,0.));
#2714=DIRECTION('',(0.052335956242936,-0.998629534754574,0.));
#2715=AXIS2_PLACEMENT_3D('',#2712,#2713,#2714);
#2716=PLANE('',#2715);
#2717=ORIENTED_EDGE('',*,*,#1035,.F.);
#2718=DIRECTION('',(0.0523359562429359,-0.998629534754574,0.));
#2719=VECTOR('',#2718,1.);
#2720=CARTESIAN_POINT('',(26.5020556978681,-0.0785039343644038,115.519302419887));
#2721=LINE('',#2720,#2719);
#2722=CARTESIAN_POINT('',(26.158378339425,6.4792507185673,115.519302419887));
#2723=VERTEX_POINT('',#2722);
#2724=EDGE_CURVE('E1299',#2723,#1026,#2721,.T.);
#2725=ORIENTED_EDGE('',*,*,#2724,.F.);
#2726=DIRECTION('',(0.,0.,-1.));
#2727=VECTOR('',#2726,1.);
#2728=CARTESIAN_POINT('',(26.158378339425,6.4792507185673,130.));
#2729=LINE('',#2728,#2727);
#2730=CARTESIAN_POINT('',(26.158378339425,6.4792507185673,14.4806975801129));
#2731=VERTEX_POINT('',#2730);
#2732=EDGE_CURVE('E1231',#2723,#2731,#2729,.T.);
#2733=ORIENTED_EDGE('',*,*,#2732,.T.);
#2734=DIRECTION('',(0.0523359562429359,-0.998629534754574,0.));
#2735=VECTOR('',#2734,1.);
#2736=CARTESIAN_POINT('',(26.1352012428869,6.9214960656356,14.4806975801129));
#2737=LINE('',#2736,#2735);
#2738=EDGE_CURVE('E821',#1034,#2731,#2737,.F.);
#2739=ORIENTED_EDGE('',*,*,#2738,.F.);
#2740=EDGE_LOOP('',(#2717,#2725,#2733,#2739));
#2741=FACE_BOUND('',#2740,.T.);
#2742=ADVANCED_FACE('F1968',(#2741),#2716,.T.);
#2743=CARTESIAN_POINT('',(16.2848895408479,20.1205077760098,130.));
#2744=DIRECTION('',(-0.810073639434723,-0.586328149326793,0.));
#2745=DIRECTION('',(0.586328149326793,-0.810073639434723,0.));
#2746=AXIS2_PLACEMENT_3D('',#2743,#2744,#2745);
#2747=PLANE('',#2746);
#2748=ORIENTED_EDGE('',*,*,#41,.F.);
#2749=DIRECTION('',(-0.585800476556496,0.809344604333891,-0.0424159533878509));
#2750=VECTOR('',#2749,1.);
#2751=CARTESIAN_POINT('',(17.3851371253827,18.6004007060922,85.7992720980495));
#2752=LINE('',#2751,#2750);
#2753=EDGE_CURVE('E1190',#29,#320,#2752,.T.);
#2754=ORIENTED_EDGE('',*,*,#2753,.T.);
#2755=ORIENTED_EDGE('',*,*,#323,.T.);
#2756=DIRECTION('',(0.585800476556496,-0.809344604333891,-0.0424159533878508));
#2757=VECTOR('',#2756,1.);
#2758=CARTESIAN_POINT('',(14.3786155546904,22.7542245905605,53.4184205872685));
#2759=LINE('',#2758,#2757);
#2760=EDGE_CURVE('E1175',#82,#322,#2759,.F.);
#2761=ORIENTED_EDGE('',*,*,#2760,.F.);
#2762=ORIENTED_EDGE('',*,*,#83,.F.);
#2763=DIRECTION('',(-0.585800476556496,0.809344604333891,-0.042415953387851));
#2764=VECTOR('',#2763,1.);
#2765=CARTESIAN_POINT('',(18.2547921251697,17.3988814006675,50.8622410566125));
#2766=LINE('',#2765,#2764);
#2767=EDGE_CURVE('E1178',#71,#582,#2766,.T.);
#2768=ORIENTED_EDGE('',*,*,#2767,.T.);
#2769=ORIENTED_EDGE('',*,*,#583,.T.);
#2770=DIRECTION('',(0.586328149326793,-0.810073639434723,0.));
#2771=VECTOR('',#2770,1.);
#2772=CARTESIAN_POINT('',(16.2848895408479,20.1205077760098,14.4806975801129));
#2773=LINE('',#2772,#2771);
#2774=EDGE_CURVE('E1662',#2731,#578,#2773,.F.);
#2775=ORIENTED_EDGE('',*,*,#2774,.F.);
#2776=ORIENTED_EDGE('',*,*,#2732,.F.);
#2777=DIRECTION('',(0.586328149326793,-0.810073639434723,0.));
#2778=VECTOR('',#2777,1.);
#2779=CARTESIAN_POINT('',(29.868935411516,1.35272818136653,115.519302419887));
#2780=LINE('',#2779,#2778);
#2781=CARTESIAN_POINT('',(16.734010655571,19.5,115.519302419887));
#2782=VERTEX_POINT('',#2781);
#2783=EDGE_CURVE('E1227',#2782,#2723,#2780,.T.);
#2784=ORIENTED_EDGE('',*,*,#2783,.F.);
#2785=CARTESIAN_POINT('',(16.734010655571,19.5,88.247873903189));
#2786=VERTEX_POINT('',#2785);
#2787=EDGE_CURVE('E1225',#2782,#2786,#318,.T.);
#2788=ORIENTED_EDGE('',*,*,#2787,.T.);
#2789=DIRECTION('',(0.585800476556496,-0.809344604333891,-0.0424159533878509));
#2790=VECTOR('',#2789,1.);
#2791=CARTESIAN_POINT('',(15.2482705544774,21.5527052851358,88.3554516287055));
#2792=LINE('',#2791,#2790);
#2793=EDGE_CURVE('E1187',#40,#2786,#2792,.F.);
#2794=ORIENTED_EDGE('',*,*,#2793,.F.);
#2795=EDGE_LOOP('',(#2748,#2754,#2755,#2761,#2762,#2768,#2769,#2775,#2776,#2784,#2788,#2794));
#2796=FACE_BOUND('',#2795,.T.);
#2797=ADVANCED_FACE('F1222',(#2796),#2747,.T.);
#2798=DIRECTION('',(0.,0.,1.));
#2799=VECTOR('',#2798,1.);
#2800=CARTESIAN_POINT('',(1.03824278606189,19.5,130.));
#2801=LINE('',#2800,#2799);
#2802=CARTESIAN_POINT('',(1.0382427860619,19.5,112.423446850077));
#2803=VERTEX_POINT('',#2802);
#2804=CARTESIAN_POINT('',(1.03824278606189,19.5,115.519302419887));
#2805=VERTEX_POINT('',#2804);
#2806=EDGE_CURVE('E1706',#2803,#2805,#2801,.T.);
#2807=ORIENTED_EDGE('',*,*,#2806,.F.);
#2808=CARTESIAN_POINT('',(10.4234468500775,19.5,112.423446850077));
#2809=VERTEX_POINT('',#2808);
#2810=EDGE_CURVE('E1655',#2803,#2809,#111,.T.);
#2811=ORIENTED_EDGE('',*,*,#2810,.T.);
#2812=DIRECTION('',(0.,0.,-1.));
#2813=VECTOR('',#2812,1.);
#2814=CARTESIAN_POINT('',(10.4234468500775,19.5,111.));
#2815=LINE('',#2814,#2813);
#2816=CARTESIAN_POINT('',(10.4234468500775,19.5,101.576553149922));
#2817=VERTEX_POINT('',#2816);
#2818=EDGE_CURVE('E1684',#2809,#2817,#2815,.T.);
#2819=ORIENTED_EDGE('',*,*,#2818,.T.);
#2820=CARTESIAN_POINT('',(1.0382427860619,19.5,101.576553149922));
#2821=VERTEX_POINT('',#2820);
#2822=EDGE_CURVE('E1689',#2817,#2821,#177,.T.);
#2823=ORIENTED_EDGE('',*,*,#2822,.T.);
#2824=DIRECTION('',(0.,0.,1.));
#2825=VECTOR('',#2824,1.);
#2826=CARTESIAN_POINT('',(1.03824278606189,19.5,130.));
#2827=LINE('',#2826,#2825);
#2828=CARTESIAN_POINT('',(1.0382427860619,19.5,95.4234468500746));
#2829=VERTEX_POINT('',#2828);
#2830=EDGE_CURVE('E1734',#2829,#2821,#2827,.T.);
#2831=ORIENTED_EDGE('',*,*,#2830,.F.);
#2832=CARTESIAN_POINT('',(13.9234468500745,19.5,95.4234468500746));
#2833=VERTEX_POINT('',#2832);
#2834=EDGE_CURVE('E1673',#2829,#2833,#161,.T.);
#2835=ORIENTED_EDGE('',*,*,#2834,.T.);
#2836=CARTESIAN_POINT('',(13.9234468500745,19.5,88.247873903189));
#2837=VERTEX_POINT('',#2836);
#2838=EDGE_CURVE('E1679',#2833,#2837,#336,.T.);
#2839=ORIENTED_EDGE('',*,*,#2838,.T.);
#2840=EDGE_CURVE('E1757',#2786,#2837,#145,.F.);
#2841=ORIENTED_EDGE('',*,*,#2840,.F.);
#2842=ORIENTED_EDGE('',*,*,#2787,.F.);
#2843=EDGE_CURVE('E1692',#2805,#2782,#129,.T.);
#2844=ORIENTED_EDGE('',*,*,#2843,.F.);
#2845=EDGE_LOOP('',(#2807,#2811,#2819,#2823,#2831,#2835,#2839,#2841,#2842,#2844));
#2846=FACE_BOUND('',#2845,.T.);
#2847=ADVANCED_FACE('F1974',(#2846),#107,.T.);
#2848=CARTESIAN_POINT('',(-26.4180350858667,6.12050777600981,130.));
#2849=DIRECTION('',(0.810073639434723,-0.586328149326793,0.));
#2850=DIRECTION('',(0.586328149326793,0.810073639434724,0.));
#2851=AXIS2_PLACEMENT_3D('',#2848,#2849,#2850);
#2852=PLANE('',#2851);
#2853=ORIENTED_EDGE('',*,*,#56,.F.);
#2854=DIRECTION('',(0.585800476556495,0.809344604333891,0.0424159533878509));
#2855=VECTOR('',#2854,1.);
#2856=CARTESIAN_POINT('',(-25.3631854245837,7.57789286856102,87.6230627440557));
#2857=LINE('',#2856,#2855);
#2858=EDGE_CURVE('E1192',#48,#139,#2857,.T.);
#2859=ORIENTED_EDGE('',*,*,#2858,.T.);
#2860=ORIENTED_EDGE('',*,*,#140,.F.);
#2861=DIRECTION('',(0.586328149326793,0.810073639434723,0.));
#2862=VECTOR('',#2861,1.);
#2863=CARTESIAN_POINT('',(-10.6172162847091,27.9509909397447,115.519302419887));
#2864=LINE('',#2863,#2862);
#2865=CARTESIAN_POINT('',(-26.158378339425,6.47925071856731,115.519302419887));
#2866=VERTEX_POINT('',#2865);
#2867=EDGE_CURVE('E1276',#2866,#131,#2864,.T.);
#2868=ORIENTED_EDGE('',*,*,#2867,.F.);
#2869=DIRECTION('',(0.,0.,-1.));
#2870=VECTOR('',#2869,1.);
#2871=CARTESIAN_POINT('',(-26.158378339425,6.47925071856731,130.));
#2872=LINE('',#2871,#2870);
#2873=CARTESIAN_POINT('',(-26.158378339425,6.47925071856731,14.4806975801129));
#2874=VERTEX_POINT('',#2873);
#2875=EDGE_CURVE('E1257',#2866,#2874,#2872,.T.);
#2876=ORIENTED_EDGE('',*,*,#2875,.T.);
#2877=DIRECTION('',(0.586328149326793,0.810073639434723,0.));
#2878=VECTOR('',#2877,1.);
#2879=CARTESIAN_POINT('',(-26.4180350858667,6.12050777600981,14.4806975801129));
#2880=LINE('',#2879,#2878);
#2881=EDGE_CURVE('E1275',#570,#2874,#2880,.F.);
#2882=ORIENTED_EDGE('',*,*,#2881,.F.);
#2883=ORIENTED_EDGE('',*,*,#571,.F.);
#2884=DIRECTION('',(-0.585800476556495,-0.809344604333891,0.0424159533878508));
#2885=VECTOR('',#2884,1.);
#2886=CARTESIAN_POINT('',(-28.369706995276,3.4240689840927,51.5946299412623));
#2887=LINE('',#2886,#2885);
#2888=EDGE_CURVE('E1182',#73,#566,#2887,.F.);
#2889=ORIENTED_EDGE('',*,*,#2888,.F.);
#2890=ORIENTED_EDGE('',*,*,#98,.F.);
#2891=DIRECTION('',(0.585800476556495,0.809344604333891,0.042415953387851));
#2892=VECTOR('',#2891,1.);
#2893=CARTESIAN_POINT('',(-24.4935304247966,8.77941217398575,52.6860317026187));
#2894=LINE('',#2893,#2892);
#2895=EDGE_CURVE('E1180',#90,#361,#2894,.T.);
#2896=ORIENTED_EDGE('',*,*,#2895,.T.);
#2897=ORIENTED_EDGE('',*,*,#362,.F.);
#2898=DIRECTION('',(-0.585800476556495,-0.809344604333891,0.0424159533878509));
#2899=VECTOR('',#2898,1.);
#2900=CARTESIAN_POINT('',(-27.500051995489,4.62558828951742,86.5316609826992));
#2901=LINE('',#2900,#2899);
#2902=EDGE_CURVE('E1194',#31,#357,#2901,.F.);
#2903=ORIENTED_EDGE('',*,*,#2902,.F.);
#2904=EDGE_LOOP('',(#2853,#2859,#2860,#2868,#2876,#2882,#2883,#2889,#2890,#2896,#2897,#2903));
#2905=FACE_BOUND('',#2904,.T.);
#2906=ADVANCED_FACE('F1792',(#2905),#2852,.T.);
#2907=CARTESIAN_POINT('',(-26.1352012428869,6.9214960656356,130.));
#2908=DIRECTION('',(0.998629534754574,-0.0523359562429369,0.));
#2909=DIRECTION('',(0.0523359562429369,0.998629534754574,0.));
#2910=AXIS2_PLACEMENT_3D('',#2907,#2908,#2909);
#2911=PLANE('',#2910);
#2912=ORIENTED_EDGE('',*,*,#2875,.F.);
#2913=DIRECTION('',(0.0523359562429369,0.998629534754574,0.));
#2914=VECTOR('',#2913,1.);
#2915=CARTESIAN_POINT('',(-26.3486687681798,2.84829303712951,115.519302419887));
#2916=LINE('',#2915,#2914);
#2917=EDGE_CURVE('E1278',#1066,#2866,#2916,.T.);
#2918=ORIENTED_EDGE('',*,*,#2917,.F.);
#2919=ORIENTED_EDGE('',*,*,#1067,.T.);
#2920=DIRECTION('',(0.0523359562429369,0.998629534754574,0.));
#2921=VECTOR('',#2920,1.);
#2922=CARTESIAN_POINT('',(-26.1352012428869,6.9214960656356,14.4806975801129));
#2923=LINE('',#2922,#2921);
#2924=EDGE_CURVE('E1280',#2874,#1058,#2923,.F.);
#2925=ORIENTED_EDGE('',*,*,#2924,.F.);
#2926=EDGE_LOOP('',(#2912,#2918,#2919,#2925));
#2927=FACE_BOUND('',#2926,.T.);
#2928=ADVANCED_FACE('F1979',(#2927),#2911,.T.);
#2929=CARTESIAN_POINT('',(-28.,-0.0523492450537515,128.500913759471));
#2930=DIRECTION('',(0.,0.034899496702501,0.999390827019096));
#2931=DIRECTION('',(0.,-0.999390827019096,0.034899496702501));
#2932=AXIS2_PLACEMENT_3D('',#2929,#2930,#2931);
#2933=PLANE('',#2932);
#2934=DIRECTION('',(-0.0523041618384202,0.998022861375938,-0.0348517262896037));
#2935=VECTOR('',#2934,1.);
#2936=CARTESIAN_POINT('',(10.6205603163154,-0.234963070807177,128.507290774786));
#2937=LINE('',#2936,#2935);
#2938=CARTESIAN_POINT('',(10.4965738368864,2.13083989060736,128.424675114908));
#2939=VERTEX_POINT('',#2938);
#2940=EDGE_CURVE('E1291',#1010,#2939,#2937,.T.);
#2941=ORIENTED_EDGE('',*,*,#2940,.T.);
#2942=CARTESIAN_POINT('',(8.,2.,128.429244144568));
#2943=DIRECTION('',(0.,0.034899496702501,0.999390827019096));
#2944=DIRECTION('',(0.,0.999390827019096,-0.034899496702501));
#2945=AXIS2_PLACEMENT_3D('',#2942,#2943,#2944);
#2946=ELLIPSE('',#2945,2.50152386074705,2.49999999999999);
#2947=CARTESIAN_POINT('',(5.50342616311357,2.13083989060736,128.424675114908));
#2948=VERTEX_POINT('',#2947);
#2949=EDGE_CURVE('E1306',#2939,#2948,#2946,.T.);
#2950=ORIENTED_EDGE('',*,*,#2949,.T.);
#2951=DIRECTION('',(-0.0523041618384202,-0.998022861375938,0.0348517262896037));
#2952=VECTOR('',#2951,1.);
#2953=CARTESIAN_POINT('',(5.37943968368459,-0.234963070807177,128.507290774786));
#2954=LINE('',#2953,#2952);
#2955=EDGE_CURVE('E1295',#2948,#1082,#2954,.T.);
#2956=ORIENTED_EDGE('',*,*,#2955,.T.);
#2957=ORIENTED_EDGE('',*,*,#1083,.F.);
#2958=DIRECTION('',(-0.0274031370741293,-0.999015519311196,0.034886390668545));
#2959=VECTOR('',#2958,1.);
#2960=CARTESIAN_POINT('',(-17.2234787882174,-0.347590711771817,128.511223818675));
#2961=LINE('',#2960,#2959);
#2962=CARTESIAN_POINT('',(-17.1237249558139,3.28905958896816,128.384229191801));
#2963=VERTEX_POINT('',#2962);
#2964=EDGE_CURVE('E1236',#2963,#1074,#2961,.T.);
#2965=ORIENTED_EDGE('',*,*,#2964,.F.);
#2966=DIRECTION('',(-0.569362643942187,-0.821585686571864,0.0286904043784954));
#2967=VECTOR('',#2966,1.);
#2968=CARTESIAN_POINT('',(-22.2144795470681,-4.05685807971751,128.640754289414));
#2969=LINE('',#2968,#2967);
#2970=CARTESIAN_POINT('',(-12.1331683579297,10.4903923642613,128.132753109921));
#2971=VERTEX_POINT('',#2970);
#2972=EDGE_CURVE('E1285',#2971,#2963,#2969,.T.);
#2973=ORIENTED_EDGE('',*,*,#2972,.F.);
#2974=DIRECTION('',(-1.,0.,0.));
#2975=VECTOR('',#2974,1.);
#2976=CARTESIAN_POINT('',(-28.,10.4903923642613,128.132753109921));
#2977=LINE('',#2976,#2975);
#2978=CARTESIAN_POINT('',(12.1331683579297,10.4903923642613,128.132753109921));
#2979=VERTEX_POINT('',#2978);
#2980=EDGE_CURVE('E1302',#2979,#2971,#2977,.T.);
#2981=ORIENTED_EDGE('',*,*,#2980,.F.);
#2982=DIRECTION('',(-0.569362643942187,0.821585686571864,-0.0286904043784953));
#2983=VECTOR('',#2982,1.);
#2984=CARTESIAN_POINT('',(4.06074560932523,22.1388330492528,127.725980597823));
#2985=LINE('',#2984,#2983);
#2986=CARTESIAN_POINT('',(17.1237249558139,3.28905958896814,128.384229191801));
#2987=VERTEX_POINT('',#2986);
#2988=EDGE_CURVE('E1300',#2987,#2979,#2985,.T.);
#2989=ORIENTED_EDGE('',*,*,#2988,.F.);
#2990=DIRECTION('',(-0.0274031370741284,0.999015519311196,-0.034886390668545));
#2991=VECTOR('',#2990,1.);
#2992=CARTESIAN_POINT('',(17.1814266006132,1.1854742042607,128.457688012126));
#2993=LINE('',#2992,#2991);
#2994=EDGE_CURVE('E1296',#1018,#2987,#2993,.T.);
#2995=ORIENTED_EDGE('',*,*,#2994,.F.);
#2996=ORIENTED_EDGE('',*,*,#1019,.F.);
#2997=EDGE_LOOP('',(#2941,#2950,#2956,#2957,#2965,#2973,#2981,#2989,#2995,#2996));
#2998=FACE_BOUND('',#2997,.T.);
#2999=ADVANCED_FACE('F1982',(#2998),#2933,.F.);
#3000=CARTESIAN_POINT('',(-28.,-0.0523492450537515,1.49908624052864));
#3001=DIRECTION('',(0.,0.034899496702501,-0.999390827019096));
#3002=DIRECTION('',(0.,0.999390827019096,0.034899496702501));
#3003=AXIS2_PLACEMENT_3D('',#3000,#3001,#3002);
#3004=PLANE('',#3003);
#3005=ORIENTED_EDGE('',*,*,#1051,.T.);
#3006=DIRECTION('',(0.0274031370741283,-0.999015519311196,-0.034886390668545));
#3007=VECTOR('',#3006,1.);
#3008=CARTESIAN_POINT('',(17.0181862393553,7.13660504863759,1.75013005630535));
#3009=LINE('',#3008,#3007);
#3010=CARTESIAN_POINT('',(17.1237249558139,3.28905958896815,1.61577080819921));
#3011=VERTEX_POINT('',#3010);
#3012=EDGE_CURVE('E1342',#3011,#1042,#3009,.T.);
#3013=ORIENTED_EDGE('',*,*,#3012,.F.);
#3014=DIRECTION('',(0.569362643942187,-0.821585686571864,-0.0286904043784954));
#3015=VECTOR('',#3014,1.);
#3016=CARTESIAN_POINT('',(8.75857683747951,15.35990061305,2.03729386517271));
#3017=LINE('',#3016,#3015);
#3018=CARTESIAN_POINT('',(12.1331683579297,10.4903923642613,1.86724689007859));
#3019=VERTEX_POINT('',#3018);
#3020=EDGE_CURVE('E1340',#3019,#3011,#3017,.T.);
#3021=ORIENTED_EDGE('',*,*,#3020,.F.);
#3022=DIRECTION('',(1.,0.,0.));
#3023=VECTOR('',#3022,1.);
#3024=CARTESIAN_POINT('',(-17.5,10.4903923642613,1.86724689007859));
#3025=LINE('',#3024,#3023);
#3026=CARTESIAN_POINT('',(-12.1331683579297,10.4903923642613,1.86724689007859));
#3027=VERTEX_POINT('',#3026);
#3028=EDGE_CURVE('E1335',#3027,#3019,#3025,.T.);
#3029=ORIENTED_EDGE('',*,*,#3028,.F.);
#3030=DIRECTION('',(0.569362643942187,0.821585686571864,0.0286904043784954));
#3031=VECTOR('',#3030,1.);
#3032=CARTESIAN_POINT('',(-18.5924001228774,1.16977321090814,1.54176369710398));
#3033=LINE('',#3032,#3031);
#3034=CARTESIAN_POINT('',(-17.1237249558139,3.28905958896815,1.61577080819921));
#3035=VERTEX_POINT('',#3034);
#3036=EDGE_CURVE('E1332',#3035,#3027,#3033,.T.);
#3037=ORIENTED_EDGE('',*,*,#3036,.F.);
#3038=DIRECTION('',(0.0274031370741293,0.999015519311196,0.034886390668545));
#3039=VECTOR('',#3038,1.);
#3040=CARTESIAN_POINT('',(-17.0181862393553,7.13660504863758,1.75013005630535));
#3041=LINE('',#3040,#3039);
#3042=EDGE_CURVE('E1334',#1050,#3035,#3041,.T.);
#3043=ORIENTED_EDGE('',*,*,#3042,.F.);
#3044=EDGE_LOOP('',(#3005,#3013,#3021,#3029,#3037,#3043));
#3045=FACE_BOUND('',#3044,.T.);
#3046=ADVANCED_FACE('F1802',(#3045),#3004,.F.);
#3047=CARTESIAN_POINT('',(-16.6413903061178,2.33955613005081,129.128142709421));
#3048=DIRECTION('',(-0.812618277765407,0.0425875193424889,0.581238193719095));
#3049=DIRECTION('',(0.581766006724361,0.,0.813356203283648));
#3050=AXIS2_PLACEMENT_3D('',#3047,#3048,#3049);
#3051=PLANE('',#3050);
#3052=ORIENTED_EDGE('',*,*,#1075,.T.);
#3053=ORIENTED_EDGE('',*,*,#2917,.T.);
#3054=DIRECTION('',(0.563228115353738,-0.198879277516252,0.802010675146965));
#3055=VECTOR('',#3054,1.);
#3056=CARTESIAN_POINT('',(-14.349760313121,2.30955578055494,132.334225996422));
#3057=LINE('',#3056,#3055);
#3058=EDGE_CURVE('E1286',#2866,#2963,#3057,.T.);
#3059=ORIENTED_EDGE('',*,*,#3058,.T.);
#3060=ORIENTED_EDGE('',*,*,#2964,.T.);
#3061=EDGE_LOOP('',(#3052,#3053,#3059,#3060));
#3062=FACE_BOUND('',#3061,.T.);
#3063=ADVANCED_FACE('F1989',(#3062),#3051,.F.);
#3064=CARTESIAN_POINT('',(-2.74281429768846,22.25152941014,129.128142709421));
#3065=DIRECTION('',(-0.659184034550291,0.477114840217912,0.581238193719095));
#3066=DIRECTION('',(0.661369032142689,0.,0.750060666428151));
#3067=AXIS2_PLACEMENT_3D('',#3064,#3065,#3066);
#3068=PLANE('',#3067);
#3069=ORIENTED_EDGE('',*,*,#3058,.F.);
#3070=ORIENTED_EDGE('',*,*,#2867,.T.);
#3071=DIRECTION('',(0.284545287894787,-0.557211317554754,0.780095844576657));
#3072=VECTOR('',#3071,1.);
#3073=CARTESIAN_POINT('',(-8.55006700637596,3.47377775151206,137.95601356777));
#3074=LINE('',#3073,#3072);
#3075=EDGE_CURVE('E1290',#131,#2971,#3074,.T.);
#3076=ORIENTED_EDGE('',*,*,#3075,.T.);
#3077=ORIENTED_EDGE('',*,*,#2972,.T.);
#3078=EDGE_LOOP('',(#3069,#3070,#3076,#3077));
#3079=FACE_BOUND('',#3078,.T.);
#3080=ADVANCED_FACE('F1992',(#3079),#3068,.F.);
#3081=CARTESIAN_POINT('',(28.,9.77939979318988,129.128142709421));
#3082=DIRECTION('',(0.,0.813733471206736,0.581238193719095));
#3083=DIRECTION('',(0.,-0.581238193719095,0.813733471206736));
#3084=AXIS2_PLACEMENT_3D('',#3081,#3082,#3083);
#3085=PLANE('',#3084);
#3086=ORIENTED_EDGE('',*,*,#2679,.T.);
#3087=DIRECTION('',(0.0304472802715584,0.580968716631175,-0.813356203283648));
#3088=VECTOR('',#3087,1.);
#3089=CARTESIAN_POINT('',(0.554274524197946,10.2653354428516,128.447832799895));
#3090=LINE('',#3089,#3088);
#3091=EDGE_CURVE('E1708',#2670,#2805,#3090,.T.);
#3092=ORIENTED_EDGE('',*,*,#3091,.T.);
#3093=ORIENTED_EDGE('',*,*,#2843,.T.);
#3094=DIRECTION('',(-0.284545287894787,-0.557211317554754,0.780095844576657));
#3095=VECTOR('',#3094,1.);
#3096=CARTESIAN_POINT('',(10.3582008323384,7.01455904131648,132.998919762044));
#3097=LINE('',#3096,#3095);
#3098=EDGE_CURVE('E1312',#2782,#2979,#3097,.T.);
#3099=ORIENTED_EDGE('',*,*,#3098,.T.);
#3100=ORIENTED_EDGE('',*,*,#2980,.T.);
#3101=ORIENTED_EDGE('',*,*,#3075,.F.);
#3102=ORIENTED_EDGE('',*,*,#132,.T.);
#3103=DIRECTION('',(-0.0304472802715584,0.580968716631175,-0.813356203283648));
#3104=VECTOR('',#3103,1.);
#3105=CARTESIAN_POINT('',(-0.50236045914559,9.27475607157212,129.834643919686));
#3106=LINE('',#3105,#3104);
#3107=EDGE_CURVE('E1699',#2678,#123,#3106,.T.);
#3108=ORIENTED_EDGE('',*,*,#3107,.F.);
#3109=EDGE_LOOP('',(#3086,#3092,#3093,#3099,#3100,#3101,#3102,#3108));
#3110=FACE_BOUND('',#3109,.T.);
#3111=ADVANCED_FACE('F1698',(#3110),#3085,.F.);
#3112=CARTESIAN_POINT('',(21.9945334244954,-4.34673334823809,129.128142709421));
#3113=DIRECTION('',(0.659184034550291,0.477114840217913,0.581238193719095));
#3114=DIRECTION('',(0.66136903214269,0.,-0.750060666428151));
#3115=AXIS2_PLACEMENT_3D('',#3112,#3113,#3114);
#3116=PLANE('',#3115);
#3117=ORIENTED_EDGE('',*,*,#3098,.F.);
#3118=ORIENTED_EDGE('',*,*,#2783,.T.);
#3119=DIRECTION('',(-0.563228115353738,-0.198879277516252,0.802010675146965));
#3120=VECTOR('',#3119,1.);
#3121=CARTESIAN_POINT('',(16.2491358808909,2.98023686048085,129.629603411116));
#3122=LINE('',#3121,#3120);
#3123=EDGE_CURVE('E1315',#2723,#2987,#3122,.T.);
#3124=ORIENTED_EDGE('',*,*,#3123,.T.);
#3125=ORIENTED_EDGE('',*,*,#2988,.T.);
#3126=EDGE_LOOP('',(#3117,#3118,#3124,#3125));
#3127=FACE_BOUND('',#3126,.T.);
#3128=ADVANCED_FACE('F1999',(#3127),#3116,.F.);
#3129=CARTESIAN_POINT('',(16.7947772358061,-0.587240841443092,129.128142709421));
#3130=DIRECTION('',(0.812618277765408,0.0425875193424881,0.581238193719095));
#3131=DIRECTION('',(0.581766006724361,0.,-0.813356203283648));
#3132=AXIS2_PLACEMENT_3D('',#3129,#3130,#3131);
#3133=PLANE('',#3132);
#3134=ORIENTED_EDGE('',*,*,#1027,.T.);
#3135=ORIENTED_EDGE('',*,*,#2994,.T.);
#3136=ORIENTED_EDGE('',*,*,#3123,.F.);
#3137=ORIENTED_EDGE('',*,*,#2724,.T.);
#3138=EDGE_LOOP('',(#3134,#3135,#3136,#3137));
#3139=FACE_BOUND('',#3138,.T.);
#3140=ADVANCED_FACE('F1812',(#3139),#3133,.F.);
#3141=CARTESIAN_POINT('',(26.4142181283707,6.93611872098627,14.8718572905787));
#3142=DIRECTION('',(-0.812618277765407,-0.0425875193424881,0.581238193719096));
#3143=DIRECTION('',(0.581766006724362,0.,0.813356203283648));
#3144=AXIS2_PLACEMENT_3D('',#3141,#3142,#3143);
#3145=PLANE('',#3144);
#3146=ORIENTED_EDGE('',*,*,#1043,.T.);
#3147=ORIENTED_EDGE('',*,*,#2738,.T.);
#3148=DIRECTION('',(-0.563228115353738,-0.198879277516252,-0.802010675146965));
#3149=VECTOR('',#3148,1.);
#3150=CARTESIAN_POINT('',(24.8211111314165,6.00705352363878,12.5764911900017));
#3151=LINE('',#3150,#3149);
#3152=EDGE_CURVE('E1317',#2731,#3011,#3151,.T.);
#3153=ORIENTED_EDGE('',*,*,#3152,.T.);
#3154=ORIENTED_EDGE('',*,*,#3012,.T.);
#3155=EDGE_LOOP('',(#3146,#3147,#3153,#3154));
#3156=FACE_BOUND('',#3155,.T.);
#3157=ADVANCED_FACE('F1805',(#3156),#3145,.T.);
#3158=CARTESIAN_POINT('',(16.5112239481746,20.2843277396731,14.8718572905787));
#3159=DIRECTION('',(-0.659184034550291,-0.477114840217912,0.581238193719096));
#3160=DIRECTION('',(0.66136903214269,0.,0.750060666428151));
#3161=AXIS2_PLACEMENT_3D('',#3158,#3159,#3160);
#3162=PLANE('',#3161);
#3163=ORIENTED_EDGE('',*,*,#3152,.F.);
#3164=ORIENTED_EDGE('',*,*,#2774,.T.);
#3165=DIRECTION('',(-0.284545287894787,-0.557211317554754,-0.780095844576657));
#3166=VECTOR('',#3165,1.);
#3167=CARTESIAN_POINT('',(14.0933451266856,14.3289120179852,7.24117440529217));
#3168=LINE('',#3167,#3166);
#3169=EDGE_CURVE('E1331',#578,#3019,#3168,.T.);
#3170=ORIENTED_EDGE('',*,*,#3169,.T.);
#3171=ORIENTED_EDGE('',*,*,#3020,.T.);
#3172=EDGE_LOOP('',(#3163,#3164,#3170,#3171));
#3173=FACE_BOUND('',#3172,.T.);
#3174=ADVANCED_FACE('F1803',(#3173),#3162,.T.);
#3175=CARTESIAN_POINT('',(-17.5,19.7793997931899,14.8718572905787));
#3176=DIRECTION('',(0.,-0.813733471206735,0.581238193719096));
#3177=DIRECTION('',(0.,-0.581238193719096,-0.813733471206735));
#3178=AXIS2_PLACEMENT_3D('',#3175,#3176,#3177);
#3179=PLANE('',#3178);
#3180=ORIENTED_EDGE('',*,*,#579,.T.);
#3181=DIRECTION('',(0.284545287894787,-0.557211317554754,-0.780095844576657));
#3182=VECTOR('',#3181,1.);
#3183=CARTESIAN_POINT('',(-15.5278703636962,17.1380736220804,11.1740006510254));
#3184=LINE('',#3183,#3182);
#3185=EDGE_CURVE('E1328',#570,#3027,#3184,.T.);
#3186=ORIENTED_EDGE('',*,*,#3185,.T.);
#3187=ORIENTED_EDGE('',*,*,#3028,.T.);
#3188=ORIENTED_EDGE('',*,*,#3169,.F.);
#3189=EDGE_LOOP('',(#3180,#3186,#3187,#3188));
#3190=FACE_BOUND('',#3189,.T.);
#3191=ADVANCED_FACE('F1798',(#3190),#3179,.T.);
#3192=CARTESIAN_POINT('',(-26.6443694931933,6.28432773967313,14.8718572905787));
#3193=DIRECTION('',(0.659184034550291,-0.477114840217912,0.581238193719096));
#3194=DIRECTION('',(0.66136903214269,0.,-0.750060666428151));
#3195=AXIS2_PLACEMENT_3D('',#3192,#3193,#3194);
#3196=PLANE('',#3195);
#3197=ORIENTED_EDGE('',*,*,#3185,.F.);
#3198=ORIENTED_EDGE('',*,*,#2881,.T.);
#3199=DIRECTION('',(0.563228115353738,-0.198879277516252,-0.802010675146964));
#3200=VECTOR('',#3199,1.);
#3201=CARTESIAN_POINT('',(-26.4674058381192,6.5883702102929,14.9207383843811));
#3202=LINE('',#3201,#3200);
#3203=EDGE_CURVE('E1321',#2874,#3035,#3202,.T.);
#3204=ORIENTED_EDGE('',*,*,#3203,.T.);
#3205=ORIENTED_EDGE('',*,*,#3036,.T.);
#3206=EDGE_LOOP('',(#3197,#3198,#3204,#3205));
#3207=FACE_BOUND('',#3206,.T.);
#3208=ADVANCED_FACE('F1795',(#3207),#3196,.T.);
#3209=CARTESIAN_POINT('',(-26.4142181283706,6.93611872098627,14.8718572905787));
#3210=DIRECTION('',(0.812618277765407,-0.0425875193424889,0.581238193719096));
#3211=DIRECTION('',(0.581766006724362,0.,-0.813356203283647));
#3212=AXIS2_PLACEMENT_3D('',#3209,#3210,#3211);
#3213=PLANE('',#3212);
#3214=ORIENTED_EDGE('',*,*,#3203,.F.);
#3215=ORIENTED_EDGE('',*,*,#2924,.T.);
#3216=ORIENTED_EDGE('',*,*,#1059,.T.);
#3217=ORIENTED_EDGE('',*,*,#3042,.T.);
#3218=EDGE_LOOP('',(#3214,#3215,#3216,#3217));
#3219=FACE_BOUND('',#3218,.T.);
#3220=ADVANCED_FACE('F1819',(#3219),#3213,.T.);
#3221=CARTESIAN_POINT('',(8.,2.,132.999999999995));
#3222=DIRECTION('',(0.,0.,-1.));
#3223=DIRECTION('',(-1.,0.,0.));
#3224=AXIS2_PLACEMENT_3D('',#3221,#3222,#3223);
#3225=CYLINDRICAL_SURFACE('',#3224,2.49999999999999);
#3226=ORIENTED_EDGE('',*,*,#2949,.F.);
#3227=DIRECTION('',(0.,0.,-1.));
#3228=VECTOR('',#3227,1.);
#3229=CARTESIAN_POINT('',(10.4965738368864,2.13083989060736,132.999999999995));
#3230=LINE('',#3229,#3228);
#3231=EDGE_CURVE('E1323',#1531,#2939,#3230,.T.);
#3232=ORIENTED_EDGE('',*,*,#3231,.F.);
#3233=ORIENTED_EDGE('',*,*,#1532,.T.);
#3234=DIRECTION('',(0.,0.,1.));
#3235=VECTOR('',#3234,1.);
#3236=CARTESIAN_POINT('',(5.50342616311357,2.13083989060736,132.999999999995));
#3237=LINE('',#3236,#3235);
#3238=EDGE_CURVE('E1318',#1522,#2948,#3237,.F.);
#3239=ORIENTED_EDGE('',*,*,#3238,.T.);
#3240=EDGE_LOOP('',(#3226,#3232,#3233,#3239));
#3241=FACE_BOUND('',#3240,.T.);
#3242=ADVANCED_FACE('F1822',(#3241),#3225,.F.);
#3243=CARTESIAN_POINT('',(5.3876393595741,-0.0785039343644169,132.999999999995));
#3244=DIRECTION('',(0.998629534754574,-0.0523359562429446,0.));
#3245=DIRECTION('',(0.0523359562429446,0.998629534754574,0.));
#3246=AXIS2_PLACEMENT_3D('',#3243,#3244,#3245);
#3247=PLANE('',#3246);
#3248=ORIENTED_EDGE('',*,*,#2955,.F.);
#3249=ORIENTED_EDGE('',*,*,#3238,.F.);
#3250=ORIENTED_EDGE('',*,*,#1523,.T.);
#3251=ORIENTED_EDGE('',*,*,#1091,.T.);
#3252=EDGE_LOOP('',(#3248,#3249,#3250,#3251));
#3253=FACE_BOUND('',#3252,.T.);
#3254=ADVANCED_FACE('F1826',(#3253),#3247,.T.);
#3255=CARTESIAN_POINT('',(10.6123606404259,-0.0785039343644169,132.999999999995));
#3256=DIRECTION('',(-0.998629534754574,-0.0523359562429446,0.));
#3257=DIRECTION('',(0.0523359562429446,-0.998629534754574,0.));
#3258=AXIS2_PLACEMENT_3D('',#3255,#3256,#3257);
#3259=PLANE('',#3258);
#3260=ORIENTED_EDGE('',*,*,#2940,.F.);
#3261=ORIENTED_EDGE('',*,*,#1011,.F.);
#3262=ORIENTED_EDGE('',*,*,#1538,.T.);
#3263=ORIENTED_EDGE('',*,*,#3231,.T.);
#3264=EDGE_LOOP('',(#3260,#3261,#3262,#3263));
#3265=FACE_BOUND('',#3264,.T.);
#3266=ADVANCED_FACE('F1830',(#3265),#3259,.T.);
#3267=DIRECTION('',(0.052264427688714,0.997264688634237,0.052264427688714));
#3268=VECTOR('',#3267,1.);
#3269=CARTESIAN_POINT('',(13.8085853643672,17.3083122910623,88.1330124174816));
#3270=LINE('',#3269,#3268);
#3271=CARTESIAN_POINT('',(13.8186312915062,17.4999999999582,88.1430583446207));
#3272=VERTEX_POINT('',#3271);
#3273=EDGE_CURVE('E1753',#2837,#3272,#3270,.F.);
#3274=ORIENTED_EDGE('',*,*,#3273,.F.);
#3275=ORIENTED_EDGE('',*,*,#2838,.F.);
#3276=DIRECTION('',(0.052264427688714,0.997264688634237,0.052264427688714));
#3277=VECTOR('',#3276,1.);
#3278=CARTESIAN_POINT('',(13.9938525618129,20.8434210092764,95.4938525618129));
#3279=LINE('',#3278,#3277);
#3280=CARTESIAN_POINT('',(13.8186312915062,17.4999999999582,95.3186312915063));
#3281=VERTEX_POINT('',#3280);
#3282=EDGE_CURVE('E1309',#3281,#2833,#3279,.T.);
#3283=ORIENTED_EDGE('',*,*,#3282,.F.);
#3284=EDGE_CURVE('E1354',#3281,#3272,#386,.T.);
#3285=ORIENTED_EDGE('',*,*,#3284,.T.);
#3286=EDGE_LOOP('',(#3274,#3275,#3283,#3285));
#3287=FACE_BOUND('',#3286,.T.);
#3288=ADVANCED_FACE('F1834',(#3287),#373,.T.);
#3289=DIRECTION('',(0.052264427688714,0.997264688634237,0.052264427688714));
#3290=VECTOR('',#3289,1.);
#3291=CARTESIAN_POINT('',(1.14384533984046,21.5150167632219,95.5290494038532));
#3292=LINE('',#3291,#3290);
#3293=CARTESIAN_POINT('',(0.933427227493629,17.4999999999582,95.3186312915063));
#3294=VERTEX_POINT('',#3293);
#3295=EDGE_CURVE('E1731',#3294,#2829,#3292,.T.);
#3296=ORIENTED_EDGE('',*,*,#3295,.F.);
#3297=EDGE_CURVE('E1365',#3294,#3281,#230,.T.);
#3298=ORIENTED_EDGE('',*,*,#3297,.T.);
#3299=ORIENTED_EDGE('',*,*,#3282,.T.);
#3300=ORIENTED_EDGE('',*,*,#2834,.F.);
#3301=EDGE_LOOP('',(#3296,#3298,#3299,#3300));
#3302=FACE_BOUND('',#3301,.T.);
#3303=ADVANCED_FACE('F1838',(#3302),#226,.T.);
#3304=DIRECTION('',(0.052264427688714,-0.997264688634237,-0.052264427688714));
#3305=VECTOR('',#3304,1.);
#3306=CARTESIAN_POINT('',(-13.8085853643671,17.3083122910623,88.1330124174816));
#3307=LINE('',#3306,#3305);
#3308=EDGE_CURVE('E1751',#265,#147,#3307,.F.);
#3309=ORIENTED_EDGE('',*,*,#3308,.F.);
#3310=ORIENTED_EDGE('',*,*,#279,.T.);
#3311=ORIENTED_EDGE('',*,*,#248,.T.);
#3312=ORIENTED_EDGE('',*,*,#156,.F.);
#3313=EDGE_LOOP('',(#3309,#3310,#3311,#3312));
#3314=FACE_BOUND('',#3313,.T.);
#3315=ADVANCED_FACE('F1843',(#3314),#404,.T.);
#3316=CARTESIAN_POINT('',(12.5,20.9214960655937,17.5020556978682));
#3317=DIRECTION('',(0.,-0.0523359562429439,-0.998629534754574));
#3318=DIRECTION('',(0.,0.998629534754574,-0.0523359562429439));
#3319=AXIS2_PLACEMENT_3D('',#3316,#3317,#3318);
#3320=PLANE('',#3319);
#3321=ORIENTED_EDGE('',*,*,#678,.T.);
#3322=ORIENTED_EDGE('',*,*,#633,.T.);
#3323=ORIENTED_EDGE('',*,*,#555,.F.);
#3324=ORIENTED_EDGE('',*,*,#611,.F.);
#3325=EDGE_LOOP('',(#3321,#3322,#3323,#3324));
#3326=FACE_BOUND('',#3325,.T.);
#3327=ADVANCED_FACE('F1782',(#3326),#3320,.T.);
#3328=DIRECTION('',(0.,0.,1.));
#3329=VECTOR('',#3328,1.);
#3330=CARTESIAN_POINT('',(0.933427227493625,17.4999999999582,94.0000000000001));
#3331=LINE('',#3330,#3329);
#3332=CARTESIAN_POINT('',(0.933427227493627,17.4999999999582,88.1430583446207));
#3333=VERTEX_POINT('',#3332);
#3334=EDGE_CURVE('E1728',#3333,#3294,#3331,.T.);
#3335=ORIENTED_EDGE('',*,*,#3334,.F.);
#3336=EDGE_CURVE('E1196',#3272,#3333,#261,.F.);
#3337=ORIENTED_EDGE('',*,*,#3336,.F.);
#3338=ORIENTED_EDGE('',*,*,#3284,.F.);
#3339=ORIENTED_EDGE('',*,*,#3297,.F.);
#3340=EDGE_LOOP('',(#3335,#3337,#3338,#3339));
#3341=FACE_BOUND('',#3340,.T.);
#3342=ADVANCED_FACE('F1852',(#3341),#257,.T.);
#3343=CARTESIAN_POINT('',(4.00000000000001,18.9214960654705,36.4979443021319));
#3344=DIRECTION('',(0.,-0.0523359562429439,0.998629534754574));
#3345=DIRECTION('',(0.,-0.998629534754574,-0.0523359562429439));
#3346=AXIS2_PLACEMENT_3D('',#3343,#3344,#3345);
#3347=PLANE('',#3346);
#3348=ORIENTED_EDGE('',*,*,#719,.F.);
#3349=DIRECTION('',(-0.052264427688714,0.997264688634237,0.052264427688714));
#3350=VECTOR('',#3349,1.);
#3351=CARTESIAN_POINT('',(2.5307315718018,18.3743277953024,36.4692684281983));
#3352=LINE('',#3351,#3350);
#3353=EDGE_CURVE('E1457',#2546,#712,#3352,.T.);
#3354=ORIENTED_EDGE('',*,*,#3353,.F.);
#3355=ORIENTED_EDGE('',*,*,#2549,.T.);
#3356=DIRECTION('',(0.052264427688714,0.997264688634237,0.052264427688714));
#3357=VECTOR('',#3356,1.);
#3358=CARTESIAN_POINT('',(9.48292628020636,18.6349351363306,36.4829262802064));
#3359=LINE('',#3358,#3357);
#3360=EDGE_CURVE('E1452',#2548,#694,#3359,.T.);
#3361=ORIENTED_EDGE('',*,*,#3360,.T.);
#3362=EDGE_LOOP('',(#3348,#3354,#3355,#3361));
#3363=FACE_BOUND('',#3362,.T.);
#3364=ADVANCED_FACE('F1855',(#3363),#3347,.T.);
#3365=CARTESIAN_POINT('',(2.50205569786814,18.9214960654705,26.0000000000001));
#3366=DIRECTION('',(-0.998629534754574,-0.0523359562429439,0.));
#3367=DIRECTION('',(0.0523359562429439,-0.998629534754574,0.));
#3368=AXIS2_PLACEMENT_3D('',#3365,#3366,#3367);
#3369=PLANE('',#3368);
#3370=ORIENTED_EDGE('',*,*,#713,.F.);
#3371=DIRECTION('',(-0.052264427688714,0.997264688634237,-0.052264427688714));
#3372=VECTOR('',#3371,1.);
#3373=CARTESIAN_POINT('',(2.51707371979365,18.6349351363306,24.5170737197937));
#3374=LINE('',#3373,#3372);
#3375=EDGE_CURVE('E1460',#2556,#704,#3374,.T.);
#3376=ORIENTED_EDGE('',*,*,#3375,.F.);
#3377=ORIENTED_EDGE('',*,*,#2557,.T.);
#3378=ORIENTED_EDGE('',*,*,#3353,.T.);
#3379=EDGE_LOOP('',(#3370,#3376,#3377,#3378));
#3380=FACE_BOUND('',#3379,.T.);
#3381=ADVANCED_FACE('F1861',(#3380),#3369,.T.);
#3382=CARTESIAN_POINT('',(8.00000000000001,18.9214960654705,24.5020556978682));
#3383=DIRECTION('',(0.,-0.0523359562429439,-0.998629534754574));
#3384=DIRECTION('',(0.,0.998629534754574,-0.0523359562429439));
#3385=AXIS2_PLACEMENT_3D('',#3382,#3383,#3384);
#3386=PLANE('',#3385);
#3387=ORIENTED_EDGE('',*,*,#705,.F.);
#3388=DIRECTION('',(0.052264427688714,0.997264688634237,-0.052264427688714));
#3389=VECTOR('',#3388,1.);
#3390=CARTESIAN_POINT('',(9.46926842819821,18.3743277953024,24.5307315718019));
#3391=LINE('',#3390,#3389);
#3392=EDGE_CURVE('E1455',#2564,#696,#3391,.T.);
#3393=ORIENTED_EDGE('',*,*,#3392,.F.);
#3394=ORIENTED_EDGE('',*,*,#2565,.T.);
#3395=ORIENTED_EDGE('',*,*,#3375,.T.);
#3396=EDGE_LOOP('',(#3387,#3393,#3394,#3395));
#3397=FACE_BOUND('',#3396,.T.);
#3398=ADVANCED_FACE('F1865',(#3397),#3386,.T.);
#3399=CARTESIAN_POINT('',(9.49794430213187,18.9214960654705,35.0000000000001));
#3400=DIRECTION('',(0.998629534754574,-0.0523359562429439,0.));
#3401=DIRECTION('',(0.0523359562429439,0.998629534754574,0.));
#3402=AXIS2_PLACEMENT_3D('',#3399,#3400,#3401);
#3403=PLANE('',#3402);
#3404=ORIENTED_EDGE('',*,*,#697,.F.);
#3405=ORIENTED_EDGE('',*,*,#3360,.F.);
#3406=ORIENTED_EDGE('',*,*,#2571,.T.);
#3407=ORIENTED_EDGE('',*,*,#3392,.T.);
#3408=EDGE_LOOP('',(#3404,#3405,#3406,#3407));
#3409=FACE_BOUND('',#3408,.T.);
#3410=ADVANCED_FACE('F1869',(#3409),#3403,.T.);
#3411=CARTESIAN_POINT('',(-8.,18.9214960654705,37.497944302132));
#3412=DIRECTION('',(0.,-0.0523359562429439,0.998629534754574));
#3413=DIRECTION('',(0.,-0.998629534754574,-0.0523359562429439));
#3414=AXIS2_PLACEMENT_3D('',#3411,#3412,#3413);
#3415=PLANE('',#3414);
#3416=ORIENTED_EDGE('',*,*,#753,.F.);
#3417=DIRECTION('',(-0.052264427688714,0.997264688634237,0.052264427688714));
#3418=VECTOR('',#3417,1.);
#3419=CARTESIAN_POINT('',(-9.46653685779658,18.3222063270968,37.4665368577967));
#3420=LINE('',#3419,#3418);
#3421=CARTESIAN_POINT('',(-9.29242740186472,14.9999999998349,37.2924274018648));
#3422=VERTEX_POINT('',#3421);
#3423=EDGE_CURVE('E1445',#3422,#746,#3420,.T.);
#3424=ORIENTED_EDGE('',*,*,#3423,.F.);
#3425=DIRECTION('',(1.,0.,0.));
#3426=VECTOR('',#3425,1.);
#3427=CARTESIAN_POINT('',(-4.,14.9999999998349,37.2924274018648));
#3428=LINE('',#3427,#3426);
#3429=CARTESIAN_POINT('',(-2.70757259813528,14.9999999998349,37.2924274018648));
#3430=VERTEX_POINT('',#3429);
#3431=EDGE_CURVE('E1436',#3422,#3430,#3428,.T.);
#3432=ORIENTED_EDGE('',*,*,#3431,.T.);
#3433=DIRECTION('',(0.052264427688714,0.997264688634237,0.052264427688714));
#3434=VECTOR('',#3433,1.);
#3435=CARTESIAN_POINT('',(-2.51707371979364,18.6349351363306,37.4829262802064));
#3436=LINE('',#3435,#3434);
#3437=EDGE_CURVE('E1463',#3430,#728,#3436,.T.);
#3438=ORIENTED_EDGE('',*,*,#3437,.T.);
#3439=EDGE_LOOP('',(#3416,#3424,#3432,#3438));
#3440=FACE_BOUND('',#3439,.T.);
#3441=ADVANCED_FACE('F1873',(#3440),#3415,.T.);
#3442=CARTESIAN_POINT('',(-9.49794430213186,18.9214960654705,26.0000000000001));
#3443=DIRECTION('',(-0.998629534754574,-0.0523359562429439,0.));
#3444=DIRECTION('',(0.0523359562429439,-0.998629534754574,0.));
#3445=AXIS2_PLACEMENT_3D('',#3442,#3443,#3444);
#3446=PLANE('',#3445);
#3447=ORIENTED_EDGE('',*,*,#747,.F.);
#3448=DIRECTION('',(-0.052264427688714,0.997264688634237,-0.052264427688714));
#3449=VECTOR('',#3448,1.);
#3450=CARTESIAN_POINT('',(-9.48292628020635,18.6349351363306,24.5170737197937));
#3451=LINE('',#3450,#3449);
#3452=CARTESIAN_POINT('',(-9.29242740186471,14.9999999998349,24.7075725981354));
#3453=VERTEX_POINT('',#3452);
#3454=EDGE_CURVE('E1469',#3453,#738,#3451,.T.);
#3455=ORIENTED_EDGE('',*,*,#3454,.F.);
#3456=DIRECTION('',(0.,0.,1.));
#3457=VECTOR('',#3456,1.);
#3458=CARTESIAN_POINT('',(-9.29242740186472,14.9999999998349,36.0000000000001));
#3459=LINE('',#3458,#3457);
#3460=EDGE_CURVE('E1467',#3453,#3422,#3459,.T.);
#3461=ORIENTED_EDGE('',*,*,#3460,.T.);
#3462=ORIENTED_EDGE('',*,*,#3423,.T.);
#3463=EDGE_LOOP('',(#3447,#3455,#3461,#3462));
#3464=FACE_BOUND('',#3463,.T.);
#3465=ADVANCED_FACE('F1877',(#3464),#3446,.T.);
#3466=CARTESIAN_POINT('',(-4.,18.9214960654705,24.5020556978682));
#3467=DIRECTION('',(0.,-0.0523359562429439,-0.998629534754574));
#3468=DIRECTION('',(0.,0.998629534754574,-0.0523359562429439));
#3469=AXIS2_PLACEMENT_3D('',#3466,#3467,#3468);
#3470=PLANE('',#3469);
#3471=ORIENTED_EDGE('',*,*,#739,.F.);
#3472=DIRECTION('',(0.052264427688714,0.997264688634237,-0.052264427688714));
#3473=VECTOR('',#3472,1.);
#3474=CARTESIAN_POINT('',(-2.53346314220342,18.3222063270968,24.5334631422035));
#3475=LINE('',#3474,#3473);
#3476=CARTESIAN_POINT('',(-2.70757259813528,14.9999999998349,24.7075725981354));
#3477=VERTEX_POINT('',#3476);
#3478=EDGE_CURVE('E1466',#3477,#730,#3475,.T.);
#3479=ORIENTED_EDGE('',*,*,#3478,.F.);
#3480=DIRECTION('',(-1.,0.,0.));
#3481=VECTOR('',#3480,1.);
#3482=CARTESIAN_POINT('',(-4.,14.9999999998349,24.7075725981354));
#3483=LINE('',#3482,#3481);
#3484=EDGE_CURVE('E1557',#3477,#3453,#3483,.T.);
#3485=ORIENTED_EDGE('',*,*,#3484,.T.);
#3486=ORIENTED_EDGE('',*,*,#3454,.T.);
#3487=EDGE_LOOP('',(#3471,#3479,#3485,#3486));
#3488=FACE_BOUND('',#3487,.T.);
#3489=ADVANCED_FACE('F1881',(#3488),#3470,.T.);
#3490=CARTESIAN_POINT('',(-2.50205569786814,18.9214960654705,36.0000000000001));
#3491=DIRECTION('',(0.998629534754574,-0.0523359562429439,0.));
#3492=DIRECTION('',(0.0523359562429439,0.998629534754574,0.));
#3493=AXIS2_PLACEMENT_3D('',#3490,#3491,#3492);
#3494=PLANE('',#3493);
#3495=ORIENTED_EDGE('',*,*,#731,.F.);
#3496=ORIENTED_EDGE('',*,*,#3437,.F.);
#3497=DIRECTION('',(0.,0.,-1.));
#3498=VECTOR('',#3497,1.);
#3499=CARTESIAN_POINT('',(-2.70757259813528,14.9999999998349,36.0000000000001));
#3500=LINE('',#3499,#3498);
#3501=EDGE_CURVE('E1554',#3430,#3477,#3500,.T.);
#3502=ORIENTED_EDGE('',*,*,#3501,.T.);
#3503=ORIENTED_EDGE('',*,*,#3478,.T.);
#3504=EDGE_LOOP('',(#3495,#3496,#3502,#3503));
#3505=FACE_BOUND('',#3504,.T.);
#3506=ADVANCED_FACE('F1885',(#3505),#3494,.T.);
#3507=CARTESIAN_POINT('',(-4.,14.9999999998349,36.0000000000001));
#3508=DIRECTION('',(0.,1.,0.));
#3509=DIRECTION('',(0.,0.,1.));
#3510=AXIS2_PLACEMENT_3D('',#3507,#3508,#3509);
#3511=PLANE('',#3510);
#3512=ORIENTED_EDGE('',*,*,#1978,.T.);
#3513=ORIENTED_EDGE('',*,*,#2048,.T.);
#3514=ORIENTED_EDGE('',*,*,#2026,.T.);
#3515=ORIENTED_EDGE('',*,*,#2002,.T.);
#3516=EDGE_LOOP('',(#3512,#3513,#3514,#3515));
#3517=FACE_BOUND('',#3516,.T.);
#3518=ORIENTED_EDGE('',*,*,#3431,.F.);
#3519=ORIENTED_EDGE('',*,*,#3460,.F.);
#3520=ORIENTED_EDGE('',*,*,#3484,.F.);
#3521=ORIENTED_EDGE('',*,*,#3501,.F.);
#3522=EDGE_LOOP('',(#3518,#3519,#3520,#3521));
#3523=FACE_BOUND('',#3522,.T.);
#3524=ADVANCED_FACE('F1889',(#3517,#3523),#3511,.F.);
#3525=CARTESIAN_POINT('',(0.,18.9214960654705,42.5000000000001));
#3526=DIRECTION('',(0.,1.,0.));
#3527=DIRECTION('',(0.,0.,1.));
#3528=AXIS2_PLACEMENT_3D('',#3525,#3526,#3527);
#3529=CONICAL_SURFACE('',#3528,4.99794430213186,0.0523598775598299);
#3530=CARTESIAN_POINT('',(0.,14.9999999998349,42.5000000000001));
#3531=DIRECTION('',(0.,1.,0.));
#3532=DIRECTION('',(0.,0.,1.));
#3533=AXIS2_PLACEMENT_3D('',#3530,#3531,#3532);
#3534=CIRCLE('',#3533,4.79242740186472);
#3535=CARTESIAN_POINT('',(4.79242740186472,14.9999999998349,42.5000000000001));
#3536=VERTEX_POINT('',#3535);
#3537=CARTESIAN_POINT('',(-4.79242740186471,14.9999999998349,42.5000000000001));
#3538=VERTEX_POINT('',#3537);
#3539=EDGE_CURVE('E1424',#3536,#3538,#3534,.T.);
#3540=ORIENTED_EDGE('',*,*,#3539,.T.);
#3541=DIRECTION('',(0.0523359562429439,-0.998629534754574,0.));
#3542=VECTOR('',#3541,1.);
#3543=CARTESIAN_POINT('',(-4.99794430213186,18.9214960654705,42.5000000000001));
#3544=LINE('',#3543,#3542);
#3545=EDGE_CURVE('E1472',#3538,#646,#3544,.F.);
#3546=ORIENTED_EDGE('',*,*,#3545,.T.);
#3547=ORIENTED_EDGE('',*,*,#647,.F.);
#3548=DIRECTION('',(0.0523359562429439,0.998629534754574,0.));
#3549=VECTOR('',#3548,1.);
#3550=CARTESIAN_POINT('',(4.99794430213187,18.9214960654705,42.5000000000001));
#3551=LINE('',#3550,#3549);
#3552=EDGE_CURVE('E1432',#3536,#644,#3551,.T.);
#3553=ORIENTED_EDGE('',*,*,#3552,.F.);
#3554=EDGE_LOOP('',(#3540,#3546,#3547,#3553));
#3555=FACE_BOUND('',#3554,.T.);
#3556=ADVANCED_FACE('F1891',(#3555),#3529,.T.);
#3557=CARTESIAN_POINT('',(4.99794430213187,18.9214960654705,47.0000000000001));
#3558=DIRECTION('',(0.998629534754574,-0.0523359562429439,0.));
#3559=DIRECTION('',(0.0523359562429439,0.998629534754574,0.));
#3560=AXIS2_PLACEMENT_3D('',#3557,#3558,#3559);
#3561=PLANE('',#3560);
#3562=ORIENTED_EDGE('',*,*,#669,.F.);
#3563=DIRECTION('',(0.052264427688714,0.997264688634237,0.052264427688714));
#3564=VECTOR('',#3563,1.);
#3565=CARTESIAN_POINT('',(4.97473156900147,18.4785707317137,48.4747315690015));
#3566=LINE('',#3565,#3564);
#3567=CARTESIAN_POINT('',(4.79242740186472,14.9999999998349,48.2924274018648));
#3568=VERTEX_POINT('',#3567);
#3569=EDGE_CURVE('E1478',#3568,#662,#3566,.T.);
#3570=ORIENTED_EDGE('',*,*,#3569,.F.);
#3571=DIRECTION('',(0.,0.,-1.));
#3572=VECTOR('',#3571,1.);
#3573=CARTESIAN_POINT('',(4.79242740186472,14.9999999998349,42.5000000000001));
#3574=LINE('',#3573,#3572);
#3575=EDGE_CURVE('E1476',#3568,#3536,#3574,.T.);
#3576=ORIENTED_EDGE('',*,*,#3575,.T.);
#3577=ORIENTED_EDGE('',*,*,#3552,.T.);
#3578=EDGE_LOOP('',(#3562,#3570,#3576,#3577));
#3579=FACE_BOUND('',#3578,.T.);
#3580=ADVANCED_FACE('F1894',(#3579),#3561,.T.);
#3581=CARTESIAN_POINT('',(-3.49999999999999,18.9214960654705,48.4979443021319));
#3582=DIRECTION('',(0.,-0.0523359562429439,0.998629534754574));
#3583=DIRECTION('',(0.,-0.998629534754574,-0.0523359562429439));
#3584=AXIS2_PLACEMENT_3D('',#3581,#3582,#3583);
#3585=PLANE('',#3584);
#3586=ORIENTED_EDGE('',*,*,#3569,.T.);
#3587=ORIENTED_EDGE('',*,*,#663,.F.);
#3588=DIRECTION('',(-0.052264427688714,0.997264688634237,0.052264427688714));
#3589=VECTOR('',#3588,1.);
#3590=CARTESIAN_POINT('',(-4.98156049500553,18.6088744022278,48.4815604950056));
#3591=LINE('',#3590,#3589);
#3592=CARTESIAN_POINT('',(-4.79242740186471,14.9999999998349,48.2924274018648));
#3593=VERTEX_POINT('',#3592);
#3594=EDGE_CURVE('E1475',#3593,#654,#3591,.T.);
#3595=ORIENTED_EDGE('',*,*,#3594,.F.);
#3596=DIRECTION('',(1.,0.,0.));
#3597=VECTOR('',#3596,1.);
#3598=CARTESIAN_POINT('',(0.,14.9999999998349,48.2924274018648));
#3599=LINE('',#3598,#3597);
#3600=EDGE_CURVE('E1566',#3593,#3568,#3599,.T.);
#3601=ORIENTED_EDGE('',*,*,#3600,.T.);
#3602=EDGE_LOOP('',(#3586,#3587,#3595,#3601));
#3603=FACE_BOUND('',#3602,.T.);
#3604=ADVANCED_FACE('F1898',(#3603),#3585,.T.);
#3605=CARTESIAN_POINT('',(-4.99794430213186,18.9214960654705,42.5000000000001));
#3606=DIRECTION('',(-0.998629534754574,-0.0523359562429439,0.));
#3607=DIRECTION('',(0.0523359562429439,-0.998629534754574,0.));
#3608=AXIS2_PLACEMENT_3D('',#3605,#3606,#3607);
#3609=PLANE('',#3608);
#3610=ORIENTED_EDGE('',*,*,#655,.F.);
#3611=ORIENTED_EDGE('',*,*,#3545,.F.);
#3612=DIRECTION('',(0.,0.,1.));
#3613=VECTOR('',#3612,1.);
#3614=CARTESIAN_POINT('',(-4.79242740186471,14.9999999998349,42.5000000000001));
#3615=LINE('',#3614,#3613);
#3616=EDGE_CURVE('E1563',#3538,#3593,#3615,.T.);
#3617=ORIENTED_EDGE('',*,*,#3616,.T.);
#3618=ORIENTED_EDGE('',*,*,#3594,.T.);
#3619=EDGE_LOOP('',(#3610,#3611,#3617,#3618));
#3620=FACE_BOUND('',#3619,.T.);
#3621=ADVANCED_FACE('F1902',(#3620),#3609,.T.);
#3622=CARTESIAN_POINT('',(0.,14.9999999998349,42.5000000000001));
#3623=DIRECTION('',(0.,1.,0.));
#3624=DIRECTION('',(0.,0.,1.));
#3625=AXIS2_PLACEMENT_3D('',#3622,#3623,#3624);
#3626=PLANE('',#3625);
#3627=ORIENTED_EDGE('',*,*,#2122,.T.);
#3628=ORIENTED_EDGE('',*,*,#2099,.T.);
#3629=ORIENTED_EDGE('',*,*,#2075,.T.);
#3630=ORIENTED_EDGE('',*,*,#2145,.T.);
#3631=EDGE_LOOP('',(#3627,#3628,#3629,#3630));
#3632=FACE_BOUND('',#3631,.T.);
#3633=ORIENTED_EDGE('',*,*,#3575,.F.);
#3634=ORIENTED_EDGE('',*,*,#3600,.F.);
#3635=ORIENTED_EDGE('',*,*,#3616,.F.);
#3636=ORIENTED_EDGE('',*,*,#3539,.F.);
#3637=EDGE_LOOP('',(#3633,#3634,#3635,#3636));
#3638=FACE_BOUND('',#3637,.T.);
#3639=ADVANCED_FACE('F1906',(#3632,#3638),#3626,.F.);
#3640=CARTESIAN_POINT('',(4.,18.9214960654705,71.497944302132));
#3641=DIRECTION('',(0.,-0.0523359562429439,0.998629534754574));
#3642=DIRECTION('',(0.,-0.998629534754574,-0.0523359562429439));
#3643=AXIS2_PLACEMENT_3D('',#3640,#3641,#3642);
#3644=PLANE('',#3643);
#3645=ORIENTED_EDGE('',*,*,#508,.F.);
#3646=DIRECTION('',(-0.052264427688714,0.997264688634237,0.052264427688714));
#3647=VECTOR('',#3646,1.);
#3648=CARTESIAN_POINT('',(2.53073157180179,18.3743277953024,71.4692684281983));
#3649=LINE('',#3648,#3647);
#3650=EDGE_CURVE('E1420',#2592,#501,#3649,.T.);
#3651=ORIENTED_EDGE('',*,*,#3650,.F.);
#3652=ORIENTED_EDGE('',*,*,#2595,.T.);
#3653=DIRECTION('',(0.052264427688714,0.997264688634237,0.052264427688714));
#3654=VECTOR('',#3653,1.);
#3655=CARTESIAN_POINT('',(9.48292628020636,18.6349351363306,71.4829262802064));
#3656=LINE('',#3655,#3654);
#3657=EDGE_CURVE('E1482',#2594,#483,#3656,.T.);
#3658=ORIENTED_EDGE('',*,*,#3657,.T.);
#3659=EDGE_LOOP('',(#3645,#3651,#3652,#3658));
#3660=FACE_BOUND('',#3659,.T.);
#3661=ADVANCED_FACE('F1908',(#3660),#3644,.T.);
#3662=CARTESIAN_POINT('',(2.50205569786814,18.9214960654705,61.0000000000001));
#3663=DIRECTION('',(-0.998629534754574,-0.0523359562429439,0.));
#3664=DIRECTION('',(0.0523359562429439,-0.998629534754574,0.));
#3665=AXIS2_PLACEMENT_3D('',#3662,#3663,#3664);
#3666=PLANE('',#3665);
#3667=ORIENTED_EDGE('',*,*,#502,.F.);
#3668=DIRECTION('',(-0.052264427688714,0.997264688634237,-0.052264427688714));
#3669=VECTOR('',#3668,1.);
#3670=CARTESIAN_POINT('',(2.51707371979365,18.6349351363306,59.5170737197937));
#3671=LINE('',#3670,#3669);
#3672=EDGE_CURVE('E1488',#2602,#493,#3671,.T.);
#3673=ORIENTED_EDGE('',*,*,#3672,.F.);
#3674=ORIENTED_EDGE('',*,*,#2603,.T.);
#3675=ORIENTED_EDGE('',*,*,#3650,.T.);
#3676=EDGE_LOOP('',(#3667,#3673,#3674,#3675));
#3677=FACE_BOUND('',#3676,.T.);
#3678=ADVANCED_FACE('F1911',(#3677),#3666,.T.);
#3679=CARTESIAN_POINT('',(8.,18.9214960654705,59.5020556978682));
#3680=DIRECTION('',(0.,-0.0523359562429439,-0.998629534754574));
#3681=DIRECTION('',(0.,0.998629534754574,-0.0523359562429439));
#3682=AXIS2_PLACEMENT_3D('',#3679,#3680,#3681);
#3683=PLANE('',#3682);
#3684=ORIENTED_EDGE('',*,*,#494,.F.);
#3685=DIRECTION('',(0.052264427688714,0.997264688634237,-0.052264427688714));
#3686=VECTOR('',#3685,1.);
#3687=CARTESIAN_POINT('',(9.46926842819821,18.3743277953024,59.5307315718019));
#3688=LINE('',#3687,#3686);
#3689=EDGE_CURVE('E1485',#2610,#485,#3688,.T.);
#3690=ORIENTED_EDGE('',*,*,#3689,.F.);
#3691=ORIENTED_EDGE('',*,*,#2611,.T.);
#3692=ORIENTED_EDGE('',*,*,#3672,.T.);
#3693=EDGE_LOOP('',(#3684,#3690,#3691,#3692));
#3694=FACE_BOUND('',#3693,.T.);
#3695=ADVANCED_FACE('F1915',(#3694),#3683,.T.);
#3696=CARTESIAN_POINT('',(9.49794430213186,18.9214960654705,70.0000000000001));
#3697=DIRECTION('',(0.998629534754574,-0.0523359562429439,0.));
#3698=DIRECTION('',(0.0523359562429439,0.998629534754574,0.));
#3699=AXIS2_PLACEMENT_3D('',#3696,#3697,#3698);
#3700=PLANE('',#3699);
#3701=ORIENTED_EDGE('',*,*,#486,.F.);
#3702=ORIENTED_EDGE('',*,*,#3657,.F.);
#3703=ORIENTED_EDGE('',*,*,#2617,.T.);
#3704=ORIENTED_EDGE('',*,*,#3689,.T.);
#3705=EDGE_LOOP('',(#3701,#3702,#3703,#3704));
#3706=FACE_BOUND('',#3705,.T.);
#3707=ADVANCED_FACE('F1919',(#3706),#3700,.T.);
#3708=CARTESIAN_POINT('',(-8.00000000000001,18.9214960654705,72.497944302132));
#3709=DIRECTION('',(0.,-0.0523359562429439,0.998629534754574));
#3710=DIRECTION('',(0.,-0.998629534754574,-0.0523359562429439));
#3711=AXIS2_PLACEMENT_3D('',#3708,#3709,#3710);
#3712=PLANE('',#3711);
#3713=ORIENTED_EDGE('',*,*,#542,.F.);
#3714=DIRECTION('',(-0.052264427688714,0.997264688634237,0.052264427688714));
#3715=VECTOR('',#3714,1.);
#3716=CARTESIAN_POINT('',(-9.46653685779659,18.3222063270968,72.4665368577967));
#3717=LINE('',#3716,#3715);
#3718=CARTESIAN_POINT('',(-9.29242740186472,14.9999999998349,72.2924274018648));
#3719=VERTEX_POINT('',#3718);
#3720=EDGE_CURVE('E1407',#3719,#535,#3717,.T.);
#3721=ORIENTED_EDGE('',*,*,#3720,.F.);
#3722=DIRECTION('',(1.,0.,0.));
#3723=VECTOR('',#3722,1.);
#3724=CARTESIAN_POINT('',(-4.,14.9999999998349,72.2924274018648));
#3725=LINE('',#3724,#3723);
#3726=CARTESIAN_POINT('',(-2.70757259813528,14.9999999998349,72.2924274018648));
#3727=VERTEX_POINT('',#3726);
#3728=EDGE_CURVE('E1398',#3719,#3727,#3725,.T.);
#3729=ORIENTED_EDGE('',*,*,#3728,.T.);
#3730=DIRECTION('',(0.052264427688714,0.997264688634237,0.052264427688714));
#3731=VECTOR('',#3730,1.);
#3732=CARTESIAN_POINT('',(-2.51707371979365,18.6349351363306,72.4829262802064));
#3733=LINE('',#3732,#3731);
#3734=EDGE_CURVE('E1491',#3727,#517,#3733,.T.);
#3735=ORIENTED_EDGE('',*,*,#3734,.T.);
#3736=EDGE_LOOP('',(#3713,#3721,#3729,#3735));
#3737=FACE_BOUND('',#3736,.T.);
#3738=ADVANCED_FACE('F1923',(#3737),#3712,.T.);
#3739=CARTESIAN_POINT('',(-9.49794430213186,18.9214960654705,61.0000000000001));
#3740=DIRECTION('',(-0.998629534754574,-0.0523359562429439,0.));
#3741=DIRECTION('',(0.0523359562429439,-0.998629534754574,0.));
#3742=AXIS2_PLACEMENT_3D('',#3739,#3740,#3741);
#3743=PLANE('',#3742);
#3744=ORIENTED_EDGE('',*,*,#536,.F.);
#3745=DIRECTION('',(-0.052264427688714,0.997264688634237,-0.052264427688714));
#3746=VECTOR('',#3745,1.);
#3747=CARTESIAN_POINT('',(-9.48292628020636,18.6349351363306,59.5170737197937));
#3748=LINE('',#3747,#3746);
#3749=CARTESIAN_POINT('',(-9.29242740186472,14.9999999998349,59.7075725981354));
#3750=VERTEX_POINT('',#3749);
#3751=EDGE_CURVE('E1497',#3750,#527,#3748,.T.);
#3752=ORIENTED_EDGE('',*,*,#3751,.F.);
#3753=DIRECTION('',(0.,0.,1.));
#3754=VECTOR('',#3753,1.);
#3755=CARTESIAN_POINT('',(-9.29242740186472,14.9999999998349,71.0000000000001));
#3756=LINE('',#3755,#3754);
#3757=EDGE_CURVE('E1495',#3750,#3719,#3756,.T.);
#3758=ORIENTED_EDGE('',*,*,#3757,.T.);
#3759=ORIENTED_EDGE('',*,*,#3720,.T.);
#3760=EDGE_LOOP('',(#3744,#3752,#3758,#3759));
#3761=FACE_BOUND('',#3760,.T.);
#3762=ADVANCED_FACE('F1927',(#3761),#3743,.T.);
#3763=CARTESIAN_POINT('',(-4.,18.9214960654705,59.5020556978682));
#3764=DIRECTION('',(0.,-0.0523359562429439,-0.998629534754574));
#3765=DIRECTION('',(0.,0.998629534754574,-0.0523359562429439));
#3766=AXIS2_PLACEMENT_3D('',#3763,#3764,#3765);
#3767=PLANE('',#3766);
#3768=ORIENTED_EDGE('',*,*,#528,.F.);
#3769=DIRECTION('',(0.052264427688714,0.997264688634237,-0.052264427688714));
#3770=VECTOR('',#3769,1.);
#3771=CARTESIAN_POINT('',(-2.53346314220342,18.3222063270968,59.5334631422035));
#3772=LINE('',#3771,#3770);
#3773=CARTESIAN_POINT('',(-2.70757259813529,14.9999999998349,59.7075725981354));
#3774=VERTEX_POINT('',#3773);
#3775=EDGE_CURVE('E1494',#3774,#519,#3772,.T.);
#3776=ORIENTED_EDGE('',*,*,#3775,.F.);
#3777=DIRECTION('',(-1.,0.,0.));
#3778=VECTOR('',#3777,1.);
#3779=CARTESIAN_POINT('',(-4.,14.9999999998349,59.7075725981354));
#3780=LINE('',#3779,#3778);
#3781=EDGE_CURVE('E1585',#3774,#3750,#3780,.T.);
#3782=ORIENTED_EDGE('',*,*,#3781,.T.);
#3783=ORIENTED_EDGE('',*,*,#3751,.T.);
#3784=EDGE_LOOP('',(#3768,#3776,#3782,#3783));
#3785=FACE_BOUND('',#3784,.T.);
#3786=ADVANCED_FACE('F1931',(#3785),#3767,.T.);
#3787=CARTESIAN_POINT('',(-2.50205569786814,18.9214960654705,71.0000000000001));
#3788=DIRECTION('',(0.998629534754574,-0.0523359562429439,0.));
#3789=DIRECTION('',(0.0523359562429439,0.998629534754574,0.));
#3790=AXIS2_PLACEMENT_3D('',#3787,#3788,#3789);
#3791=PLANE('',#3790);
#3792=ORIENTED_EDGE('',*,*,#520,.F.);
#3793=ORIENTED_EDGE('',*,*,#3734,.F.);
#3794=DIRECTION('',(0.,0.,-1.));
#3795=VECTOR('',#3794,1.);
#3796=CARTESIAN_POINT('',(-2.70757259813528,14.9999999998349,71.0000000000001));
#3797=LINE('',#3796,#3795);
#3798=EDGE_CURVE('E1582',#3727,#3774,#3797,.T.);
#3799=ORIENTED_EDGE('',*,*,#3798,.T.);
#3800=ORIENTED_EDGE('',*,*,#3775,.T.);
#3801=EDGE_LOOP('',(#3792,#3793,#3799,#3800));
#3802=FACE_BOUND('',#3801,.T.);
#3803=ADVANCED_FACE('F1935',(#3802),#3791,.T.);
#3804=CARTESIAN_POINT('',(-4.,14.9999999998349,71.0000000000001));
#3805=DIRECTION('',(0.,1.,0.));
#3806=DIRECTION('',(0.,0.,1.));
#3807=AXIS2_PLACEMENT_3D('',#3804,#3805,#3806);
#3808=PLANE('',#3807);
#3809=ORIENTED_EDGE('',*,*,#2267,.T.);
#3810=ORIENTED_EDGE('',*,*,#2337,.T.);
#3811=ORIENTED_EDGE('',*,*,#2315,.T.);
#3812=ORIENTED_EDGE('',*,*,#2291,.T.);
#3813=EDGE_LOOP('',(#3809,#3810,#3811,#3812));
#3814=FACE_BOUND('',#3813,.T.);
#3815=ORIENTED_EDGE('',*,*,#3728,.F.);
#3816=ORIENTED_EDGE('',*,*,#3757,.F.);
#3817=ORIENTED_EDGE('',*,*,#3781,.F.);
#3818=ORIENTED_EDGE('',*,*,#3798,.F.);
#3819=EDGE_LOOP('',(#3815,#3816,#3817,#3818));
#3820=FACE_BOUND('',#3819,.T.);
#3821=ADVANCED_FACE('F1939',(#3814,#3820),#3808,.F.);
#3822=CARTESIAN_POINT('',(0.,18.9214960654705,77.5000000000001));
#3823=DIRECTION('',(0.,1.,0.));
#3824=DIRECTION('',(0.,0.,1.));
#3825=AXIS2_PLACEMENT_3D('',#3822,#3823,#3824);
#3826=CONICAL_SURFACE('',#3825,4.99794430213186,0.0523598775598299);
#3827=CARTESIAN_POINT('',(0.,14.9999999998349,77.5000000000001));
#3828=DIRECTION('',(0.,1.,0.));
#3829=DIRECTION('',(0.,0.,1.));
#3830=AXIS2_PLACEMENT_3D('',#3827,#3828,#3829);
#3831=CIRCLE('',#3830,4.79242740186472);
#3832=CARTESIAN_POINT('',(4.79242740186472,14.9999999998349,77.5000000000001));
#3833=VERTEX_POINT('',#3832);
#3834=CARTESIAN_POINT('',(-4.79242740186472,14.9999999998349,77.5000000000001));
#3835=VERTEX_POINT('',#3834);
#3836=EDGE_CURVE('E1386',#3833,#3835,#3831,.T.);
#3837=ORIENTED_EDGE('',*,*,#3836,.T.);
#3838=DIRECTION('',(0.0523359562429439,-0.998629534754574,0.));
#3839=VECTOR('',#3838,1.);
#3840=CARTESIAN_POINT('',(-4.99794430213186,18.9214960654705,77.5000000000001));
#3841=LINE('',#3840,#3839);
#3842=EDGE_CURVE('E1500',#3835,#435,#3841,.F.);
#3843=ORIENTED_EDGE('',*,*,#3842,.T.);
#3844=ORIENTED_EDGE('',*,*,#436,.F.);
#3845=DIRECTION('',(0.0523359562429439,0.998629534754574,0.));
#3846=VECTOR('',#3845,1.);
#3847=CARTESIAN_POINT('',(4.99794430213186,18.9214960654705,77.5000000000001));
#3848=LINE('',#3847,#3846);
#3849=EDGE_CURVE('E1394',#3833,#433,#3848,.T.);
#3850=ORIENTED_EDGE('',*,*,#3849,.F.);
#3851=EDGE_LOOP('',(#3837,#3843,#3844,#3850));
#3852=FACE_BOUND('',#3851,.T.);
#3853=ADVANCED_FACE('F1608',(#3852),#3826,.T.);
#3854=CARTESIAN_POINT('',(4.99794430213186,18.9214960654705,82.0000000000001));
#3855=DIRECTION('',(0.998629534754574,-0.0523359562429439,0.));
#3856=DIRECTION('',(0.0523359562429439,0.998629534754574,0.));
#3857=AXIS2_PLACEMENT_3D('',#3854,#3855,#3856);
#3858=PLANE('',#3857);
#3859=ORIENTED_EDGE('',*,*,#458,.F.);
#3860=DIRECTION('',(0.052264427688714,0.997264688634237,0.052264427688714));
#3861=VECTOR('',#3860,1.);
#3862=CARTESIAN_POINT('',(4.97473156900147,18.4785707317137,83.4747315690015));
#3863=LINE('',#3862,#3861);
#3864=CARTESIAN_POINT('',(4.79242740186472,14.9999999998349,83.2924274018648));
#3865=VERTEX_POINT('',#3864);
#3866=EDGE_CURVE('E1506',#3865,#451,#3863,.T.);
#3867=ORIENTED_EDGE('',*,*,#3866,.F.);
#3868=DIRECTION('',(0.,0.,-1.));
#3869=VECTOR('',#3868,1.);
#3870=CARTESIAN_POINT('',(4.79242740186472,14.9999999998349,77.5000000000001));
#3871=LINE('',#3870,#3869);
#3872=EDGE_CURVE('E1504',#3865,#3833,#3871,.T.);
#3873=ORIENTED_EDGE('',*,*,#3872,.T.);
#3874=ORIENTED_EDGE('',*,*,#3849,.T.);
#3875=EDGE_LOOP('',(#3859,#3867,#3873,#3874));
#3876=FACE_BOUND('',#3875,.T.);
#3877=ADVANCED_FACE('F1600',(#3876),#3858,.T.);
#3878=CARTESIAN_POINT('',(-3.5,18.9214960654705,83.4979443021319));
#3879=DIRECTION('',(0.,-0.0523359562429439,0.998629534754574));
#3880=DIRECTION('',(0.,-0.998629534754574,-0.0523359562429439));
#3881=AXIS2_PLACEMENT_3D('',#3878,#3879,#3880);
#3882=PLANE('',#3881);
#3883=ORIENTED_EDGE('',*,*,#3866,.T.);
#3884=ORIENTED_EDGE('',*,*,#452,.F.);
#3885=DIRECTION('',(-0.052264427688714,0.997264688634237,0.052264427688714));
#3886=VECTOR('',#3885,1.);
#3887=CARTESIAN_POINT('',(-4.98156049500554,18.6088744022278,83.4815604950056));
#3888=LINE('',#3887,#3886);
#3889=CARTESIAN_POINT('',(-4.79242740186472,14.9999999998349,83.2924274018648));
#3890=VERTEX_POINT('',#3889);
#3891=EDGE_CURVE('E1503',#3890,#443,#3888,.T.);
#3892=ORIENTED_EDGE('',*,*,#3891,.F.);
#3893=DIRECTION('',(1.,0.,0.));
#3894=VECTOR('',#3893,1.);
#3895=CARTESIAN_POINT('',(0.,14.9999999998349,83.2924274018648));
#3896=LINE('',#3895,#3894);
#3897=EDGE_CURVE('E1594',#3890,#3865,#3896,.T.);
#3898=ORIENTED_EDGE('',*,*,#3897,.T.);
#3899=EDGE_LOOP('',(#3883,#3884,#3892,#3898));
#3900=FACE_BOUND('',#3899,.T.);
#3901=ADVANCED_FACE('F1618',(#3900),#3882,.T.);
#3902=CARTESIAN_POINT('',(-4.99794430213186,18.9214960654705,77.5000000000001));
#3903=DIRECTION('',(-0.998629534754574,-0.0523359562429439,0.));
#3904=DIRECTION('',(0.0523359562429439,-0.998629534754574,0.));
#3905=AXIS2_PLACEMENT_3D('',#3902,#3903,#3904);
#3906=PLANE('',#3905);
#3907=ORIENTED_EDGE('',*,*,#444,.F.);
#3908=ORIENTED_EDGE('',*,*,#3842,.F.);
#3909=DIRECTION('',(0.,0.,1.));
#3910=VECTOR('',#3909,1.);
#3911=CARTESIAN_POINT('',(-4.79242740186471,14.9999999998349,77.5000000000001));
#3912=LINE('',#3911,#3910);
#3913=EDGE_CURVE('E1591',#3835,#3890,#3912,.T.);
#3914=ORIENTED_EDGE('',*,*,#3913,.T.);
#3915=ORIENTED_EDGE('',*,*,#3891,.T.);
#3916=EDGE_LOOP('',(#3907,#3908,#3914,#3915));
#3917=FACE_BOUND('',#3916,.T.);
#3918=ADVANCED_FACE('F1612',(#3917),#3906,.T.);
#3919=CARTESIAN_POINT('',(0.,14.9999999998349,77.5000000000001));
#3920=DIRECTION('',(0.,1.,0.));
#3921=DIRECTION('',(0.,0.,1.));
#3922=AXIS2_PLACEMENT_3D('',#3919,#3920,#3921);
#3923=PLANE('',#3922);
#3924=ORIENTED_EDGE('',*,*,#2411,.T.);
#3925=ORIENTED_EDGE('',*,*,#2388,.T.);
#3926=ORIENTED_EDGE('',*,*,#2364,.T.);
#3927=ORIENTED_EDGE('',*,*,#2434,.T.);
#3928=EDGE_LOOP('',(#3924,#3925,#3926,#3927));
#3929=FACE_BOUND('',#3928,.T.);
#3930=ORIENTED_EDGE('',*,*,#3872,.F.);
#3931=ORIENTED_EDGE('',*,*,#3897,.F.);
#3932=ORIENTED_EDGE('',*,*,#3913,.F.);
#3933=ORIENTED_EDGE('',*,*,#3836,.F.);
#3934=EDGE_LOOP('',(#3930,#3931,#3932,#3933));
#3935=FACE_BOUND('',#3934,.T.);
#3936=ADVANCED_FACE('F1604',(#3929,#3935),#3923,.F.);
#3937=CARTESIAN_POINT('',(-10.4979443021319,20.9214960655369,111.));
#3938=DIRECTION('',(-0.998629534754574,-0.0523359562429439,0.));
#3939=DIRECTION('',(0.0523359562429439,-0.998629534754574,0.));
#3940=AXIS2_PLACEMENT_3D('',#3937,#3938,#3939);
#3941=PLANE('',#3940);
#3942=ORIENTED_EDGE('',*,*,#186,.F.);
#3943=ORIENTED_EDGE('',*,*,#310,.F.);
#3944=ORIENTED_EDGE('',*,*,#2692,.T.);
#3945=ORIENTED_EDGE('',*,*,#217,.T.);
#3946=EDGE_LOOP('',(#3942,#3943,#3944,#3945));
#3947=FACE_BOUND('',#3946,.T.);
#3948=ADVANCED_FACE('F2777',(#3947),#3941,.T.);
#3949=DIRECTION('',(-0.052264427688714,-0.997264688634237,0.052264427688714));
#3950=VECTOR('',#3949,1.);
#3951=CARTESIAN_POINT('',(1.08511657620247,20.3944051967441,101.529679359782));
#3952=LINE('',#3951,#3950);
#3953=EDGE_CURVE('E1737',#2821,#2646,#3952,.T.);
#3954=ORIENTED_EDGE('',*,*,#3953,.F.);
#3955=ORIENTED_EDGE('',*,*,#2822,.F.);
#3956=DIRECTION('',(0.052264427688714,0.997264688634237,-0.052264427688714));
#3957=VECTOR('',#3956,1.);
#3958=CARTESIAN_POINT('',(10.4719999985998,20.4264492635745,101.5280000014));
#3959=LINE('',#3958,#3957);
#3960=EDGE_CURVE('E1514',#2650,#2817,#3959,.T.);
#3961=ORIENTED_EDGE('',*,*,#3960,.F.);
#3962=ORIENTED_EDGE('',*,*,#2651,.T.);
#3963=EDGE_LOOP('',(#3954,#3955,#3961,#3962));
#3964=FACE_BOUND('',#3963,.T.);
#3965=ADVANCED_FACE('F2781',(#3964),#288,.T.);
#3966=CARTESIAN_POINT('',(10.4979443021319,20.9214960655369,111.));
#3967=DIRECTION('',(0.998629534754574,-0.0523359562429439,0.));
#3968=DIRECTION('',(0.0523359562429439,0.998629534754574,0.));
#3969=AXIS2_PLACEMENT_3D('',#3966,#3967,#3968);
#3970=PLANE('',#3969);
#3971=ORIENTED_EDGE('',*,*,#2818,.F.);
#3972=DIRECTION('',(0.052264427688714,0.997264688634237,0.052264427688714));
#3973=VECTOR('',#3972,1.);
#3974=CARTESIAN_POINT('',(10.4446842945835,19.9052345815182,112.444684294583));
#3975=LINE('',#3974,#3973);
#3976=EDGE_CURVE('E1511',#2658,#2809,#3975,.T.);
#3977=ORIENTED_EDGE('',*,*,#3976,.F.);
#3978=ORIENTED_EDGE('',*,*,#2659,.T.);
#3979=ORIENTED_EDGE('',*,*,#3960,.T.);
#3980=EDGE_LOOP('',(#3971,#3977,#3978,#3979));
#3981=FACE_BOUND('',#3980,.T.);
#3982=ADVANCED_FACE('F2058',(#3981),#3970,.T.);
#3983=DIRECTION('',(0.052264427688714,0.997264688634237,0.052264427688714));
#3984=VECTOR('',#3983,1.);
#3985=CARTESIAN_POINT('',(1.08511657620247,20.3944051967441,112.470320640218));
#3986=LINE('',#3985,#3984);
#3987=EDGE_CURVE('E1704',#2662,#2803,#3986,.T.);
#3988=ORIENTED_EDGE('',*,*,#3987,.F.);
#3989=ORIENTED_EDGE('',*,*,#2663,.T.);
#3990=ORIENTED_EDGE('',*,*,#3976,.T.);
#3991=ORIENTED_EDGE('',*,*,#2810,.F.);
#3992=EDGE_LOOP('',(#3988,#3989,#3990,#3991));
#3993=FACE_BOUND('',#3992,.T.);
#3994=ADVANCED_FACE('F2051',(#3993),#195,.T.);
#3995=CARTESIAN_POINT('',(-19.9327032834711,10.,52.7500000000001));
#3996=DIRECTION('',(0.,0.0523359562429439,-0.998629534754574));
#3997=DIRECTION('',(0.,0.998629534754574,0.0523359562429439));
#3998=AXIS2_PLACEMENT_3D('',#3995,#3996,#3997);
#3999=PLANE('',#3998);
#4000=ORIENTED_EDGE('',*,*,#2895,.F.);
#4001=ORIENTED_EDGE('',*,*,#91,.T.);
#4002=ORIENTED_EDGE('',*,*,#2760,.T.);
#4003=ORIENTED_EDGE('',*,*,#345,.T.);
#4004=ORIENTED_EDGE('',*,*,#395,.T.);
#4005=ORIENTED_EDGE('',*,*,#467,.T.);
#4006=ORIENTED_EDGE('',*,*,#422,.T.);
#4007=ORIENTED_EDGE('',*,*,#364,.T.);
#4008=EDGE_LOOP('',(#4000,#4001,#4002,#4003,#4004,#4005,#4006,#4007));
#4009=FACE_BOUND('',#4008,.T.);
#4010=ADVANCED_FACE('F2049',(#4009),#3999,.F.);
#4011=CARTESIAN_POINT('',(-19.9327032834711,10.,51.2500000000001));
#4012=DIRECTION('',(0.,0.0523359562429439,0.998629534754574));
#4013=DIRECTION('',(0.,-0.998629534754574,0.0523359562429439));
#4014=AXIS2_PLACEMENT_3D('',#4011,#4012,#4013);
#4015=PLANE('',#4014);
#4016=ORIENTED_EDGE('',*,*,#2767,.F.);
#4017=ORIENTED_EDGE('',*,*,#74,.T.);
#4018=ORIENTED_EDGE('',*,*,#2888,.T.);
#4019=ORIENTED_EDGE('',*,*,#567,.F.);
#4020=ORIENTED_EDGE('',*,*,#626,.F.);
#4021=ORIENTED_EDGE('',*,*,#685,.F.);
#4022=ORIENTED_EDGE('',*,*,#601,.F.);
#4023=ORIENTED_EDGE('',*,*,#587,.F.);
#4024=EDGE_LOOP('',(#4016,#4017,#4018,#4019,#4020,#4021,#4022,#4023));
#4025=FACE_BOUND('',#4024,.T.);
#4026=ADVANCED_FACE('F1789',(#4025),#4015,.F.);
#4027=CARTESIAN_POINT('',(-19.9327032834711,10.,87.7500000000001));
#4028=DIRECTION('',(0.,0.0523359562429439,-0.998629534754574));
#4029=DIRECTION('',(0.,0.998629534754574,0.0523359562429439));
#4030=AXIS2_PLACEMENT_3D('',#4027,#4028,#4029);
#4031=PLANE('',#4030);
#4032=ORIENTED_EDGE('',*,*,#2858,.F.);
#4033=ORIENTED_EDGE('',*,*,#49,.T.);
#4034=ORIENTED_EDGE('',*,*,#2793,.T.);
#4035=ORIENTED_EDGE('',*,*,#2840,.T.);
#4036=ORIENTED_EDGE('',*,*,#3273,.T.);
#4037=ORIENTED_EDGE('',*,*,#3336,.T.);
#4038=DIRECTION('',(-0.052264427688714,-0.997264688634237,-0.052264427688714));
#4039=VECTOR('',#4038,1.);
#4040=CARTESIAN_POINT('',(0.484445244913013,8.93291342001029,87.6940763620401));
#4041=LINE('',#4040,#4039);
#4042=EDGE_CURVE('E1726',#3333,#2644,#4041,.T.);
#4043=ORIENTED_EDGE('',*,*,#4042,.T.);
#4044=ORIENTED_EDGE('',*,*,#2707,.T.);
#4045=DIRECTION('',(0.052264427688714,-0.997264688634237,-0.052264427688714));
#4046=VECTOR('',#4045,1.);
#4047=CARTESIAN_POINT('',(-0.593340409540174,11.0107569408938,87.8029715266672));
#4048=LINE('',#4047,#4046);
#4049=EDGE_CURVE('E1713',#263,#2700,#4048,.T.);
#4050=ORIENTED_EDGE('',*,*,#4049,.F.);
#4051=ORIENTED_EDGE('',*,*,#266,.T.);
#4052=ORIENTED_EDGE('',*,*,#3308,.T.);
#4053=ORIENTED_EDGE('',*,*,#148,.T.);
#4054=EDGE_LOOP('',(#4032,#4033,#4034,#4035,#4036,#4037,#4043,#4044,#4050,#4051,#4052,#4053));
#4055=FACE_BOUND('',#4054,.T.);
#4056=ADVANCED_FACE('F1217',(#4055),#4031,.F.);
#4057=CARTESIAN_POINT('',(-19.9327032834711,10.,86.2500000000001));
#4058=DIRECTION('',(0.,0.0523359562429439,0.998629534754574));
#4059=DIRECTION('',(0.,-0.998629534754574,0.0523359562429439));
#4060=AXIS2_PLACEMENT_3D('',#4057,#4058,#4059);
#4061=PLANE('',#4060);
#4062=ORIENTED_EDGE('',*,*,#2753,.F.);
#4063=ORIENTED_EDGE('',*,*,#32,.T.);
#4064=ORIENTED_EDGE('',*,*,#2902,.T.);
#4065=ORIENTED_EDGE('',*,*,#358,.F.);
#4066=ORIENTED_EDGE('',*,*,#415,.F.);
#4067=ORIENTED_EDGE('',*,*,#474,.F.);
#4068=ORIENTED_EDGE('',*,*,#381,.F.);
#4069=ORIENTED_EDGE('',*,*,#331,.F.);
#4070=EDGE_LOOP('',(#4062,#4063,#4064,#4065,#4066,#4067,#4068,#4069));
#4071=FACE_BOUND('',#4070,.T.);
#4072=ADVANCED_FACE('F1637',(#4071),#4061,.F.);
#4073=CARTESIAN_POINT('',(0.75,13.9999999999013,66.4999999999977));
#4074=DIRECTION('',(0.998629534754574,-0.0523359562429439,0.));
#4075=DIRECTION('',(0.0523359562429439,0.998629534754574,0.));
#4076=AXIS2_PLACEMENT_3D('',#4073,#4074,#4075);
#4077=PLANE('',#4076);
#4078=ORIENTED_EDGE('',*,*,#2830,.T.);
#4079=ORIENTED_EDGE('',*,*,#3953,.T.);
#4080=ORIENTED_EDGE('',*,*,#2647,.F.);
#4081=ORIENTED_EDGE('',*,*,#4042,.F.);
#4082=ORIENTED_EDGE('',*,*,#3334,.T.);
#4083=ORIENTED_EDGE('',*,*,#3295,.T.);
#4084=EDGE_LOOP('',(#4078,#4079,#4080,#4081,#4082,#4083));
#4085=FACE_BOUND('',#4084,.T.);
#4086=ADVANCED_FACE('F2945',(#4085),#4077,.T.);
#4087=CARTESIAN_POINT('',(-0.75,13.9999999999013,66.4999999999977));
#4088=DIRECTION('',(0.998629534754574,0.0523359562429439,0.));
#4089=DIRECTION('',(-0.0523359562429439,0.998629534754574,0.));
#4090=AXIS2_PLACEMENT_3D('',#4087,#4088,#4089);
#4091=PLANE('',#4090);
#4092=ORIENTED_EDGE('',*,*,#296,.F.);
#4093=ORIENTED_EDGE('',*,*,#172,.F.);
#4094=ORIENTED_EDGE('',*,*,#241,.F.);
#4095=ORIENTED_EDGE('',*,*,#272,.F.);
#4096=ORIENTED_EDGE('',*,*,#4049,.T.);
#4097=ORIENTED_EDGE('',*,*,#2701,.T.);
#4098=EDGE_LOOP('',(#4092,#4093,#4094,#4095,#4096,#4097));
#4099=FACE_BOUND('',#4098,.T.);
#4100=ADVANCED_FACE('F2950',(#4099),#4091,.F.);
#4101=CARTESIAN_POINT('',(0.75,13.9999999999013,66.4999999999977));
#4102=DIRECTION('',(0.998629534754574,-0.0523359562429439,0.));
#4103=DIRECTION('',(0.0523359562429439,0.998629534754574,0.));
#4104=AXIS2_PLACEMENT_3D('',#4101,#4102,#4103);
#4105=PLANE('',#4104);
#4106=ORIENTED_EDGE('',*,*,#3091,.F.);
#4107=ORIENTED_EDGE('',*,*,#2671,.F.);
#4108=ORIENTED_EDGE('',*,*,#3987,.T.);
#4109=ORIENTED_EDGE('',*,*,#2806,.T.);
#4110=EDGE_LOOP('',(#4106,#4107,#4108,#4109));
#4111=FACE_BOUND('',#4110,.T.);
#4112=ADVANCED_FACE('F2961',(#4111),#4105,.T.);
#4113=CARTESIAN_POINT('',(-0.75,13.9999999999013,66.4999999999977));
#4114=DIRECTION('',(0.998629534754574,0.0523359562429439,0.));
#4115=DIRECTION('',(-0.0523359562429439,0.998629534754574,0.));
#4116=AXIS2_PLACEMENT_3D('',#4113,#4114,#4115);
#4117=PLANE('',#4116);
#4118=ORIENTED_EDGE('',*,*,#2685,.T.);
#4119=ORIENTED_EDGE('',*,*,#3107,.T.);
#4120=ORIENTED_EDGE('',*,*,#124,.F.);
#4121=ORIENTED_EDGE('',*,*,#210,.F.);
#4122=EDGE_LOOP('',(#4118,#4119,#4120,#4121));
#4123=FACE_BOUND('',#4122,.T.);
#4124=ADVANCED_FACE('F781',(#4123),#4117,.F.);
#4125=CLOSED_SHELL('',(#60,#102,#190,#221,#252,#283,#314,#349,#368,#399,#426,#546,#593,#615,
#637,#757,#797,#828,#927,#958,#989,#1167,#1238,#1285,#1302,#1319,#1336,#1353,#1365,#1382,#1399,
#1416,#1433,#1445,#1477,#1494,#1511,#1547,#1578,#1602,#1626,#1643,#1861,#1892,#1916,#1940,#1957,
#1988,#2012,#2036,#2053,#2085,#2109,#2133,#2150,#2181,#2205,#2229,#2246,#2277,#2301,#2325,#2342,
#2374,#2398,#2422,#2439,#2470,#2494,#2518,#2535,#2581,#2627,#2711,#2742,#2797,#2847,#2906,#2928,
#2999,#3046,#3063,#3080,#3111,#3128,#3140,#3157,#3174,#3191,#3208,#3220,#3242,#3254,#3266,#3288,
#3303,#3315,#3327,#3342,#3364,#3381,#3398,#3410,#3441,#3465,#3489,#3506,#3524,#3556,#3580,#3604,
#3621,#3639,#3661,#3678,#3695,#3707,#3738,#3762,#3786,#3803,#3821,#3853,#3877,#3901,#3918,#3936,
#3948,#3965,#3982,#3994,#4010,#4026,#4056,#4072,#4086,#4100,#4112,#4124));
#4126=MANIFOLD_SOLID_BREP('B2',#4125);
#4127=ADVANCED_BREP_SHAPE_REPRESENTATION('',(#18,#4126),#14);
#4128=SHAPE_DEFINITION_REPRESENTATION(#9,#4127);
ENDSEC;
END-ISO-10303-21;
